VERSION 5.8 ;
BUSBITCHARS "[]" ;
DIVIDERCHAR "/" ;
UNITS
    DATABASE MICRONS 1000 ;
END UNITS

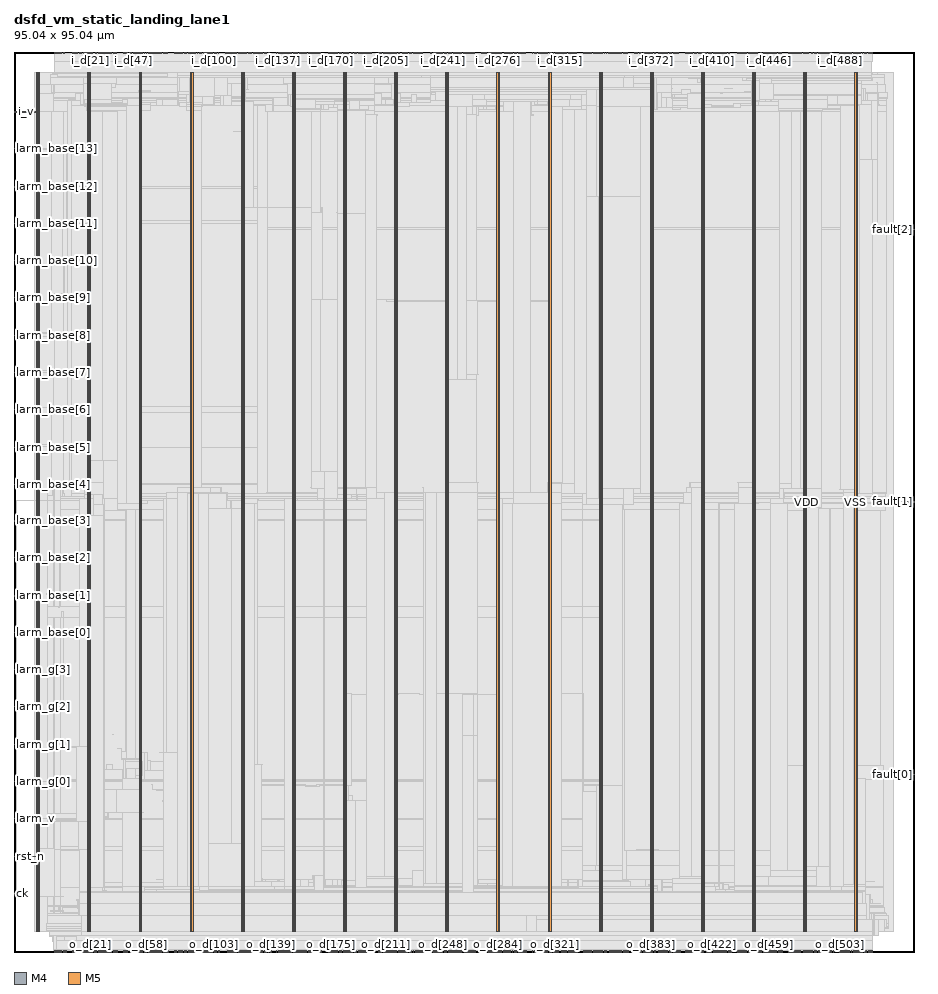
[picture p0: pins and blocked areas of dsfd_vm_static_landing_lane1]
MACRO dsfd_vm_static_landing_lane1
  FOREIGN dsfd_vm_static_landing_lane1 0 0 ;
  CLASS BLOCK ;
  SIZE 95.04 BY 95.04 ;
  PIN ck
    DIRECTION INPUT ;
    USE SIGNAL ;
    PORT
      LAYER M4 ;
        RECT  0 6.192 0.192 6.216 ;
    END
    PORT
      LAYER M4 ;
        RECT  0.156 6.192 0.275 6.216 ;
    END
  END ck
  PIN fault[0]
    DIRECTION OUTPUT ;
    USE SIGNAL ;
    PORT
      LAYER M4 ;
        RECT  94.848 18.72 95.04 18.744 ;
    END
    PORT
      LAYER M4 ;
        RECT  93.481 18.72 94.86 18.744 ;
    END
  END fault[0]
  PIN fault[1]
    DIRECTION OUTPUT ;
    USE SIGNAL ;
    PORT
      LAYER M4 ;
        RECT  94.848 47.52 95.04 47.544 ;
    END
    PORT
      LAYER M4 ;
        RECT  94.021 47.52 94.86 47.544 ;
    END
  END fault[1]
  PIN fault[2]
    DIRECTION OUTPUT ;
    USE SIGNAL ;
    PORT
      LAYER M4 ;
        RECT  94.848 76.32 95.04 76.344 ;
    END
    PORT
      LAYER M4 ;
        RECT  93.481 76.32 94.86 76.344 ;
    END
  END fault[2]
  PIN i_d[0]
    DIRECTION INPUT ;
    USE SIGNAL ;
    PORT
      LAYER M5 ;
        RECT  4.32 94.848 4.344 95.04 ;
    END
  END i_d[0]
  PIN i_d[100]
    DIRECTION INPUT ;
    USE SIGNAL ;
    PORT
      LAYER M5 ;
        RECT  21.12 94.848 21.144 95.04 ;
    END
  END i_d[100]
  PIN i_d[101]
    DIRECTION INPUT ;
    USE SIGNAL ;
    PORT
      LAYER M5 ;
        RECT  21.264 94.848 21.288 95.04 ;
    END
  END i_d[101]
  PIN i_d[102]
    DIRECTION INPUT ;
    USE SIGNAL ;
    PORT
      LAYER M5 ;
        RECT  21.408 94.848 21.432 95.04 ;
    END
  END i_d[102]
  PIN i_d[103]
    DIRECTION INPUT ;
    USE SIGNAL ;
    PORT
      LAYER M5 ;
        RECT  21.552 94.848 21.576 95.04 ;
    END
  END i_d[103]
  PIN i_d[104]
    DIRECTION INPUT ;
    USE SIGNAL ;
    PORT
      LAYER M5 ;
        RECT  22.368 94.848 22.392 95.04 ;
    END
  END i_d[104]
  PIN i_d[105]
    DIRECTION INPUT ;
    USE SIGNAL ;
    PORT
      LAYER M5 ;
        RECT  22.512 94.848 22.536 95.04 ;
    END
  END i_d[105]
  PIN i_d[106]
    DIRECTION INPUT ;
    USE SIGNAL ;
    PORT
      LAYER M5 ;
        RECT  22.656 94.848 22.68 95.04 ;
    END
  END i_d[106]
  PIN i_d[107]
    DIRECTION INPUT ;
    USE SIGNAL ;
    PORT
      LAYER M5 ;
        RECT  22.8 94.848 22.824 95.04 ;
    END
  END i_d[107]
  PIN i_d[108]
    DIRECTION INPUT ;
    USE SIGNAL ;
    PORT
      LAYER M5 ;
        RECT  22.944 94.848 22.968 95.04 ;
    END
  END i_d[108]
  PIN i_d[109]
    DIRECTION INPUT ;
    USE SIGNAL ;
    PORT
      LAYER M5 ;
        RECT  23.088 94.848 23.112 95.04 ;
    END
  END i_d[109]
  PIN i_d[10]
    DIRECTION INPUT ;
    USE SIGNAL ;
    PORT
      LAYER M5 ;
        RECT  6.432 94.848 6.456 95.04 ;
    END
  END i_d[10]
  PIN i_d[110]
    DIRECTION INPUT ;
    USE SIGNAL ;
    PORT
      LAYER M5 ;
        RECT  23.232 94.848 23.256 95.04 ;
    END
  END i_d[110]
  PIN i_d[111]
    DIRECTION INPUT ;
    USE SIGNAL ;
    PORT
      LAYER M5 ;
        RECT  23.376 94.848 23.4 95.04 ;
    END
  END i_d[111]
  PIN i_d[112]
    DIRECTION INPUT ;
    USE SIGNAL ;
    PORT
      LAYER M5 ;
        RECT  23.52 94.848 23.544 95.04 ;
    END
  END i_d[112]
  PIN i_d[113]
    DIRECTION INPUT ;
    USE SIGNAL ;
    PORT
      LAYER M5 ;
        RECT  23.664 94.848 23.688 95.04 ;
    END
  END i_d[113]
  PIN i_d[114]
    DIRECTION INPUT ;
    USE SIGNAL ;
    PORT
      LAYER M5 ;
        RECT  23.808 94.848 23.832 95.04 ;
    END
  END i_d[114]
  PIN i_d[115]
    DIRECTION INPUT ;
    USE SIGNAL ;
    PORT
      LAYER M5 ;
        RECT  23.952 94.848 23.976 95.04 ;
    END
  END i_d[115]
  PIN i_d[116]
    DIRECTION INPUT ;
    USE SIGNAL ;
    PORT
      LAYER M5 ;
        RECT  24.096 94.848 24.12 95.04 ;
    END
  END i_d[116]
  PIN i_d[117]
    DIRECTION INPUT ;
    USE SIGNAL ;
    PORT
      LAYER M5 ;
        RECT  24.24 94.848 24.264 95.04 ;
    END
  END i_d[117]
  PIN i_d[118]
    DIRECTION INPUT ;
    USE SIGNAL ;
    PORT
      LAYER M5 ;
        RECT  24.384 94.848 24.408 95.04 ;
    END
  END i_d[118]
  PIN i_d[119]
    DIRECTION INPUT ;
    USE SIGNAL ;
    PORT
      LAYER M5 ;
        RECT  24.528 94.848 24.552 95.04 ;
    END
  END i_d[119]
  PIN i_d[11]
    DIRECTION INPUT ;
    USE SIGNAL ;
    PORT
      LAYER M5 ;
        RECT  6.576 94.848 6.6 95.04 ;
    END
  END i_d[11]
  PIN i_d[120]
    DIRECTION INPUT ;
    USE SIGNAL ;
    PORT
      LAYER M5 ;
        RECT  24.816 94.848 24.84 95.04 ;
    END
  END i_d[120]
  PIN i_d[121]
    DIRECTION INPUT ;
    USE SIGNAL ;
    PORT
      LAYER M5 ;
        RECT  24.96 94.848 24.984 95.04 ;
    END
  END i_d[121]
  PIN i_d[122]
    DIRECTION INPUT ;
    USE SIGNAL ;
    PORT
      LAYER M5 ;
        RECT  25.104 94.848 25.128 95.04 ;
    END
  END i_d[122]
  PIN i_d[123]
    DIRECTION INPUT ;
    USE SIGNAL ;
    PORT
      LAYER M5 ;
        RECT  25.248 94.848 25.272 95.04 ;
    END
  END i_d[123]
  PIN i_d[124]
    DIRECTION INPUT ;
    USE SIGNAL ;
    PORT
      LAYER M5 ;
        RECT  25.392 94.848 25.416 95.04 ;
    END
  END i_d[124]
  PIN i_d[125]
    DIRECTION INPUT ;
    USE SIGNAL ;
    PORT
      LAYER M5 ;
        RECT  25.536 94.848 25.56 95.04 ;
    END
  END i_d[125]
  PIN i_d[126]
    DIRECTION INPUT ;
    USE SIGNAL ;
    PORT
      LAYER M5 ;
        RECT  25.68 94.848 25.704 95.04 ;
    END
  END i_d[126]
  PIN i_d[127]
    DIRECTION INPUT ;
    USE SIGNAL ;
    PORT
      LAYER M5 ;
        RECT  25.824 94.848 25.848 95.04 ;
    END
  END i_d[127]
  PIN i_d[128]
    DIRECTION INPUT ;
    USE SIGNAL ;
    PORT
      LAYER M5 ;
        RECT  25.968 94.848 25.992 95.04 ;
    END
  END i_d[128]
  PIN i_d[129]
    DIRECTION INPUT ;
    USE SIGNAL ;
    PORT
      LAYER M5 ;
        RECT  26.112 94.848 26.136 95.04 ;
    END
  END i_d[129]
  PIN i_d[12]
    DIRECTION INPUT ;
    USE SIGNAL ;
    PORT
      LAYER M5 ;
        RECT  6.72 94.848 6.744 95.04 ;
    END
  END i_d[12]
  PIN i_d[130]
    DIRECTION INPUT ;
    USE SIGNAL ;
    PORT
      LAYER M5 ;
        RECT  26.256 94.848 26.28 95.04 ;
    END
  END i_d[130]
  PIN i_d[131]
    DIRECTION INPUT ;
    USE SIGNAL ;
    PORT
      LAYER M5 ;
        RECT  26.4 94.848 26.424 95.04 ;
    END
  END i_d[131]
  PIN i_d[132]
    DIRECTION INPUT ;
    USE SIGNAL ;
    PORT
      LAYER M5 ;
        RECT  26.544 94.848 26.568 95.04 ;
    END
  END i_d[132]
  PIN i_d[133]
    DIRECTION INPUT ;
    USE SIGNAL ;
    PORT
      LAYER M5 ;
        RECT  26.688 94.848 26.712 95.04 ;
    END
  END i_d[133]
  PIN i_d[134]
    DIRECTION INPUT ;
    USE SIGNAL ;
    PORT
      LAYER M5 ;
        RECT  26.832 94.848 26.856 95.04 ;
    END
  END i_d[134]
  PIN i_d[135]
    DIRECTION INPUT ;
    USE SIGNAL ;
    PORT
      LAYER M5 ;
        RECT  26.976 94.848 27 95.04 ;
    END
  END i_d[135]
  PIN i_d[136]
    DIRECTION INPUT ;
    USE SIGNAL ;
    PORT
      LAYER M5 ;
        RECT  27.744 94.848 27.768 95.04 ;
    END
  END i_d[136]
  PIN i_d[137]
    DIRECTION INPUT ;
    USE SIGNAL ;
    PORT
      LAYER M5 ;
        RECT  27.888 94.848 27.912 95.04 ;
    END
  END i_d[137]
  PIN i_d[138]
    DIRECTION INPUT ;
    USE SIGNAL ;
    PORT
      LAYER M5 ;
        RECT  28.032 94.848 28.056 95.04 ;
    END
  END i_d[138]
  PIN i_d[139]
    DIRECTION INPUT ;
    USE SIGNAL ;
    PORT
      LAYER M5 ;
        RECT  28.176 94.848 28.2 95.04 ;
    END
  END i_d[139]
  PIN i_d[13]
    DIRECTION INPUT ;
    USE SIGNAL ;
    PORT
      LAYER M5 ;
        RECT  6.864 94.848 6.888 95.04 ;
    END
  END i_d[13]
  PIN i_d[140]
    DIRECTION INPUT ;
    USE SIGNAL ;
    PORT
      LAYER M5 ;
        RECT  28.32 94.848 28.344 95.04 ;
    END
  END i_d[140]
  PIN i_d[141]
    DIRECTION INPUT ;
    USE SIGNAL ;
    PORT
      LAYER M5 ;
        RECT  28.464 94.848 28.488 95.04 ;
    END
  END i_d[141]
  PIN i_d[142]
    DIRECTION INPUT ;
    USE SIGNAL ;
    PORT
      LAYER M5 ;
        RECT  28.608 94.848 28.632 95.04 ;
    END
  END i_d[142]
  PIN i_d[143]
    DIRECTION INPUT ;
    USE SIGNAL ;
    PORT
      LAYER M5 ;
        RECT  28.752 94.848 28.776 95.04 ;
    END
  END i_d[143]
  PIN i_d[144]
    DIRECTION INPUT ;
    USE SIGNAL ;
    PORT
      LAYER M5 ;
        RECT  28.896 94.848 28.92 95.04 ;
    END
  END i_d[144]
  PIN i_d[145]
    DIRECTION INPUT ;
    USE SIGNAL ;
    PORT
      LAYER M5 ;
        RECT  29.04 94.848 29.064 95.04 ;
    END
  END i_d[145]
  PIN i_d[146]
    DIRECTION INPUT ;
    USE SIGNAL ;
    PORT
      LAYER M5 ;
        RECT  29.184 94.848 29.208 95.04 ;
    END
  END i_d[146]
  PIN i_d[147]
    DIRECTION INPUT ;
    USE SIGNAL ;
    PORT
      LAYER M5 ;
        RECT  29.328 94.848 29.352 95.04 ;
    END
  END i_d[147]
  PIN i_d[148]
    DIRECTION INPUT ;
    USE SIGNAL ;
    PORT
      LAYER M5 ;
        RECT  29.472 94.848 29.496 95.04 ;
    END
  END i_d[148]
  PIN i_d[149]
    DIRECTION INPUT ;
    USE SIGNAL ;
    PORT
      LAYER M5 ;
        RECT  29.616 94.848 29.64 95.04 ;
    END
  END i_d[149]
  PIN i_d[14]
    DIRECTION INPUT ;
    USE SIGNAL ;
    PORT
      LAYER M5 ;
        RECT  7.008 94.848 7.032 95.04 ;
    END
  END i_d[14]
  PIN i_d[150]
    DIRECTION INPUT ;
    USE SIGNAL ;
    PORT
      LAYER M5 ;
        RECT  29.76 94.848 29.784 95.04 ;
    END
  END i_d[150]
  PIN i_d[151]
    DIRECTION INPUT ;
    USE SIGNAL ;
    PORT
      LAYER M5 ;
        RECT  29.904 94.848 29.928 95.04 ;
    END
  END i_d[151]
  PIN i_d[152]
    DIRECTION INPUT ;
    USE SIGNAL ;
    PORT
      LAYER M5 ;
        RECT  30.192 94.848 30.216 95.04 ;
    END
  END i_d[152]
  PIN i_d[153]
    DIRECTION INPUT ;
    USE SIGNAL ;
    PORT
      LAYER M5 ;
        RECT  30.336 94.848 30.36 95.04 ;
    END
  END i_d[153]
  PIN i_d[154]
    DIRECTION INPUT ;
    USE SIGNAL ;
    PORT
      LAYER M5 ;
        RECT  30.48 94.848 30.504 95.04 ;
    END
  END i_d[154]
  PIN i_d[155]
    DIRECTION INPUT ;
    USE SIGNAL ;
    PORT
      LAYER M5 ;
        RECT  30.624 94.848 30.648 95.04 ;
    END
  END i_d[155]
  PIN i_d[156]
    DIRECTION INPUT ;
    USE SIGNAL ;
    PORT
      LAYER M5 ;
        RECT  30.768 94.848 30.792 95.04 ;
    END
  END i_d[156]
  PIN i_d[157]
    DIRECTION INPUT ;
    USE SIGNAL ;
    PORT
      LAYER M5 ;
        RECT  30.912 94.848 30.936 95.04 ;
    END
  END i_d[157]
  PIN i_d[158]
    DIRECTION INPUT ;
    USE SIGNAL ;
    PORT
      LAYER M5 ;
        RECT  31.056 94.848 31.08 95.04 ;
    END
  END i_d[158]
  PIN i_d[159]
    DIRECTION INPUT ;
    USE SIGNAL ;
    PORT
      LAYER M5 ;
        RECT  31.2 94.848 31.224 95.04 ;
    END
  END i_d[159]
  PIN i_d[15]
    DIRECTION INPUT ;
    USE SIGNAL ;
    PORT
      LAYER M5 ;
        RECT  7.152 94.848 7.176 95.04 ;
    END
  END i_d[15]
  PIN i_d[160]
    DIRECTION INPUT ;
    USE SIGNAL ;
    PORT
      LAYER M5 ;
        RECT  31.344 94.848 31.368 95.04 ;
    END
  END i_d[160]
  PIN i_d[161]
    DIRECTION INPUT ;
    USE SIGNAL ;
    PORT
      LAYER M5 ;
        RECT  31.488 94.848 31.512 95.04 ;
    END
  END i_d[161]
  PIN i_d[162]
    DIRECTION INPUT ;
    USE SIGNAL ;
    PORT
      LAYER M5 ;
        RECT  31.632 94.848 31.656 95.04 ;
    END
  END i_d[162]
  PIN i_d[163]
    DIRECTION INPUT ;
    USE SIGNAL ;
    PORT
      LAYER M5 ;
        RECT  31.776 94.848 31.8 95.04 ;
    END
  END i_d[163]
  PIN i_d[164]
    DIRECTION INPUT ;
    USE SIGNAL ;
    PORT
      LAYER M5 ;
        RECT  31.92 94.848 31.944 95.04 ;
    END
  END i_d[164]
  PIN i_d[165]
    DIRECTION INPUT ;
    USE SIGNAL ;
    PORT
      LAYER M5 ;
        RECT  32.064 94.848 32.088 95.04 ;
    END
  END i_d[165]
  PIN i_d[166]
    DIRECTION INPUT ;
    USE SIGNAL ;
    PORT
      LAYER M5 ;
        RECT  32.208 94.848 32.232 95.04 ;
    END
  END i_d[166]
  PIN i_d[167]
    DIRECTION INPUT ;
    USE SIGNAL ;
    PORT
      LAYER M5 ;
        RECT  32.352 94.848 32.376 95.04 ;
    END
  END i_d[167]
  PIN i_d[168]
    DIRECTION INPUT ;
    USE SIGNAL ;
    PORT
      LAYER M5 ;
        RECT  33.168 94.848 33.192 95.04 ;
    END
  END i_d[168]
  PIN i_d[169]
    DIRECTION INPUT ;
    USE SIGNAL ;
    PORT
      LAYER M5 ;
        RECT  33.312 94.848 33.336 95.04 ;
    END
  END i_d[169]
  PIN i_d[16]
    DIRECTION INPUT ;
    USE SIGNAL ;
    PORT
      LAYER M5 ;
        RECT  7.296 94.848 7.32 95.04 ;
    END
  END i_d[16]
  PIN i_d[170]
    DIRECTION INPUT ;
    USE SIGNAL ;
    PORT
      LAYER M5 ;
        RECT  33.456 94.848 33.48 95.04 ;
    END
  END i_d[170]
  PIN i_d[171]
    DIRECTION INPUT ;
    USE SIGNAL ;
    PORT
      LAYER M5 ;
        RECT  33.6 94.848 33.624 95.04 ;
    END
  END i_d[171]
  PIN i_d[172]
    DIRECTION INPUT ;
    USE SIGNAL ;
    PORT
      LAYER M5 ;
        RECT  33.744 94.848 33.768 95.04 ;
    END
  END i_d[172]
  PIN i_d[173]
    DIRECTION INPUT ;
    USE SIGNAL ;
    PORT
      LAYER M5 ;
        RECT  33.888 94.848 33.912 95.04 ;
    END
  END i_d[173]
  PIN i_d[174]
    DIRECTION INPUT ;
    USE SIGNAL ;
    PORT
      LAYER M5 ;
        RECT  34.032 94.848 34.056 95.04 ;
    END
  END i_d[174]
  PIN i_d[175]
    DIRECTION INPUT ;
    USE SIGNAL ;
    PORT
      LAYER M5 ;
        RECT  34.176 94.848 34.2 95.04 ;
    END
  END i_d[175]
  PIN i_d[176]
    DIRECTION INPUT ;
    USE SIGNAL ;
    PORT
      LAYER M5 ;
        RECT  34.32 94.848 34.344 95.04 ;
    END
  END i_d[176]
  PIN i_d[177]
    DIRECTION INPUT ;
    USE SIGNAL ;
    PORT
      LAYER M5 ;
        RECT  34.464 94.848 34.488 95.04 ;
    END
  END i_d[177]
  PIN i_d[178]
    DIRECTION INPUT ;
    USE SIGNAL ;
    PORT
      LAYER M5 ;
        RECT  34.608 94.848 34.632 95.04 ;
    END
  END i_d[178]
  PIN i_d[179]
    DIRECTION INPUT ;
    USE SIGNAL ;
    PORT
      LAYER M5 ;
        RECT  34.752 94.848 34.776 95.04 ;
    END
  END i_d[179]
  PIN i_d[17]
    DIRECTION INPUT ;
    USE SIGNAL ;
    PORT
      LAYER M5 ;
        RECT  7.44 94.848 7.464 95.04 ;
    END
  END i_d[17]
  PIN i_d[180]
    DIRECTION INPUT ;
    USE SIGNAL ;
    PORT
      LAYER M5 ;
        RECT  34.896 94.848 34.92 95.04 ;
    END
  END i_d[180]
  PIN i_d[181]
    DIRECTION INPUT ;
    USE SIGNAL ;
    PORT
      LAYER M5 ;
        RECT  35.04 94.848 35.064 95.04 ;
    END
  END i_d[181]
  PIN i_d[182]
    DIRECTION INPUT ;
    USE SIGNAL ;
    PORT
      LAYER M5 ;
        RECT  35.184 94.848 35.208 95.04 ;
    END
  END i_d[182]
  PIN i_d[183]
    DIRECTION INPUT ;
    USE SIGNAL ;
    PORT
      LAYER M5 ;
        RECT  35.328 94.848 35.352 95.04 ;
    END
  END i_d[183]
  PIN i_d[184]
    DIRECTION INPUT ;
    USE SIGNAL ;
    PORT
      LAYER M5 ;
        RECT  35.616 94.848 35.64 95.04 ;
    END
  END i_d[184]
  PIN i_d[185]
    DIRECTION INPUT ;
    USE SIGNAL ;
    PORT
      LAYER M5 ;
        RECT  35.76 94.848 35.784 95.04 ;
    END
  END i_d[185]
  PIN i_d[186]
    DIRECTION INPUT ;
    USE SIGNAL ;
    PORT
      LAYER M5 ;
        RECT  35.904 94.848 35.928 95.04 ;
    END
  END i_d[186]
  PIN i_d[187]
    DIRECTION INPUT ;
    USE SIGNAL ;
    PORT
      LAYER M5 ;
        RECT  36.048 94.848 36.072 95.04 ;
    END
  END i_d[187]
  PIN i_d[188]
    DIRECTION INPUT ;
    USE SIGNAL ;
    PORT
      LAYER M5 ;
        RECT  36.192 94.848 36.216 95.04 ;
    END
  END i_d[188]
  PIN i_d[189]
    DIRECTION INPUT ;
    USE SIGNAL ;
    PORT
      LAYER M5 ;
        RECT  36.336 94.848 36.36 95.04 ;
    END
  END i_d[189]
  PIN i_d[18]
    DIRECTION INPUT ;
    USE SIGNAL ;
    PORT
      LAYER M5 ;
        RECT  7.584 94.848 7.608 95.04 ;
    END
  END i_d[18]
  PIN i_d[190]
    DIRECTION INPUT ;
    USE SIGNAL ;
    PORT
      LAYER M5 ;
        RECT  36.48 94.848 36.504 95.04 ;
    END
  END i_d[190]
  PIN i_d[191]
    DIRECTION INPUT ;
    USE SIGNAL ;
    PORT
      LAYER M5 ;
        RECT  36.624 94.848 36.648 95.04 ;
    END
  END i_d[191]
  PIN i_d[192]
    DIRECTION INPUT ;
    USE SIGNAL ;
    PORT
      LAYER M5 ;
        RECT  36.768 94.848 36.792 95.04 ;
    END
  END i_d[192]
  PIN i_d[193]
    DIRECTION INPUT ;
    USE SIGNAL ;
    PORT
      LAYER M5 ;
        RECT  36.912 94.848 36.936 95.04 ;
    END
  END i_d[193]
  PIN i_d[194]
    DIRECTION INPUT ;
    USE SIGNAL ;
    PORT
      LAYER M5 ;
        RECT  37.056 94.848 37.08 95.04 ;
    END
  END i_d[194]
  PIN i_d[195]
    DIRECTION INPUT ;
    USE SIGNAL ;
    PORT
      LAYER M5 ;
        RECT  37.2 94.848 37.224 95.04 ;
    END
  END i_d[195]
  PIN i_d[196]
    DIRECTION INPUT ;
    USE SIGNAL ;
    PORT
      LAYER M5 ;
        RECT  37.344 94.848 37.368 95.04 ;
    END
  END i_d[196]
  PIN i_d[197]
    DIRECTION INPUT ;
    USE SIGNAL ;
    PORT
      LAYER M5 ;
        RECT  37.488 94.848 37.512 95.04 ;
    END
  END i_d[197]
  PIN i_d[198]
    DIRECTION INPUT ;
    USE SIGNAL ;
    PORT
      LAYER M5 ;
        RECT  37.632 94.848 37.656 95.04 ;
    END
  END i_d[198]
  PIN i_d[199]
    DIRECTION INPUT ;
    USE SIGNAL ;
    PORT
      LAYER M5 ;
        RECT  37.776 94.848 37.8 95.04 ;
    END
  END i_d[199]
  PIN i_d[19]
    DIRECTION INPUT ;
    USE SIGNAL ;
    PORT
      LAYER M5 ;
        RECT  7.728 94.848 7.752 95.04 ;
    END
  END i_d[19]
  PIN i_d[1]
    DIRECTION INPUT ;
    USE SIGNAL ;
    PORT
      LAYER M5 ;
        RECT  4.464 94.848 4.488 95.04 ;
    END
  END i_d[1]
  PIN i_d[200]
    DIRECTION INPUT ;
    USE SIGNAL ;
    PORT
      LAYER M5 ;
        RECT  38.544 94.848 38.568 95.04 ;
    END
  END i_d[200]
  PIN i_d[201]
    DIRECTION INPUT ;
    USE SIGNAL ;
    PORT
      LAYER M5 ;
        RECT  38.688 94.848 38.712 95.04 ;
    END
  END i_d[201]
  PIN i_d[202]
    DIRECTION INPUT ;
    USE SIGNAL ;
    PORT
      LAYER M5 ;
        RECT  38.832 94.848 38.856 95.04 ;
    END
  END i_d[202]
  PIN i_d[203]
    DIRECTION INPUT ;
    USE SIGNAL ;
    PORT
      LAYER M5 ;
        RECT  38.976 94.848 39 95.04 ;
    END
  END i_d[203]
  PIN i_d[204]
    DIRECTION INPUT ;
    USE SIGNAL ;
    PORT
      LAYER M5 ;
        RECT  39.12 94.848 39.144 95.04 ;
    END
  END i_d[204]
  PIN i_d[205]
    DIRECTION INPUT ;
    USE SIGNAL ;
    PORT
      LAYER M5 ;
        RECT  39.264 94.848 39.288 95.04 ;
    END
  END i_d[205]
  PIN i_d[206]
    DIRECTION INPUT ;
    USE SIGNAL ;
    PORT
      LAYER M5 ;
        RECT  39.408 94.848 39.432 95.04 ;
    END
  END i_d[206]
  PIN i_d[207]
    DIRECTION INPUT ;
    USE SIGNAL ;
    PORT
      LAYER M5 ;
        RECT  39.552 94.848 39.576 95.04 ;
    END
  END i_d[207]
  PIN i_d[208]
    DIRECTION INPUT ;
    USE SIGNAL ;
    PORT
      LAYER M5 ;
        RECT  39.696 94.848 39.72 95.04 ;
    END
  END i_d[208]
  PIN i_d[209]
    DIRECTION INPUT ;
    USE SIGNAL ;
    PORT
      LAYER M5 ;
        RECT  39.84 94.848 39.864 95.04 ;
    END
  END i_d[209]
  PIN i_d[20]
    DIRECTION INPUT ;
    USE SIGNAL ;
    PORT
      LAYER M5 ;
        RECT  7.872 94.848 7.896 95.04 ;
    END
  END i_d[20]
  PIN i_d[210]
    DIRECTION INPUT ;
    USE SIGNAL ;
    PORT
      LAYER M5 ;
        RECT  39.984 94.848 40.008 95.04 ;
    END
  END i_d[210]
  PIN i_d[211]
    DIRECTION INPUT ;
    USE SIGNAL ;
    PORT
      LAYER M5 ;
        RECT  40.128 94.848 40.152 95.04 ;
    END
  END i_d[211]
  PIN i_d[212]
    DIRECTION INPUT ;
    USE SIGNAL ;
    PORT
      LAYER M5 ;
        RECT  40.272 94.848 40.296 95.04 ;
    END
  END i_d[212]
  PIN i_d[213]
    DIRECTION INPUT ;
    USE SIGNAL ;
    PORT
      LAYER M5 ;
        RECT  40.416 94.848 40.44 95.04 ;
    END
  END i_d[213]
  PIN i_d[214]
    DIRECTION INPUT ;
    USE SIGNAL ;
    PORT
      LAYER M5 ;
        RECT  40.56 94.848 40.584 95.04 ;
    END
  END i_d[214]
  PIN i_d[215]
    DIRECTION INPUT ;
    USE SIGNAL ;
    PORT
      LAYER M5 ;
        RECT  40.704 94.848 40.728 95.04 ;
    END
  END i_d[215]
  PIN i_d[216]
    DIRECTION INPUT ;
    USE SIGNAL ;
    PORT
      LAYER M5 ;
        RECT  40.992 94.848 41.016 95.04 ;
    END
  END i_d[216]
  PIN i_d[217]
    DIRECTION INPUT ;
    USE SIGNAL ;
    PORT
      LAYER M5 ;
        RECT  41.136 94.848 41.16 95.04 ;
    END
  END i_d[217]
  PIN i_d[218]
    DIRECTION INPUT ;
    USE SIGNAL ;
    PORT
      LAYER M5 ;
        RECT  41.28 94.848 41.304 95.04 ;
    END
  END i_d[218]
  PIN i_d[219]
    DIRECTION INPUT ;
    USE SIGNAL ;
    PORT
      LAYER M5 ;
        RECT  41.424 94.848 41.448 95.04 ;
    END
  END i_d[219]
  PIN i_d[21]
    DIRECTION INPUT ;
    USE SIGNAL ;
    PORT
      LAYER M5 ;
        RECT  8.016 94.848 8.04 95.04 ;
    END
  END i_d[21]
  PIN i_d[220]
    DIRECTION INPUT ;
    USE SIGNAL ;
    PORT
      LAYER M5 ;
        RECT  41.568 94.848 41.592 95.04 ;
    END
  END i_d[220]
  PIN i_d[221]
    DIRECTION INPUT ;
    USE SIGNAL ;
    PORT
      LAYER M5 ;
        RECT  41.712 94.848 41.736 95.04 ;
    END
  END i_d[221]
  PIN i_d[222]
    DIRECTION INPUT ;
    USE SIGNAL ;
    PORT
      LAYER M5 ;
        RECT  41.856 94.848 41.88 95.04 ;
    END
  END i_d[222]
  PIN i_d[223]
    DIRECTION INPUT ;
    USE SIGNAL ;
    PORT
      LAYER M5 ;
        RECT  42 94.848 42.024 95.04 ;
    END
  END i_d[223]
  PIN i_d[224]
    DIRECTION INPUT ;
    USE SIGNAL ;
    PORT
      LAYER M5 ;
        RECT  42.144 94.848 42.168 95.04 ;
    END
  END i_d[224]
  PIN i_d[225]
    DIRECTION INPUT ;
    USE SIGNAL ;
    PORT
      LAYER M5 ;
        RECT  42.288 94.848 42.312 95.04 ;
    END
  END i_d[225]
  PIN i_d[226]
    DIRECTION INPUT ;
    USE SIGNAL ;
    PORT
      LAYER M5 ;
        RECT  42.432 94.848 42.456 95.04 ;
    END
  END i_d[226]
  PIN i_d[227]
    DIRECTION INPUT ;
    USE SIGNAL ;
    PORT
      LAYER M5 ;
        RECT  42.576 94.848 42.6 95.04 ;
    END
  END i_d[227]
  PIN i_d[228]
    DIRECTION INPUT ;
    USE SIGNAL ;
    PORT
      LAYER M5 ;
        RECT  42.72 94.848 42.744 95.04 ;
    END
  END i_d[228]
  PIN i_d[229]
    DIRECTION INPUT ;
    USE SIGNAL ;
    PORT
      LAYER M5 ;
        RECT  42.864 94.848 42.888 95.04 ;
    END
  END i_d[229]
  PIN i_d[22]
    DIRECTION INPUT ;
    USE SIGNAL ;
    PORT
      LAYER M5 ;
        RECT  8.16 94.848 8.184 95.04 ;
    END
  END i_d[22]
  PIN i_d[230]
    DIRECTION INPUT ;
    USE SIGNAL ;
    PORT
      LAYER M5 ;
        RECT  43.008 94.848 43.032 95.04 ;
    END
  END i_d[230]
  PIN i_d[231]
    DIRECTION INPUT ;
    USE SIGNAL ;
    PORT
      LAYER M5 ;
        RECT  43.152 94.848 43.176 95.04 ;
    END
  END i_d[231]
  PIN i_d[232]
    DIRECTION INPUT ;
    USE SIGNAL ;
    PORT
      LAYER M5 ;
        RECT  43.968 94.848 43.992 95.04 ;
    END
  END i_d[232]
  PIN i_d[233]
    DIRECTION INPUT ;
    USE SIGNAL ;
    PORT
      LAYER M5 ;
        RECT  44.112 94.848 44.136 95.04 ;
    END
  END i_d[233]
  PIN i_d[234]
    DIRECTION INPUT ;
    USE SIGNAL ;
    PORT
      LAYER M5 ;
        RECT  44.256 94.848 44.28 95.04 ;
    END
  END i_d[234]
  PIN i_d[235]
    DIRECTION INPUT ;
    USE SIGNAL ;
    PORT
      LAYER M5 ;
        RECT  44.4 94.848 44.424 95.04 ;
    END
  END i_d[235]
  PIN i_d[236]
    DIRECTION INPUT ;
    USE SIGNAL ;
    PORT
      LAYER M5 ;
        RECT  44.544 94.848 44.568 95.04 ;
    END
  END i_d[236]
  PIN i_d[237]
    DIRECTION INPUT ;
    USE SIGNAL ;
    PORT
      LAYER M5 ;
        RECT  44.688 94.848 44.712 95.04 ;
    END
  END i_d[237]
  PIN i_d[238]
    DIRECTION INPUT ;
    USE SIGNAL ;
    PORT
      LAYER M5 ;
        RECT  44.832 94.848 44.856 95.04 ;
    END
  END i_d[238]
  PIN i_d[239]
    DIRECTION INPUT ;
    USE SIGNAL ;
    PORT
      LAYER M5 ;
        RECT  44.976 94.848 45 95.04 ;
    END
  END i_d[239]
  PIN i_d[23]
    DIRECTION INPUT ;
    USE SIGNAL ;
    PORT
      LAYER M5 ;
        RECT  8.304 94.848 8.328 95.04 ;
    END
  END i_d[23]
  PIN i_d[240]
    DIRECTION INPUT ;
    USE SIGNAL ;
    PORT
      LAYER M5 ;
        RECT  45.12 94.848 45.144 95.04 ;
    END
  END i_d[240]
  PIN i_d[241]
    DIRECTION INPUT ;
    USE SIGNAL ;
    PORT
      LAYER M5 ;
        RECT  45.264 94.848 45.288 95.04 ;
    END
  END i_d[241]
  PIN i_d[242]
    DIRECTION INPUT ;
    USE SIGNAL ;
    PORT
      LAYER M5 ;
        RECT  45.408 94.848 45.432 95.04 ;
    END
  END i_d[242]
  PIN i_d[243]
    DIRECTION INPUT ;
    USE SIGNAL ;
    PORT
      LAYER M5 ;
        RECT  45.552 94.848 45.576 95.04 ;
    END
  END i_d[243]
  PIN i_d[244]
    DIRECTION INPUT ;
    USE SIGNAL ;
    PORT
      LAYER M5 ;
        RECT  45.696 94.848 45.72 95.04 ;
    END
  END i_d[244]
  PIN i_d[245]
    DIRECTION INPUT ;
    USE SIGNAL ;
    PORT
      LAYER M5 ;
        RECT  45.84 94.848 45.864 95.04 ;
    END
  END i_d[245]
  PIN i_d[246]
    DIRECTION INPUT ;
    USE SIGNAL ;
    PORT
      LAYER M5 ;
        RECT  45.984 94.848 46.008 95.04 ;
    END
  END i_d[246]
  PIN i_d[247]
    DIRECTION INPUT ;
    USE SIGNAL ;
    PORT
      LAYER M5 ;
        RECT  46.128 94.848 46.152 95.04 ;
    END
  END i_d[247]
  PIN i_d[248]
    DIRECTION INPUT ;
    USE SIGNAL ;
    PORT
      LAYER M5 ;
        RECT  46.416 94.848 46.44 95.04 ;
    END
  END i_d[248]
  PIN i_d[249]
    DIRECTION INPUT ;
    USE SIGNAL ;
    PORT
      LAYER M5 ;
        RECT  46.56 94.848 46.584 95.04 ;
    END
  END i_d[249]
  PIN i_d[24]
    DIRECTION INPUT ;
    USE SIGNAL ;
    PORT
      LAYER M5 ;
        RECT  8.592 94.848 8.616 95.04 ;
    END
  END i_d[24]
  PIN i_d[250]
    DIRECTION INPUT ;
    USE SIGNAL ;
    PORT
      LAYER M5 ;
        RECT  46.704 94.848 46.728 95.04 ;
    END
  END i_d[250]
  PIN i_d[251]
    DIRECTION INPUT ;
    USE SIGNAL ;
    PORT
      LAYER M5 ;
        RECT  46.848 94.848 46.872 95.04 ;
    END
  END i_d[251]
  PIN i_d[252]
    DIRECTION INPUT ;
    USE SIGNAL ;
    PORT
      LAYER M5 ;
        RECT  46.992 94.848 47.016 95.04 ;
    END
  END i_d[252]
  PIN i_d[253]
    DIRECTION INPUT ;
    USE SIGNAL ;
    PORT
      LAYER M5 ;
        RECT  47.136 94.848 47.16 95.04 ;
    END
  END i_d[253]
  PIN i_d[254]
    DIRECTION INPUT ;
    USE SIGNAL ;
    PORT
      LAYER M5 ;
        RECT  47.28 94.848 47.304 95.04 ;
    END
  END i_d[254]
  PIN i_d[255]
    DIRECTION INPUT ;
    USE SIGNAL ;
    PORT
      LAYER M5 ;
        RECT  47.424 94.848 47.448 95.04 ;
    END
  END i_d[255]
  PIN i_d[256]
    DIRECTION INPUT ;
    USE SIGNAL ;
    PORT
      LAYER M5 ;
        RECT  47.568 94.848 47.592 95.04 ;
    END
  END i_d[256]
  PIN i_d[257]
    DIRECTION INPUT ;
    USE SIGNAL ;
    PORT
      LAYER M5 ;
        RECT  47.712 94.848 47.736 95.04 ;
    END
  END i_d[257]
  PIN i_d[258]
    DIRECTION INPUT ;
    USE SIGNAL ;
    PORT
      LAYER M5 ;
        RECT  47.856 94.848 47.88 95.04 ;
    END
  END i_d[258]
  PIN i_d[259]
    DIRECTION INPUT ;
    USE SIGNAL ;
    PORT
      LAYER M5 ;
        RECT  48 94.848 48.024 95.04 ;
    END
  END i_d[259]
  PIN i_d[25]
    DIRECTION INPUT ;
    USE SIGNAL ;
    PORT
      LAYER M5 ;
        RECT  8.736 94.848 8.76 95.04 ;
    END
  END i_d[25]
  PIN i_d[260]
    DIRECTION INPUT ;
    USE SIGNAL ;
    PORT
      LAYER M5 ;
        RECT  48.144 94.848 48.168 95.04 ;
    END
  END i_d[260]
  PIN i_d[261]
    DIRECTION INPUT ;
    USE SIGNAL ;
    PORT
      LAYER M5 ;
        RECT  48.288 94.848 48.312 95.04 ;
    END
  END i_d[261]
  PIN i_d[262]
    DIRECTION INPUT ;
    USE SIGNAL ;
    PORT
      LAYER M5 ;
        RECT  48.432 94.848 48.456 95.04 ;
    END
  END i_d[262]
  PIN i_d[263]
    DIRECTION INPUT ;
    USE SIGNAL ;
    PORT
      LAYER M5 ;
        RECT  48.576 94.848 48.6 95.04 ;
    END
  END i_d[263]
  PIN i_d[264]
    DIRECTION INPUT ;
    USE SIGNAL ;
    PORT
      LAYER M5 ;
        RECT  49.344 94.848 49.368 95.04 ;
    END
  END i_d[264]
  PIN i_d[265]
    DIRECTION INPUT ;
    USE SIGNAL ;
    PORT
      LAYER M5 ;
        RECT  49.488 94.848 49.512 95.04 ;
    END
  END i_d[265]
  PIN i_d[266]
    DIRECTION INPUT ;
    USE SIGNAL ;
    PORT
      LAYER M5 ;
        RECT  49.632 94.848 49.656 95.04 ;
    END
  END i_d[266]
  PIN i_d[267]
    DIRECTION INPUT ;
    USE SIGNAL ;
    PORT
      LAYER M5 ;
        RECT  49.776 94.848 49.8 95.04 ;
    END
  END i_d[267]
  PIN i_d[268]
    DIRECTION INPUT ;
    USE SIGNAL ;
    PORT
      LAYER M5 ;
        RECT  49.92 94.848 49.944 95.04 ;
    END
  END i_d[268]
  PIN i_d[269]
    DIRECTION INPUT ;
    USE SIGNAL ;
    PORT
      LAYER M5 ;
        RECT  50.064 94.848 50.088 95.04 ;
    END
  END i_d[269]
  PIN i_d[26]
    DIRECTION INPUT ;
    USE SIGNAL ;
    PORT
      LAYER M5 ;
        RECT  8.88 94.848 8.904 95.04 ;
    END
  END i_d[26]
  PIN i_d[270]
    DIRECTION INPUT ;
    USE SIGNAL ;
    PORT
      LAYER M5 ;
        RECT  50.208 94.848 50.232 95.04 ;
    END
  END i_d[270]
  PIN i_d[271]
    DIRECTION INPUT ;
    USE SIGNAL ;
    PORT
      LAYER M5 ;
        RECT  50.352 94.848 50.376 95.04 ;
    END
  END i_d[271]
  PIN i_d[272]
    DIRECTION INPUT ;
    USE SIGNAL ;
    PORT
      LAYER M5 ;
        RECT  50.496 94.848 50.52 95.04 ;
    END
  END i_d[272]
  PIN i_d[273]
    DIRECTION INPUT ;
    USE SIGNAL ;
    PORT
      LAYER M5 ;
        RECT  50.64 94.848 50.664 95.04 ;
    END
  END i_d[273]
  PIN i_d[274]
    DIRECTION INPUT ;
    USE SIGNAL ;
    PORT
      LAYER M5 ;
        RECT  50.784 94.848 50.808 95.04 ;
    END
  END i_d[274]
  PIN i_d[275]
    DIRECTION INPUT ;
    USE SIGNAL ;
    PORT
      LAYER M5 ;
        RECT  50.928 94.848 50.952 95.04 ;
    END
  END i_d[275]
  PIN i_d[276]
    DIRECTION INPUT ;
    USE SIGNAL ;
    PORT
      LAYER M5 ;
        RECT  51.072 94.848 51.096 95.04 ;
    END
  END i_d[276]
  PIN i_d[277]
    DIRECTION INPUT ;
    USE SIGNAL ;
    PORT
      LAYER M5 ;
        RECT  51.216 94.848 51.24 95.04 ;
    END
  END i_d[277]
  PIN i_d[278]
    DIRECTION INPUT ;
    USE SIGNAL ;
    PORT
      LAYER M5 ;
        RECT  51.36 94.848 51.384 95.04 ;
    END
  END i_d[278]
  PIN i_d[279]
    DIRECTION INPUT ;
    USE SIGNAL ;
    PORT
      LAYER M5 ;
        RECT  51.504 94.848 51.528 95.04 ;
    END
  END i_d[279]
  PIN i_d[27]
    DIRECTION INPUT ;
    USE SIGNAL ;
    PORT
      LAYER M5 ;
        RECT  9.024 94.848 9.048 95.04 ;
    END
  END i_d[27]
  PIN i_d[280]
    DIRECTION INPUT ;
    USE SIGNAL ;
    PORT
      LAYER M5 ;
        RECT  51.792 94.848 51.816 95.04 ;
    END
  END i_d[280]
  PIN i_d[281]
    DIRECTION INPUT ;
    USE SIGNAL ;
    PORT
      LAYER M5 ;
        RECT  51.936 94.848 51.96 95.04 ;
    END
  END i_d[281]
  PIN i_d[282]
    DIRECTION INPUT ;
    USE SIGNAL ;
    PORT
      LAYER M5 ;
        RECT  52.08 94.848 52.104 95.04 ;
    END
  END i_d[282]
  PIN i_d[283]
    DIRECTION INPUT ;
    USE SIGNAL ;
    PORT
      LAYER M5 ;
        RECT  52.224 94.848 52.248 95.04 ;
    END
  END i_d[283]
  PIN i_d[284]
    DIRECTION INPUT ;
    USE SIGNAL ;
    PORT
      LAYER M5 ;
        RECT  52.368 94.848 52.392 95.04 ;
    END
  END i_d[284]
  PIN i_d[285]
    DIRECTION INPUT ;
    USE SIGNAL ;
    PORT
      LAYER M5 ;
        RECT  52.512 94.848 52.536 95.04 ;
    END
  END i_d[285]
  PIN i_d[286]
    DIRECTION INPUT ;
    USE SIGNAL ;
    PORT
      LAYER M5 ;
        RECT  52.656 94.848 52.68 95.04 ;
    END
  END i_d[286]
  PIN i_d[287]
    DIRECTION INPUT ;
    USE SIGNAL ;
    PORT
      LAYER M5 ;
        RECT  52.8 94.848 52.824 95.04 ;
    END
  END i_d[287]
  PIN i_d[288]
    DIRECTION INPUT ;
    USE SIGNAL ;
    PORT
      LAYER M5 ;
        RECT  52.944 94.848 52.968 95.04 ;
    END
  END i_d[288]
  PIN i_d[289]
    DIRECTION INPUT ;
    USE SIGNAL ;
    PORT
      LAYER M5 ;
        RECT  53.088 94.848 53.112 95.04 ;
    END
  END i_d[289]
  PIN i_d[28]
    DIRECTION INPUT ;
    USE SIGNAL ;
    PORT
      LAYER M5 ;
        RECT  9.168 94.848 9.192 95.04 ;
    END
  END i_d[28]
  PIN i_d[290]
    DIRECTION INPUT ;
    USE SIGNAL ;
    PORT
      LAYER M5 ;
        RECT  53.232 94.848 53.256 95.04 ;
    END
  END i_d[290]
  PIN i_d[291]
    DIRECTION INPUT ;
    USE SIGNAL ;
    PORT
      LAYER M5 ;
        RECT  53.376 94.848 53.4 95.04 ;
    END
  END i_d[291]
  PIN i_d[292]
    DIRECTION INPUT ;
    USE SIGNAL ;
    PORT
      LAYER M5 ;
        RECT  53.52 94.848 53.544 95.04 ;
    END
  END i_d[292]
  PIN i_d[293]
    DIRECTION INPUT ;
    USE SIGNAL ;
    PORT
      LAYER M5 ;
        RECT  53.664 94.848 53.688 95.04 ;
    END
  END i_d[293]
  PIN i_d[294]
    DIRECTION INPUT ;
    USE SIGNAL ;
    PORT
      LAYER M5 ;
        RECT  53.808 94.848 53.832 95.04 ;
    END
  END i_d[294]
  PIN i_d[295]
    DIRECTION INPUT ;
    USE SIGNAL ;
    PORT
      LAYER M5 ;
        RECT  53.952 94.848 53.976 95.04 ;
    END
  END i_d[295]
  PIN i_d[296]
    DIRECTION INPUT ;
    USE SIGNAL ;
    PORT
      LAYER M5 ;
        RECT  54.768 94.848 54.792 95.04 ;
    END
  END i_d[296]
  PIN i_d[297]
    DIRECTION INPUT ;
    USE SIGNAL ;
    PORT
      LAYER M5 ;
        RECT  54.912 94.848 54.936 95.04 ;
    END
  END i_d[297]
  PIN i_d[298]
    DIRECTION INPUT ;
    USE SIGNAL ;
    PORT
      LAYER M5 ;
        RECT  55.056 94.848 55.08 95.04 ;
    END
  END i_d[298]
  PIN i_d[299]
    DIRECTION INPUT ;
    USE SIGNAL ;
    PORT
      LAYER M5 ;
        RECT  55.2 94.848 55.224 95.04 ;
    END
  END i_d[299]
  PIN i_d[29]
    DIRECTION INPUT ;
    USE SIGNAL ;
    PORT
      LAYER M5 ;
        RECT  9.312 94.848 9.336 95.04 ;
    END
  END i_d[29]
  PIN i_d[2]
    DIRECTION INPUT ;
    USE SIGNAL ;
    PORT
      LAYER M5 ;
        RECT  4.608 94.848 4.632 95.04 ;
    END
  END i_d[2]
  PIN i_d[300]
    DIRECTION INPUT ;
    USE SIGNAL ;
    PORT
      LAYER M5 ;
        RECT  55.344 94.848 55.368 95.04 ;
    END
  END i_d[300]
  PIN i_d[301]
    DIRECTION INPUT ;
    USE SIGNAL ;
    PORT
      LAYER M5 ;
        RECT  55.488 94.848 55.512 95.04 ;
    END
  END i_d[301]
  PIN i_d[302]
    DIRECTION INPUT ;
    USE SIGNAL ;
    PORT
      LAYER M5 ;
        RECT  55.632 94.848 55.656 95.04 ;
    END
  END i_d[302]
  PIN i_d[303]
    DIRECTION INPUT ;
    USE SIGNAL ;
    PORT
      LAYER M5 ;
        RECT  55.776 94.848 55.8 95.04 ;
    END
  END i_d[303]
  PIN i_d[304]
    DIRECTION INPUT ;
    USE SIGNAL ;
    PORT
      LAYER M5 ;
        RECT  55.92 94.848 55.944 95.04 ;
    END
  END i_d[304]
  PIN i_d[305]
    DIRECTION INPUT ;
    USE SIGNAL ;
    PORT
      LAYER M5 ;
        RECT  56.064 94.848 56.088 95.04 ;
    END
  END i_d[305]
  PIN i_d[306]
    DIRECTION INPUT ;
    USE SIGNAL ;
    PORT
      LAYER M5 ;
        RECT  56.208 94.848 56.232 95.04 ;
    END
  END i_d[306]
  PIN i_d[307]
    DIRECTION INPUT ;
    USE SIGNAL ;
    PORT
      LAYER M5 ;
        RECT  56.352 94.848 56.376 95.04 ;
    END
  END i_d[307]
  PIN i_d[308]
    DIRECTION INPUT ;
    USE SIGNAL ;
    PORT
      LAYER M5 ;
        RECT  56.496 94.848 56.52 95.04 ;
    END
  END i_d[308]
  PIN i_d[309]
    DIRECTION INPUT ;
    USE SIGNAL ;
    PORT
      LAYER M5 ;
        RECT  56.64 94.848 56.664 95.04 ;
    END
  END i_d[309]
  PIN i_d[30]
    DIRECTION INPUT ;
    USE SIGNAL ;
    PORT
      LAYER M5 ;
        RECT  9.456 94.848 9.48 95.04 ;
    END
  END i_d[30]
  PIN i_d[310]
    DIRECTION INPUT ;
    USE SIGNAL ;
    PORT
      LAYER M5 ;
        RECT  56.784 94.848 56.808 95.04 ;
    END
  END i_d[310]
  PIN i_d[311]
    DIRECTION INPUT ;
    USE SIGNAL ;
    PORT
      LAYER M5 ;
        RECT  56.928 94.848 56.952 95.04 ;
    END
  END i_d[311]
  PIN i_d[312]
    DIRECTION INPUT ;
    USE SIGNAL ;
    PORT
      LAYER M5 ;
        RECT  57.216 94.848 57.24 95.04 ;
    END
  END i_d[312]
  PIN i_d[313]
    DIRECTION INPUT ;
    USE SIGNAL ;
    PORT
      LAYER M5 ;
        RECT  57.36 94.848 57.384 95.04 ;
    END
  END i_d[313]
  PIN i_d[314]
    DIRECTION INPUT ;
    USE SIGNAL ;
    PORT
      LAYER M5 ;
        RECT  57.504 94.848 57.528 95.04 ;
    END
  END i_d[314]
  PIN i_d[315]
    DIRECTION INPUT ;
    USE SIGNAL ;
    PORT
      LAYER M5 ;
        RECT  57.648 94.848 57.672 95.04 ;
    END
  END i_d[315]
  PIN i_d[316]
    DIRECTION INPUT ;
    USE SIGNAL ;
    PORT
      LAYER M5 ;
        RECT  57.792 94.848 57.816 95.04 ;
    END
  END i_d[316]
  PIN i_d[317]
    DIRECTION INPUT ;
    USE SIGNAL ;
    PORT
      LAYER M5 ;
        RECT  57.936 94.848 57.96 95.04 ;
    END
  END i_d[317]
  PIN i_d[318]
    DIRECTION INPUT ;
    USE SIGNAL ;
    PORT
      LAYER M5 ;
        RECT  58.08 94.848 58.104 95.04 ;
    END
  END i_d[318]
  PIN i_d[319]
    DIRECTION INPUT ;
    USE SIGNAL ;
    PORT
      LAYER M5 ;
        RECT  58.224 94.848 58.248 95.04 ;
    END
  END i_d[319]
  PIN i_d[31]
    DIRECTION INPUT ;
    USE SIGNAL ;
    PORT
      LAYER M5 ;
        RECT  9.6 94.848 9.624 95.04 ;
    END
  END i_d[31]
  PIN i_d[320]
    DIRECTION INPUT ;
    USE SIGNAL ;
    PORT
      LAYER M5 ;
        RECT  58.368 94.848 58.392 95.04 ;
    END
  END i_d[320]
  PIN i_d[321]
    DIRECTION INPUT ;
    USE SIGNAL ;
    PORT
      LAYER M5 ;
        RECT  58.512 94.848 58.536 95.04 ;
    END
  END i_d[321]
  PIN i_d[322]
    DIRECTION INPUT ;
    USE SIGNAL ;
    PORT
      LAYER M5 ;
        RECT  58.656 94.848 58.68 95.04 ;
    END
  END i_d[322]
  PIN i_d[323]
    DIRECTION INPUT ;
    USE SIGNAL ;
    PORT
      LAYER M5 ;
        RECT  58.8 94.848 58.824 95.04 ;
    END
  END i_d[323]
  PIN i_d[324]
    DIRECTION INPUT ;
    USE SIGNAL ;
    PORT
      LAYER M5 ;
        RECT  58.944 94.848 58.968 95.04 ;
    END
  END i_d[324]
  PIN i_d[325]
    DIRECTION INPUT ;
    USE SIGNAL ;
    PORT
      LAYER M5 ;
        RECT  59.088 94.848 59.112 95.04 ;
    END
  END i_d[325]
  PIN i_d[326]
    DIRECTION INPUT ;
    USE SIGNAL ;
    PORT
      LAYER M5 ;
        RECT  59.232 94.848 59.256 95.04 ;
    END
  END i_d[326]
  PIN i_d[327]
    DIRECTION INPUT ;
    USE SIGNAL ;
    PORT
      LAYER M5 ;
        RECT  59.376 94.848 59.4 95.04 ;
    END
  END i_d[327]
  PIN i_d[328]
    DIRECTION INPUT ;
    USE SIGNAL ;
    PORT
      LAYER M5 ;
        RECT  60.144 94.848 60.168 95.04 ;
    END
  END i_d[328]
  PIN i_d[329]
    DIRECTION INPUT ;
    USE SIGNAL ;
    PORT
      LAYER M5 ;
        RECT  60.288 94.848 60.312 95.04 ;
    END
  END i_d[329]
  PIN i_d[32]
    DIRECTION INPUT ;
    USE SIGNAL ;
    PORT
      LAYER M5 ;
        RECT  9.744 94.848 9.768 95.04 ;
    END
  END i_d[32]
  PIN i_d[330]
    DIRECTION INPUT ;
    USE SIGNAL ;
    PORT
      LAYER M5 ;
        RECT  60.432 94.848 60.456 95.04 ;
    END
  END i_d[330]
  PIN i_d[331]
    DIRECTION INPUT ;
    USE SIGNAL ;
    PORT
      LAYER M5 ;
        RECT  60.576 94.848 60.6 95.04 ;
    END
  END i_d[331]
  PIN i_d[332]
    DIRECTION INPUT ;
    USE SIGNAL ;
    PORT
      LAYER M5 ;
        RECT  60.72 94.848 60.744 95.04 ;
    END
  END i_d[332]
  PIN i_d[333]
    DIRECTION INPUT ;
    USE SIGNAL ;
    PORT
      LAYER M5 ;
        RECT  60.864 94.848 60.888 95.04 ;
    END
  END i_d[333]
  PIN i_d[334]
    DIRECTION INPUT ;
    USE SIGNAL ;
    PORT
      LAYER M5 ;
        RECT  61.008 94.848 61.032 95.04 ;
    END
  END i_d[334]
  PIN i_d[335]
    DIRECTION INPUT ;
    USE SIGNAL ;
    PORT
      LAYER M5 ;
        RECT  61.152 94.848 61.176 95.04 ;
    END
  END i_d[335]
  PIN i_d[336]
    DIRECTION INPUT ;
    USE SIGNAL ;
    PORT
      LAYER M5 ;
        RECT  61.296 94.848 61.32 95.04 ;
    END
  END i_d[336]
  PIN i_d[337]
    DIRECTION INPUT ;
    USE SIGNAL ;
    PORT
      LAYER M5 ;
        RECT  61.44 94.848 61.464 95.04 ;
    END
  END i_d[337]
  PIN i_d[338]
    DIRECTION INPUT ;
    USE SIGNAL ;
    PORT
      LAYER M5 ;
        RECT  61.584 94.848 61.608 95.04 ;
    END
  END i_d[338]
  PIN i_d[339]
    DIRECTION INPUT ;
    USE SIGNAL ;
    PORT
      LAYER M5 ;
        RECT  61.728 94.848 61.752 95.04 ;
    END
  END i_d[339]
  PIN i_d[33]
    DIRECTION INPUT ;
    USE SIGNAL ;
    PORT
      LAYER M5 ;
        RECT  9.888 94.848 9.912 95.04 ;
    END
  END i_d[33]
  PIN i_d[340]
    DIRECTION INPUT ;
    USE SIGNAL ;
    PORT
      LAYER M5 ;
        RECT  61.872 94.848 61.896 95.04 ;
    END
  END i_d[340]
  PIN i_d[341]
    DIRECTION INPUT ;
    USE SIGNAL ;
    PORT
      LAYER M5 ;
        RECT  62.016 94.848 62.04 95.04 ;
    END
  END i_d[341]
  PIN i_d[342]
    DIRECTION INPUT ;
    USE SIGNAL ;
    PORT
      LAYER M5 ;
        RECT  62.16 94.848 62.184 95.04 ;
    END
  END i_d[342]
  PIN i_d[343]
    DIRECTION INPUT ;
    USE SIGNAL ;
    PORT
      LAYER M5 ;
        RECT  62.304 94.848 62.328 95.04 ;
    END
  END i_d[343]
  PIN i_d[344]
    DIRECTION INPUT ;
    USE SIGNAL ;
    PORT
      LAYER M5 ;
        RECT  62.592 94.848 62.616 95.04 ;
    END
  END i_d[344]
  PIN i_d[345]
    DIRECTION INPUT ;
    USE SIGNAL ;
    PORT
      LAYER M5 ;
        RECT  62.736 94.848 62.76 95.04 ;
    END
  END i_d[345]
  PIN i_d[346]
    DIRECTION INPUT ;
    USE SIGNAL ;
    PORT
      LAYER M5 ;
        RECT  62.88 94.848 62.904 95.04 ;
    END
  END i_d[346]
  PIN i_d[347]
    DIRECTION INPUT ;
    USE SIGNAL ;
    PORT
      LAYER M5 ;
        RECT  63.024 94.848 63.048 95.04 ;
    END
  END i_d[347]
  PIN i_d[348]
    DIRECTION INPUT ;
    USE SIGNAL ;
    PORT
      LAYER M5 ;
        RECT  63.168 94.848 63.192 95.04 ;
    END
  END i_d[348]
  PIN i_d[349]
    DIRECTION INPUT ;
    USE SIGNAL ;
    PORT
      LAYER M5 ;
        RECT  63.312 94.848 63.336 95.04 ;
    END
  END i_d[349]
  PIN i_d[34]
    DIRECTION INPUT ;
    USE SIGNAL ;
    PORT
      LAYER M5 ;
        RECT  10.032 94.848 10.056 95.04 ;
    END
  END i_d[34]
  PIN i_d[350]
    DIRECTION INPUT ;
    USE SIGNAL ;
    PORT
      LAYER M5 ;
        RECT  63.456 94.848 63.48 95.04 ;
    END
  END i_d[350]
  PIN i_d[351]
    DIRECTION INPUT ;
    USE SIGNAL ;
    PORT
      LAYER M5 ;
        RECT  63.6 94.848 63.624 95.04 ;
    END
  END i_d[351]
  PIN i_d[352]
    DIRECTION INPUT ;
    USE SIGNAL ;
    PORT
      LAYER M5 ;
        RECT  63.744 94.848 63.768 95.04 ;
    END
  END i_d[352]
  PIN i_d[353]
    DIRECTION INPUT ;
    USE SIGNAL ;
    PORT
      LAYER M5 ;
        RECT  63.888 94.848 63.912 95.04 ;
    END
  END i_d[353]
  PIN i_d[354]
    DIRECTION INPUT ;
    USE SIGNAL ;
    PORT
      LAYER M5 ;
        RECT  64.032 94.848 64.056 95.04 ;
    END
  END i_d[354]
  PIN i_d[355]
    DIRECTION INPUT ;
    USE SIGNAL ;
    PORT
      LAYER M5 ;
        RECT  64.176 94.848 64.2 95.04 ;
    END
  END i_d[355]
  PIN i_d[356]
    DIRECTION INPUT ;
    USE SIGNAL ;
    PORT
      LAYER M5 ;
        RECT  64.32 94.848 64.344 95.04 ;
    END
  END i_d[356]
  PIN i_d[357]
    DIRECTION INPUT ;
    USE SIGNAL ;
    PORT
      LAYER M5 ;
        RECT  64.464 94.848 64.488 95.04 ;
    END
  END i_d[357]
  PIN i_d[358]
    DIRECTION INPUT ;
    USE SIGNAL ;
    PORT
      LAYER M5 ;
        RECT  64.608 94.848 64.632 95.04 ;
    END
  END i_d[358]
  PIN i_d[359]
    DIRECTION INPUT ;
    USE SIGNAL ;
    PORT
      LAYER M5 ;
        RECT  64.752 94.848 64.776 95.04 ;
    END
  END i_d[359]
  PIN i_d[35]
    DIRECTION INPUT ;
    USE SIGNAL ;
    PORT
      LAYER M5 ;
        RECT  10.176 94.848 10.2 95.04 ;
    END
  END i_d[35]
  PIN i_d[360]
    DIRECTION INPUT ;
    USE SIGNAL ;
    PORT
      LAYER M5 ;
        RECT  65.568 94.848 65.592 95.04 ;
    END
  END i_d[360]
  PIN i_d[361]
    DIRECTION INPUT ;
    USE SIGNAL ;
    PORT
      LAYER M5 ;
        RECT  65.712 94.848 65.736 95.04 ;
    END
  END i_d[361]
  PIN i_d[362]
    DIRECTION INPUT ;
    USE SIGNAL ;
    PORT
      LAYER M5 ;
        RECT  65.856 94.848 65.88 95.04 ;
    END
  END i_d[362]
  PIN i_d[363]
    DIRECTION INPUT ;
    USE SIGNAL ;
    PORT
      LAYER M5 ;
        RECT  66 94.848 66.024 95.04 ;
    END
  END i_d[363]
  PIN i_d[364]
    DIRECTION INPUT ;
    USE SIGNAL ;
    PORT
      LAYER M5 ;
        RECT  66.144 94.848 66.168 95.04 ;
    END
  END i_d[364]
  PIN i_d[365]
    DIRECTION INPUT ;
    USE SIGNAL ;
    PORT
      LAYER M5 ;
        RECT  66.288 94.848 66.312 95.04 ;
    END
  END i_d[365]
  PIN i_d[366]
    DIRECTION INPUT ;
    USE SIGNAL ;
    PORT
      LAYER M5 ;
        RECT  66.432 94.848 66.456 95.04 ;
    END
  END i_d[366]
  PIN i_d[367]
    DIRECTION INPUT ;
    USE SIGNAL ;
    PORT
      LAYER M5 ;
        RECT  66.576 94.848 66.6 95.04 ;
    END
  END i_d[367]
  PIN i_d[368]
    DIRECTION INPUT ;
    USE SIGNAL ;
    PORT
      LAYER M5 ;
        RECT  66.72 94.848 66.744 95.04 ;
    END
  END i_d[368]
  PIN i_d[369]
    DIRECTION INPUT ;
    USE SIGNAL ;
    PORT
      LAYER M5 ;
        RECT  66.864 94.848 66.888 95.04 ;
    END
  END i_d[369]
  PIN i_d[36]
    DIRECTION INPUT ;
    USE SIGNAL ;
    PORT
      LAYER M5 ;
        RECT  10.32 94.848 10.344 95.04 ;
    END
  END i_d[36]
  PIN i_d[370]
    DIRECTION INPUT ;
    USE SIGNAL ;
    PORT
      LAYER M5 ;
        RECT  67.008 94.848 67.032 95.04 ;
    END
  END i_d[370]
  PIN i_d[371]
    DIRECTION INPUT ;
    USE SIGNAL ;
    PORT
      LAYER M5 ;
        RECT  67.152 94.848 67.176 95.04 ;
    END
  END i_d[371]
  PIN i_d[372]
    DIRECTION INPUT ;
    USE SIGNAL ;
    PORT
      LAYER M5 ;
        RECT  67.296 94.848 67.32 95.04 ;
    END
  END i_d[372]
  PIN i_d[373]
    DIRECTION INPUT ;
    USE SIGNAL ;
    PORT
      LAYER M5 ;
        RECT  67.44 94.848 67.464 95.04 ;
    END
  END i_d[373]
  PIN i_d[374]
    DIRECTION INPUT ;
    USE SIGNAL ;
    PORT
      LAYER M5 ;
        RECT  67.584 94.848 67.608 95.04 ;
    END
  END i_d[374]
  PIN i_d[375]
    DIRECTION INPUT ;
    USE SIGNAL ;
    PORT
      LAYER M5 ;
        RECT  67.728 94.848 67.752 95.04 ;
    END
  END i_d[375]
  PIN i_d[376]
    DIRECTION INPUT ;
    USE SIGNAL ;
    PORT
      LAYER M5 ;
        RECT  68.016 94.848 68.04 95.04 ;
    END
  END i_d[376]
  PIN i_d[377]
    DIRECTION INPUT ;
    USE SIGNAL ;
    PORT
      LAYER M5 ;
        RECT  68.16 94.848 68.184 95.04 ;
    END
  END i_d[377]
  PIN i_d[378]
    DIRECTION INPUT ;
    USE SIGNAL ;
    PORT
      LAYER M5 ;
        RECT  68.304 94.848 68.328 95.04 ;
    END
  END i_d[378]
  PIN i_d[379]
    DIRECTION INPUT ;
    USE SIGNAL ;
    PORT
      LAYER M5 ;
        RECT  68.448 94.848 68.472 95.04 ;
    END
  END i_d[379]
  PIN i_d[37]
    DIRECTION INPUT ;
    USE SIGNAL ;
    PORT
      LAYER M5 ;
        RECT  10.464 94.848 10.488 95.04 ;
    END
  END i_d[37]
  PIN i_d[380]
    DIRECTION INPUT ;
    USE SIGNAL ;
    PORT
      LAYER M5 ;
        RECT  68.592 94.848 68.616 95.04 ;
    END
  END i_d[380]
  PIN i_d[381]
    DIRECTION INPUT ;
    USE SIGNAL ;
    PORT
      LAYER M5 ;
        RECT  68.736 94.848 68.76 95.04 ;
    END
  END i_d[381]
  PIN i_d[382]
    DIRECTION INPUT ;
    USE SIGNAL ;
    PORT
      LAYER M5 ;
        RECT  68.88 94.848 68.904 95.04 ;
    END
  END i_d[382]
  PIN i_d[383]
    DIRECTION INPUT ;
    USE SIGNAL ;
    PORT
      LAYER M5 ;
        RECT  69.024 94.848 69.048 95.04 ;
    END
  END i_d[383]
  PIN i_d[384]
    DIRECTION INPUT ;
    USE SIGNAL ;
    PORT
      LAYER M5 ;
        RECT  69.168 94.848 69.192 95.04 ;
    END
  END i_d[384]
  PIN i_d[385]
    DIRECTION INPUT ;
    USE SIGNAL ;
    PORT
      LAYER M5 ;
        RECT  69.312 94.848 69.336 95.04 ;
    END
  END i_d[385]
  PIN i_d[386]
    DIRECTION INPUT ;
    USE SIGNAL ;
    PORT
      LAYER M5 ;
        RECT  69.456 94.848 69.48 95.04 ;
    END
  END i_d[386]
  PIN i_d[387]
    DIRECTION INPUT ;
    USE SIGNAL ;
    PORT
      LAYER M5 ;
        RECT  69.6 94.848 69.624 95.04 ;
    END
  END i_d[387]
  PIN i_d[388]
    DIRECTION INPUT ;
    USE SIGNAL ;
    PORT
      LAYER M5 ;
        RECT  69.744 94.848 69.768 95.04 ;
    END
  END i_d[388]
  PIN i_d[389]
    DIRECTION INPUT ;
    USE SIGNAL ;
    PORT
      LAYER M5 ;
        RECT  69.888 94.848 69.912 95.04 ;
    END
  END i_d[389]
  PIN i_d[38]
    DIRECTION INPUT ;
    USE SIGNAL ;
    PORT
      LAYER M5 ;
        RECT  10.608 94.848 10.632 95.04 ;
    END
  END i_d[38]
  PIN i_d[390]
    DIRECTION INPUT ;
    USE SIGNAL ;
    PORT
      LAYER M5 ;
        RECT  70.032 94.848 70.056 95.04 ;
    END
  END i_d[390]
  PIN i_d[391]
    DIRECTION INPUT ;
    USE SIGNAL ;
    PORT
      LAYER M5 ;
        RECT  70.176 94.848 70.2 95.04 ;
    END
  END i_d[391]
  PIN i_d[392]
    DIRECTION INPUT ;
    USE SIGNAL ;
    PORT
      LAYER M5 ;
        RECT  70.944 94.848 70.968 95.04 ;
    END
  END i_d[392]
  PIN i_d[393]
    DIRECTION INPUT ;
    USE SIGNAL ;
    PORT
      LAYER M5 ;
        RECT  71.088 94.848 71.112 95.04 ;
    END
  END i_d[393]
  PIN i_d[394]
    DIRECTION INPUT ;
    USE SIGNAL ;
    PORT
      LAYER M5 ;
        RECT  71.232 94.848 71.256 95.04 ;
    END
  END i_d[394]
  PIN i_d[395]
    DIRECTION INPUT ;
    USE SIGNAL ;
    PORT
      LAYER M5 ;
        RECT  71.376 94.848 71.4 95.04 ;
    END
  END i_d[395]
  PIN i_d[396]
    DIRECTION INPUT ;
    USE SIGNAL ;
    PORT
      LAYER M5 ;
        RECT  71.52 94.848 71.544 95.04 ;
    END
  END i_d[396]
  PIN i_d[397]
    DIRECTION INPUT ;
    USE SIGNAL ;
    PORT
      LAYER M5 ;
        RECT  71.664 94.848 71.688 95.04 ;
    END
  END i_d[397]
  PIN i_d[398]
    DIRECTION INPUT ;
    USE SIGNAL ;
    PORT
      LAYER M5 ;
        RECT  71.808 94.848 71.832 95.04 ;
    END
  END i_d[398]
  PIN i_d[399]
    DIRECTION INPUT ;
    USE SIGNAL ;
    PORT
      LAYER M5 ;
        RECT  71.952 94.848 71.976 95.04 ;
    END
  END i_d[399]
  PIN i_d[39]
    DIRECTION INPUT ;
    USE SIGNAL ;
    PORT
      LAYER M5 ;
        RECT  10.752 94.848 10.776 95.04 ;
    END
  END i_d[39]
  PIN i_d[3]
    DIRECTION INPUT ;
    USE SIGNAL ;
    PORT
      LAYER M5 ;
        RECT  4.752 94.848 4.776 95.04 ;
    END
  END i_d[3]
  PIN i_d[400]
    DIRECTION INPUT ;
    USE SIGNAL ;
    PORT
      LAYER M5 ;
        RECT  72.096 94.848 72.12 95.04 ;
    END
  END i_d[400]
  PIN i_d[401]
    DIRECTION INPUT ;
    USE SIGNAL ;
    PORT
      LAYER M5 ;
        RECT  72.24 94.848 72.264 95.04 ;
    END
  END i_d[401]
  PIN i_d[402]
    DIRECTION INPUT ;
    USE SIGNAL ;
    PORT
      LAYER M5 ;
        RECT  72.384 94.848 72.408 95.04 ;
    END
  END i_d[402]
  PIN i_d[403]
    DIRECTION INPUT ;
    USE SIGNAL ;
    PORT
      LAYER M5 ;
        RECT  72.528 94.848 72.552 95.04 ;
    END
  END i_d[403]
  PIN i_d[404]
    DIRECTION INPUT ;
    USE SIGNAL ;
    PORT
      LAYER M5 ;
        RECT  72.672 94.848 72.696 95.04 ;
    END
  END i_d[404]
  PIN i_d[405]
    DIRECTION INPUT ;
    USE SIGNAL ;
    PORT
      LAYER M5 ;
        RECT  72.816 94.848 72.84 95.04 ;
    END
  END i_d[405]
  PIN i_d[406]
    DIRECTION INPUT ;
    USE SIGNAL ;
    PORT
      LAYER M5 ;
        RECT  72.96 94.848 72.984 95.04 ;
    END
  END i_d[406]
  PIN i_d[407]
    DIRECTION INPUT ;
    USE SIGNAL ;
    PORT
      LAYER M5 ;
        RECT  73.104 94.848 73.128 95.04 ;
    END
  END i_d[407]
  PIN i_d[408]
    DIRECTION INPUT ;
    USE SIGNAL ;
    PORT
      LAYER M5 ;
        RECT  73.392 94.848 73.416 95.04 ;
    END
  END i_d[408]
  PIN i_d[409]
    DIRECTION INPUT ;
    USE SIGNAL ;
    PORT
      LAYER M5 ;
        RECT  73.536 94.848 73.56 95.04 ;
    END
  END i_d[409]
  PIN i_d[40]
    DIRECTION INPUT ;
    USE SIGNAL ;
    PORT
      LAYER M5 ;
        RECT  11.568 94.848 11.592 95.04 ;
    END
  END i_d[40]
  PIN i_d[410]
    DIRECTION INPUT ;
    USE SIGNAL ;
    PORT
      LAYER M5 ;
        RECT  73.68 94.848 73.704 95.04 ;
    END
  END i_d[410]
  PIN i_d[411]
    DIRECTION INPUT ;
    USE SIGNAL ;
    PORT
      LAYER M5 ;
        RECT  73.824 94.848 73.848 95.04 ;
    END
  END i_d[411]
  PIN i_d[412]
    DIRECTION INPUT ;
    USE SIGNAL ;
    PORT
      LAYER M5 ;
        RECT  73.968 94.848 73.992 95.04 ;
    END
  END i_d[412]
  PIN i_d[413]
    DIRECTION INPUT ;
    USE SIGNAL ;
    PORT
      LAYER M5 ;
        RECT  74.112 94.848 74.136 95.04 ;
    END
  END i_d[413]
  PIN i_d[414]
    DIRECTION INPUT ;
    USE SIGNAL ;
    PORT
      LAYER M5 ;
        RECT  74.256 94.848 74.28 95.04 ;
    END
  END i_d[414]
  PIN i_d[415]
    DIRECTION INPUT ;
    USE SIGNAL ;
    PORT
      LAYER M5 ;
        RECT  74.4 94.848 74.424 95.04 ;
    END
  END i_d[415]
  PIN i_d[416]
    DIRECTION INPUT ;
    USE SIGNAL ;
    PORT
      LAYER M5 ;
        RECT  74.544 94.848 74.568 95.04 ;
    END
  END i_d[416]
  PIN i_d[417]
    DIRECTION INPUT ;
    USE SIGNAL ;
    PORT
      LAYER M5 ;
        RECT  74.688 94.848 74.712 95.04 ;
    END
  END i_d[417]
  PIN i_d[418]
    DIRECTION INPUT ;
    USE SIGNAL ;
    PORT
      LAYER M5 ;
        RECT  74.832 94.848 74.856 95.04 ;
    END
  END i_d[418]
  PIN i_d[419]
    DIRECTION INPUT ;
    USE SIGNAL ;
    PORT
      LAYER M5 ;
        RECT  74.976 94.848 75 95.04 ;
    END
  END i_d[419]
  PIN i_d[41]
    DIRECTION INPUT ;
    USE SIGNAL ;
    PORT
      LAYER M5 ;
        RECT  11.712 94.848 11.736 95.04 ;
    END
  END i_d[41]
  PIN i_d[420]
    DIRECTION INPUT ;
    USE SIGNAL ;
    PORT
      LAYER M5 ;
        RECT  75.12 94.848 75.144 95.04 ;
    END
  END i_d[420]
  PIN i_d[421]
    DIRECTION INPUT ;
    USE SIGNAL ;
    PORT
      LAYER M5 ;
        RECT  75.264 94.848 75.288 95.04 ;
    END
  END i_d[421]
  PIN i_d[422]
    DIRECTION INPUT ;
    USE SIGNAL ;
    PORT
      LAYER M5 ;
        RECT  75.408 94.848 75.432 95.04 ;
    END
  END i_d[422]
  PIN i_d[423]
    DIRECTION INPUT ;
    USE SIGNAL ;
    PORT
      LAYER M5 ;
        RECT  75.552 94.848 75.576 95.04 ;
    END
  END i_d[423]
  PIN i_d[424]
    DIRECTION INPUT ;
    USE SIGNAL ;
    PORT
      LAYER M5 ;
        RECT  76.368 94.848 76.392 95.04 ;
    END
  END i_d[424]
  PIN i_d[425]
    DIRECTION INPUT ;
    USE SIGNAL ;
    PORT
      LAYER M5 ;
        RECT  76.512 94.848 76.536 95.04 ;
    END
  END i_d[425]
  PIN i_d[426]
    DIRECTION INPUT ;
    USE SIGNAL ;
    PORT
      LAYER M5 ;
        RECT  76.656 94.848 76.68 95.04 ;
    END
  END i_d[426]
  PIN i_d[427]
    DIRECTION INPUT ;
    USE SIGNAL ;
    PORT
      LAYER M5 ;
        RECT  76.8 94.848 76.824 95.04 ;
    END
  END i_d[427]
  PIN i_d[428]
    DIRECTION INPUT ;
    USE SIGNAL ;
    PORT
      LAYER M5 ;
        RECT  76.944 94.848 76.968 95.04 ;
    END
  END i_d[428]
  PIN i_d[429]
    DIRECTION INPUT ;
    USE SIGNAL ;
    PORT
      LAYER M5 ;
        RECT  77.088 94.848 77.112 95.04 ;
    END
  END i_d[429]
  PIN i_d[42]
    DIRECTION INPUT ;
    USE SIGNAL ;
    PORT
      LAYER M5 ;
        RECT  11.856 94.848 11.88 95.04 ;
    END
  END i_d[42]
  PIN i_d[430]
    DIRECTION INPUT ;
    USE SIGNAL ;
    PORT
      LAYER M5 ;
        RECT  77.232 94.848 77.256 95.04 ;
    END
  END i_d[430]
  PIN i_d[431]
    DIRECTION INPUT ;
    USE SIGNAL ;
    PORT
      LAYER M5 ;
        RECT  77.376 94.848 77.4 95.04 ;
    END
  END i_d[431]
  PIN i_d[432]
    DIRECTION INPUT ;
    USE SIGNAL ;
    PORT
      LAYER M5 ;
        RECT  77.52 94.848 77.544 95.04 ;
    END
  END i_d[432]
  PIN i_d[433]
    DIRECTION INPUT ;
    USE SIGNAL ;
    PORT
      LAYER M5 ;
        RECT  77.664 94.848 77.688 95.04 ;
    END
  END i_d[433]
  PIN i_d[434]
    DIRECTION INPUT ;
    USE SIGNAL ;
    PORT
      LAYER M5 ;
        RECT  77.808 94.848 77.832 95.04 ;
    END
  END i_d[434]
  PIN i_d[435]
    DIRECTION INPUT ;
    USE SIGNAL ;
    PORT
      LAYER M5 ;
        RECT  77.952 94.848 77.976 95.04 ;
    END
  END i_d[435]
  PIN i_d[436]
    DIRECTION INPUT ;
    USE SIGNAL ;
    PORT
      LAYER M5 ;
        RECT  78.096 94.848 78.12 95.04 ;
    END
  END i_d[436]
  PIN i_d[437]
    DIRECTION INPUT ;
    USE SIGNAL ;
    PORT
      LAYER M5 ;
        RECT  78.24 94.848 78.264 95.04 ;
    END
  END i_d[437]
  PIN i_d[438]
    DIRECTION INPUT ;
    USE SIGNAL ;
    PORT
      LAYER M5 ;
        RECT  78.384 94.848 78.408 95.04 ;
    END
  END i_d[438]
  PIN i_d[439]
    DIRECTION INPUT ;
    USE SIGNAL ;
    PORT
      LAYER M5 ;
        RECT  78.528 94.848 78.552 95.04 ;
    END
  END i_d[439]
  PIN i_d[43]
    DIRECTION INPUT ;
    USE SIGNAL ;
    PORT
      LAYER M5 ;
        RECT  12 94.848 12.024 95.04 ;
    END
  END i_d[43]
  PIN i_d[440]
    DIRECTION INPUT ;
    USE SIGNAL ;
    PORT
      LAYER M5 ;
        RECT  78.816 94.848 78.84 95.04 ;
    END
  END i_d[440]
  PIN i_d[441]
    DIRECTION INPUT ;
    USE SIGNAL ;
    PORT
      LAYER M5 ;
        RECT  78.96 94.848 78.984 95.04 ;
    END
  END i_d[441]
  PIN i_d[442]
    DIRECTION INPUT ;
    USE SIGNAL ;
    PORT
      LAYER M5 ;
        RECT  79.104 94.848 79.128 95.04 ;
    END
  END i_d[442]
  PIN i_d[443]
    DIRECTION INPUT ;
    USE SIGNAL ;
    PORT
      LAYER M5 ;
        RECT  79.248 94.848 79.272 95.04 ;
    END
  END i_d[443]
  PIN i_d[444]
    DIRECTION INPUT ;
    USE SIGNAL ;
    PORT
      LAYER M5 ;
        RECT  79.392 94.848 79.416 95.04 ;
    END
  END i_d[444]
  PIN i_d[445]
    DIRECTION INPUT ;
    USE SIGNAL ;
    PORT
      LAYER M5 ;
        RECT  79.536 94.848 79.56 95.04 ;
    END
  END i_d[445]
  PIN i_d[446]
    DIRECTION INPUT ;
    USE SIGNAL ;
    PORT
      LAYER M5 ;
        RECT  79.68 94.848 79.704 95.04 ;
    END
  END i_d[446]
  PIN i_d[447]
    DIRECTION INPUT ;
    USE SIGNAL ;
    PORT
      LAYER M5 ;
        RECT  79.824 94.848 79.848 95.04 ;
    END
  END i_d[447]
  PIN i_d[448]
    DIRECTION INPUT ;
    USE SIGNAL ;
    PORT
      LAYER M5 ;
        RECT  79.968 94.848 79.992 95.04 ;
    END
  END i_d[448]
  PIN i_d[449]
    DIRECTION INPUT ;
    USE SIGNAL ;
    PORT
      LAYER M5 ;
        RECT  80.112 94.848 80.136 95.04 ;
    END
  END i_d[449]
  PIN i_d[44]
    DIRECTION INPUT ;
    USE SIGNAL ;
    PORT
      LAYER M5 ;
        RECT  12.144 94.848 12.168 95.04 ;
    END
  END i_d[44]
  PIN i_d[450]
    DIRECTION INPUT ;
    USE SIGNAL ;
    PORT
      LAYER M5 ;
        RECT  80.256 94.848 80.28 95.04 ;
    END
  END i_d[450]
  PIN i_d[451]
    DIRECTION INPUT ;
    USE SIGNAL ;
    PORT
      LAYER M5 ;
        RECT  80.4 94.848 80.424 95.04 ;
    END
  END i_d[451]
  PIN i_d[452]
    DIRECTION INPUT ;
    USE SIGNAL ;
    PORT
      LAYER M5 ;
        RECT  80.544 94.848 80.568 95.04 ;
    END
  END i_d[452]
  PIN i_d[453]
    DIRECTION INPUT ;
    USE SIGNAL ;
    PORT
      LAYER M5 ;
        RECT  80.688 94.848 80.712 95.04 ;
    END
  END i_d[453]
  PIN i_d[454]
    DIRECTION INPUT ;
    USE SIGNAL ;
    PORT
      LAYER M5 ;
        RECT  80.832 94.848 80.856 95.04 ;
    END
  END i_d[454]
  PIN i_d[455]
    DIRECTION INPUT ;
    USE SIGNAL ;
    PORT
      LAYER M5 ;
        RECT  80.976 94.848 81 95.04 ;
    END
  END i_d[455]
  PIN i_d[456]
    DIRECTION INPUT ;
    USE SIGNAL ;
    PORT
      LAYER M5 ;
        RECT  81.744 94.848 81.768 95.04 ;
    END
  END i_d[456]
  PIN i_d[457]
    DIRECTION INPUT ;
    USE SIGNAL ;
    PORT
      LAYER M5 ;
        RECT  81.888 94.848 81.912 95.04 ;
    END
  END i_d[457]
  PIN i_d[458]
    DIRECTION INPUT ;
    USE SIGNAL ;
    PORT
      LAYER M5 ;
        RECT  82.032 94.848 82.056 95.04 ;
    END
  END i_d[458]
  PIN i_d[459]
    DIRECTION INPUT ;
    USE SIGNAL ;
    PORT
      LAYER M5 ;
        RECT  82.176 94.848 82.2 95.04 ;
    END
  END i_d[459]
  PIN i_d[45]
    DIRECTION INPUT ;
    USE SIGNAL ;
    PORT
      LAYER M5 ;
        RECT  12.288 94.848 12.312 95.04 ;
    END
  END i_d[45]
  PIN i_d[460]
    DIRECTION INPUT ;
    USE SIGNAL ;
    PORT
      LAYER M5 ;
        RECT  82.32 94.848 82.344 95.04 ;
    END
  END i_d[460]
  PIN i_d[461]
    DIRECTION INPUT ;
    USE SIGNAL ;
    PORT
      LAYER M5 ;
        RECT  82.464 94.848 82.488 95.04 ;
    END
  END i_d[461]
  PIN i_d[462]
    DIRECTION INPUT ;
    USE SIGNAL ;
    PORT
      LAYER M5 ;
        RECT  82.608 94.848 82.632 95.04 ;
    END
  END i_d[462]
  PIN i_d[463]
    DIRECTION INPUT ;
    USE SIGNAL ;
    PORT
      LAYER M5 ;
        RECT  82.752 94.848 82.776 95.04 ;
    END
  END i_d[463]
  PIN i_d[464]
    DIRECTION INPUT ;
    USE SIGNAL ;
    PORT
      LAYER M5 ;
        RECT  82.896 94.848 82.92 95.04 ;
    END
  END i_d[464]
  PIN i_d[465]
    DIRECTION INPUT ;
    USE SIGNAL ;
    PORT
      LAYER M5 ;
        RECT  83.04 94.848 83.064 95.04 ;
    END
  END i_d[465]
  PIN i_d[466]
    DIRECTION INPUT ;
    USE SIGNAL ;
    PORT
      LAYER M5 ;
        RECT  83.184 94.848 83.208 95.04 ;
    END
  END i_d[466]
  PIN i_d[467]
    DIRECTION INPUT ;
    USE SIGNAL ;
    PORT
      LAYER M5 ;
        RECT  83.328 94.848 83.352 95.04 ;
    END
  END i_d[467]
  PIN i_d[468]
    DIRECTION INPUT ;
    USE SIGNAL ;
    PORT
      LAYER M5 ;
        RECT  83.472 94.848 83.496 95.04 ;
    END
  END i_d[468]
  PIN i_d[469]
    DIRECTION INPUT ;
    USE SIGNAL ;
    PORT
      LAYER M5 ;
        RECT  83.616 94.848 83.64 95.04 ;
    END
  END i_d[469]
  PIN i_d[46]
    DIRECTION INPUT ;
    USE SIGNAL ;
    PORT
      LAYER M5 ;
        RECT  12.432 94.848 12.456 95.04 ;
    END
  END i_d[46]
  PIN i_d[470]
    DIRECTION INPUT ;
    USE SIGNAL ;
    PORT
      LAYER M5 ;
        RECT  83.76 94.848 83.784 95.04 ;
    END
  END i_d[470]
  PIN i_d[471]
    DIRECTION INPUT ;
    USE SIGNAL ;
    PORT
      LAYER M5 ;
        RECT  83.904 94.848 83.928 95.04 ;
    END
  END i_d[471]
  PIN i_d[472]
    DIRECTION INPUT ;
    USE SIGNAL ;
    PORT
      LAYER M5 ;
        RECT  84.192 94.848 84.216 95.04 ;
    END
  END i_d[472]
  PIN i_d[473]
    DIRECTION INPUT ;
    USE SIGNAL ;
    PORT
      LAYER M5 ;
        RECT  84.336 94.848 84.36 95.04 ;
    END
  END i_d[473]
  PIN i_d[474]
    DIRECTION INPUT ;
    USE SIGNAL ;
    PORT
      LAYER M5 ;
        RECT  84.48 94.848 84.504 95.04 ;
    END
  END i_d[474]
  PIN i_d[475]
    DIRECTION INPUT ;
    USE SIGNAL ;
    PORT
      LAYER M5 ;
        RECT  84.624 94.848 84.648 95.04 ;
    END
  END i_d[475]
  PIN i_d[476]
    DIRECTION INPUT ;
    USE SIGNAL ;
    PORT
      LAYER M5 ;
        RECT  84.768 94.848 84.792 95.04 ;
    END
  END i_d[476]
  PIN i_d[477]
    DIRECTION INPUT ;
    USE SIGNAL ;
    PORT
      LAYER M5 ;
        RECT  84.912 94.848 84.936 95.04 ;
    END
  END i_d[477]
  PIN i_d[478]
    DIRECTION INPUT ;
    USE SIGNAL ;
    PORT
      LAYER M5 ;
        RECT  85.056 94.848 85.08 95.04 ;
    END
  END i_d[478]
  PIN i_d[479]
    DIRECTION INPUT ;
    USE SIGNAL ;
    PORT
      LAYER M5 ;
        RECT  85.2 94.848 85.224 95.04 ;
    END
  END i_d[479]
  PIN i_d[47]
    DIRECTION INPUT ;
    USE SIGNAL ;
    PORT
      LAYER M5 ;
        RECT  12.576 94.848 12.6 95.04 ;
    END
  END i_d[47]
  PIN i_d[480]
    DIRECTION INPUT ;
    USE SIGNAL ;
    PORT
      LAYER M5 ;
        RECT  85.344 94.848 85.368 95.04 ;
    END
  END i_d[480]
  PIN i_d[481]
    DIRECTION INPUT ;
    USE SIGNAL ;
    PORT
      LAYER M5 ;
        RECT  85.488 94.848 85.512 95.04 ;
    END
  END i_d[481]
  PIN i_d[482]
    DIRECTION INPUT ;
    USE SIGNAL ;
    PORT
      LAYER M5 ;
        RECT  85.632 94.848 85.656 95.04 ;
    END
  END i_d[482]
  PIN i_d[483]
    DIRECTION INPUT ;
    USE SIGNAL ;
    PORT
      LAYER M5 ;
        RECT  85.776 94.848 85.8 95.04 ;
    END
  END i_d[483]
  PIN i_d[484]
    DIRECTION INPUT ;
    USE SIGNAL ;
    PORT
      LAYER M5 ;
        RECT  85.92 94.848 85.944 95.04 ;
    END
  END i_d[484]
  PIN i_d[485]
    DIRECTION INPUT ;
    USE SIGNAL ;
    PORT
      LAYER M5 ;
        RECT  86.064 94.848 86.088 95.04 ;
    END
  END i_d[485]
  PIN i_d[486]
    DIRECTION INPUT ;
    USE SIGNAL ;
    PORT
      LAYER M5 ;
        RECT  86.208 94.848 86.232 95.04 ;
    END
  END i_d[486]
  PIN i_d[487]
    DIRECTION INPUT ;
    USE SIGNAL ;
    PORT
      LAYER M5 ;
        RECT  86.352 94.848 86.376 95.04 ;
    END
  END i_d[487]
  PIN i_d[488]
    DIRECTION INPUT ;
    USE SIGNAL ;
    PORT
      LAYER M5 ;
        RECT  87.168 94.848 87.192 95.04 ;
    END
  END i_d[488]
  PIN i_d[489]
    DIRECTION INPUT ;
    USE SIGNAL ;
    PORT
      LAYER M5 ;
        RECT  87.312 94.848 87.336 95.04 ;
    END
  END i_d[489]
  PIN i_d[48]
    DIRECTION INPUT ;
    USE SIGNAL ;
    PORT
      LAYER M5 ;
        RECT  12.72 94.848 12.744 95.04 ;
    END
  END i_d[48]
  PIN i_d[490]
    DIRECTION INPUT ;
    USE SIGNAL ;
    PORT
      LAYER M5 ;
        RECT  87.456 94.848 87.48 95.04 ;
    END
  END i_d[490]
  PIN i_d[491]
    DIRECTION INPUT ;
    USE SIGNAL ;
    PORT
      LAYER M5 ;
        RECT  87.6 94.848 87.624 95.04 ;
    END
  END i_d[491]
  PIN i_d[492]
    DIRECTION INPUT ;
    USE SIGNAL ;
    PORT
      LAYER M5 ;
        RECT  87.744 94.848 87.768 95.04 ;
    END
  END i_d[492]
  PIN i_d[493]
    DIRECTION INPUT ;
    USE SIGNAL ;
    PORT
      LAYER M5 ;
        RECT  87.888 94.848 87.912 95.04 ;
    END
  END i_d[493]
  PIN i_d[494]
    DIRECTION INPUT ;
    USE SIGNAL ;
    PORT
      LAYER M5 ;
        RECT  88.032 94.848 88.056 95.04 ;
    END
  END i_d[494]
  PIN i_d[495]
    DIRECTION INPUT ;
    USE SIGNAL ;
    PORT
      LAYER M5 ;
        RECT  88.176 94.848 88.2 95.04 ;
    END
  END i_d[495]
  PIN i_d[496]
    DIRECTION INPUT ;
    USE SIGNAL ;
    PORT
      LAYER M5 ;
        RECT  88.32 94.848 88.344 95.04 ;
    END
  END i_d[496]
  PIN i_d[497]
    DIRECTION INPUT ;
    USE SIGNAL ;
    PORT
      LAYER M5 ;
        RECT  88.464 94.848 88.488 95.04 ;
    END
  END i_d[497]
  PIN i_d[498]
    DIRECTION INPUT ;
    USE SIGNAL ;
    PORT
      LAYER M5 ;
        RECT  88.608 94.848 88.632 95.04 ;
    END
  END i_d[498]
  PIN i_d[499]
    DIRECTION INPUT ;
    USE SIGNAL ;
    PORT
      LAYER M5 ;
        RECT  88.752 94.848 88.776 95.04 ;
    END
  END i_d[499]
  PIN i_d[49]
    DIRECTION INPUT ;
    USE SIGNAL ;
    PORT
      LAYER M5 ;
        RECT  12.864 94.848 12.888 95.04 ;
    END
  END i_d[49]
  PIN i_d[4]
    DIRECTION INPUT ;
    USE SIGNAL ;
    PORT
      LAYER M5 ;
        RECT  4.896 94.848 4.92 95.04 ;
    END
  END i_d[4]
  PIN i_d[500]
    DIRECTION INPUT ;
    USE SIGNAL ;
    PORT
      LAYER M5 ;
        RECT  88.896 94.848 88.92 95.04 ;
    END
  END i_d[500]
  PIN i_d[501]
    DIRECTION INPUT ;
    USE SIGNAL ;
    PORT
      LAYER M5 ;
        RECT  89.04 94.848 89.064 95.04 ;
    END
  END i_d[501]
  PIN i_d[502]
    DIRECTION INPUT ;
    USE SIGNAL ;
    PORT
      LAYER M5 ;
        RECT  89.184 94.848 89.208 95.04 ;
    END
  END i_d[502]
  PIN i_d[503]
    DIRECTION INPUT ;
    USE SIGNAL ;
    PORT
      LAYER M5 ;
        RECT  89.328 94.848 89.352 95.04 ;
    END
  END i_d[503]
  PIN i_d[504]
    DIRECTION INPUT ;
    USE SIGNAL ;
    PORT
      LAYER M5 ;
        RECT  89.616 94.848 89.64 95.04 ;
    END
  END i_d[504]
  PIN i_d[505]
    DIRECTION INPUT ;
    USE SIGNAL ;
    PORT
      LAYER M5 ;
        RECT  89.76 94.848 89.784 95.04 ;
    END
  END i_d[505]
  PIN i_d[506]
    DIRECTION INPUT ;
    USE SIGNAL ;
    PORT
      LAYER M5 ;
        RECT  89.904 94.848 89.928 95.04 ;
    END
  END i_d[506]
  PIN i_d[507]
    DIRECTION INPUT ;
    USE SIGNAL ;
    PORT
      LAYER M5 ;
        RECT  90.048 94.848 90.072 95.04 ;
    END
  END i_d[507]
  PIN i_d[508]
    DIRECTION INPUT ;
    USE SIGNAL ;
    PORT
      LAYER M5 ;
        RECT  90.192 94.848 90.216 95.04 ;
    END
  END i_d[508]
  PIN i_d[509]
    DIRECTION INPUT ;
    USE SIGNAL ;
    PORT
      LAYER M5 ;
        RECT  90.336 94.848 90.36 95.04 ;
    END
  END i_d[509]
  PIN i_d[50]
    DIRECTION INPUT ;
    USE SIGNAL ;
    PORT
      LAYER M5 ;
        RECT  13.008 94.848 13.032 95.04 ;
    END
  END i_d[50]
  PIN i_d[510]
    DIRECTION INPUT ;
    USE SIGNAL ;
    PORT
      LAYER M5 ;
        RECT  90.48 94.848 90.504 95.04 ;
    END
  END i_d[510]
  PIN i_d[511]
    DIRECTION INPUT ;
    USE SIGNAL ;
    PORT
      LAYER M5 ;
        RECT  90.624 94.848 90.648 95.04 ;
    END
  END i_d[511]
  PIN i_d[51]
    DIRECTION INPUT ;
    USE SIGNAL ;
    PORT
      LAYER M5 ;
        RECT  13.152 94.848 13.176 95.04 ;
    END
  END i_d[51]
  PIN i_d[52]
    DIRECTION INPUT ;
    USE SIGNAL ;
    PORT
      LAYER M5 ;
        RECT  13.296 94.848 13.32 95.04 ;
    END
  END i_d[52]
  PIN i_d[53]
    DIRECTION INPUT ;
    USE SIGNAL ;
    PORT
      LAYER M5 ;
        RECT  13.44 94.848 13.464 95.04 ;
    END
  END i_d[53]
  PIN i_d[54]
    DIRECTION INPUT ;
    USE SIGNAL ;
    PORT
      LAYER M5 ;
        RECT  13.584 94.848 13.608 95.04 ;
    END
  END i_d[54]
  PIN i_d[55]
    DIRECTION INPUT ;
    USE SIGNAL ;
    PORT
      LAYER M5 ;
        RECT  13.728 94.848 13.752 95.04 ;
    END
  END i_d[55]
  PIN i_d[56]
    DIRECTION INPUT ;
    USE SIGNAL ;
    PORT
      LAYER M5 ;
        RECT  14.016 94.848 14.04 95.04 ;
    END
  END i_d[56]
  PIN i_d[57]
    DIRECTION INPUT ;
    USE SIGNAL ;
    PORT
      LAYER M5 ;
        RECT  14.16 94.848 14.184 95.04 ;
    END
  END i_d[57]
  PIN i_d[58]
    DIRECTION INPUT ;
    USE SIGNAL ;
    PORT
      LAYER M5 ;
        RECT  14.304 94.848 14.328 95.04 ;
    END
  END i_d[58]
  PIN i_d[59]
    DIRECTION INPUT ;
    USE SIGNAL ;
    PORT
      LAYER M5 ;
        RECT  14.448 94.848 14.472 95.04 ;
    END
  END i_d[59]
  PIN i_d[5]
    DIRECTION INPUT ;
    USE SIGNAL ;
    PORT
      LAYER M5 ;
        RECT  5.04 94.848 5.064 95.04 ;
    END
  END i_d[5]
  PIN i_d[60]
    DIRECTION INPUT ;
    USE SIGNAL ;
    PORT
      LAYER M5 ;
        RECT  14.592 94.848 14.616 95.04 ;
    END
  END i_d[60]
  PIN i_d[61]
    DIRECTION INPUT ;
    USE SIGNAL ;
    PORT
      LAYER M5 ;
        RECT  14.736 94.848 14.76 95.04 ;
    END
  END i_d[61]
  PIN i_d[62]
    DIRECTION INPUT ;
    USE SIGNAL ;
    PORT
      LAYER M5 ;
        RECT  14.88 94.848 14.904 95.04 ;
    END
  END i_d[62]
  PIN i_d[63]
    DIRECTION INPUT ;
    USE SIGNAL ;
    PORT
      LAYER M5 ;
        RECT  15.024 94.848 15.048 95.04 ;
    END
  END i_d[63]
  PIN i_d[64]
    DIRECTION INPUT ;
    USE SIGNAL ;
    PORT
      LAYER M5 ;
        RECT  15.168 94.848 15.192 95.04 ;
    END
  END i_d[64]
  PIN i_d[65]
    DIRECTION INPUT ;
    USE SIGNAL ;
    PORT
      LAYER M5 ;
        RECT  15.312 94.848 15.336 95.04 ;
    END
  END i_d[65]
  PIN i_d[66]
    DIRECTION INPUT ;
    USE SIGNAL ;
    PORT
      LAYER M5 ;
        RECT  15.456 94.848 15.48 95.04 ;
    END
  END i_d[66]
  PIN i_d[67]
    DIRECTION INPUT ;
    USE SIGNAL ;
    PORT
      LAYER M5 ;
        RECT  15.6 94.848 15.624 95.04 ;
    END
  END i_d[67]
  PIN i_d[68]
    DIRECTION INPUT ;
    USE SIGNAL ;
    PORT
      LAYER M5 ;
        RECT  15.744 94.848 15.768 95.04 ;
    END
  END i_d[68]
  PIN i_d[69]
    DIRECTION INPUT ;
    USE SIGNAL ;
    PORT
      LAYER M5 ;
        RECT  15.888 94.848 15.912 95.04 ;
    END
  END i_d[69]
  PIN i_d[6]
    DIRECTION INPUT ;
    USE SIGNAL ;
    PORT
      LAYER M5 ;
        RECT  5.184 94.848 5.208 95.04 ;
    END
  END i_d[6]
  PIN i_d[70]
    DIRECTION INPUT ;
    USE SIGNAL ;
    PORT
      LAYER M5 ;
        RECT  16.032 94.848 16.056 95.04 ;
    END
  END i_d[70]
  PIN i_d[71]
    DIRECTION INPUT ;
    USE SIGNAL ;
    PORT
      LAYER M5 ;
        RECT  16.176 94.848 16.2 95.04 ;
    END
  END i_d[71]
  PIN i_d[72]
    DIRECTION INPUT ;
    USE SIGNAL ;
    PORT
      LAYER M5 ;
        RECT  16.944 94.848 16.968 95.04 ;
    END
  END i_d[72]
  PIN i_d[73]
    DIRECTION INPUT ;
    USE SIGNAL ;
    PORT
      LAYER M5 ;
        RECT  17.088 94.848 17.112 95.04 ;
    END
  END i_d[73]
  PIN i_d[74]
    DIRECTION INPUT ;
    USE SIGNAL ;
    PORT
      LAYER M5 ;
        RECT  17.232 94.848 17.256 95.04 ;
    END
  END i_d[74]
  PIN i_d[75]
    DIRECTION INPUT ;
    USE SIGNAL ;
    PORT
      LAYER M5 ;
        RECT  17.376 94.848 17.4 95.04 ;
    END
  END i_d[75]
  PIN i_d[76]
    DIRECTION INPUT ;
    USE SIGNAL ;
    PORT
      LAYER M5 ;
        RECT  17.52 94.848 17.544 95.04 ;
    END
  END i_d[76]
  PIN i_d[77]
    DIRECTION INPUT ;
    USE SIGNAL ;
    PORT
      LAYER M5 ;
        RECT  17.664 94.848 17.688 95.04 ;
    END
  END i_d[77]
  PIN i_d[78]
    DIRECTION INPUT ;
    USE SIGNAL ;
    PORT
      LAYER M5 ;
        RECT  17.808 94.848 17.832 95.04 ;
    END
  END i_d[78]
  PIN i_d[79]
    DIRECTION INPUT ;
    USE SIGNAL ;
    PORT
      LAYER M5 ;
        RECT  17.952 94.848 17.976 95.04 ;
    END
  END i_d[79]
  PIN i_d[7]
    DIRECTION INPUT ;
    USE SIGNAL ;
    PORT
      LAYER M5 ;
        RECT  5.328 94.848 5.352 95.04 ;
    END
  END i_d[7]
  PIN i_d[80]
    DIRECTION INPUT ;
    USE SIGNAL ;
    PORT
      LAYER M5 ;
        RECT  18.096 94.848 18.12 95.04 ;
    END
  END i_d[80]
  PIN i_d[81]
    DIRECTION INPUT ;
    USE SIGNAL ;
    PORT
      LAYER M5 ;
        RECT  18.24 94.848 18.264 95.04 ;
    END
  END i_d[81]
  PIN i_d[82]
    DIRECTION INPUT ;
    USE SIGNAL ;
    PORT
      LAYER M5 ;
        RECT  18.384 94.848 18.408 95.04 ;
    END
  END i_d[82]
  PIN i_d[83]
    DIRECTION INPUT ;
    USE SIGNAL ;
    PORT
      LAYER M5 ;
        RECT  18.528 94.848 18.552 95.04 ;
    END
  END i_d[83]
  PIN i_d[84]
    DIRECTION INPUT ;
    USE SIGNAL ;
    PORT
      LAYER M5 ;
        RECT  18.672 94.848 18.696 95.04 ;
    END
  END i_d[84]
  PIN i_d[85]
    DIRECTION INPUT ;
    USE SIGNAL ;
    PORT
      LAYER M5 ;
        RECT  18.816 94.848 18.84 95.04 ;
    END
  END i_d[85]
  PIN i_d[86]
    DIRECTION INPUT ;
    USE SIGNAL ;
    PORT
      LAYER M5 ;
        RECT  18.96 94.848 18.984 95.04 ;
    END
  END i_d[86]
  PIN i_d[87]
    DIRECTION INPUT ;
    USE SIGNAL ;
    PORT
      LAYER M5 ;
        RECT  19.104 94.848 19.128 95.04 ;
    END
  END i_d[87]
  PIN i_d[88]
    DIRECTION INPUT ;
    USE SIGNAL ;
    PORT
      LAYER M5 ;
        RECT  19.392 94.848 19.416 95.04 ;
    END
  END i_d[88]
  PIN i_d[89]
    DIRECTION INPUT ;
    USE SIGNAL ;
    PORT
      LAYER M5 ;
        RECT  19.536 94.848 19.56 95.04 ;
    END
  END i_d[89]
  PIN i_d[8]
    DIRECTION INPUT ;
    USE SIGNAL ;
    PORT
      LAYER M5 ;
        RECT  6.144 94.848 6.168 95.04 ;
    END
  END i_d[8]
  PIN i_d[90]
    DIRECTION INPUT ;
    USE SIGNAL ;
    PORT
      LAYER M5 ;
        RECT  19.68 94.848 19.704 95.04 ;
    END
  END i_d[90]
  PIN i_d[91]
    DIRECTION INPUT ;
    USE SIGNAL ;
    PORT
      LAYER M5 ;
        RECT  19.824 94.848 19.848 95.04 ;
    END
  END i_d[91]
  PIN i_d[92]
    DIRECTION INPUT ;
    USE SIGNAL ;
    PORT
      LAYER M5 ;
        RECT  19.968 94.848 19.992 95.04 ;
    END
  END i_d[92]
  PIN i_d[93]
    DIRECTION INPUT ;
    USE SIGNAL ;
    PORT
      LAYER M5 ;
        RECT  20.112 94.848 20.136 95.04 ;
    END
  END i_d[93]
  PIN i_d[94]
    DIRECTION INPUT ;
    USE SIGNAL ;
    PORT
      LAYER M5 ;
        RECT  20.256 94.848 20.28 95.04 ;
    END
  END i_d[94]
  PIN i_d[95]
    DIRECTION INPUT ;
    USE SIGNAL ;
    PORT
      LAYER M5 ;
        RECT  20.4 94.848 20.424 95.04 ;
    END
  END i_d[95]
  PIN i_d[96]
    DIRECTION INPUT ;
    USE SIGNAL ;
    PORT
      LAYER M5 ;
        RECT  20.544 94.848 20.568 95.04 ;
    END
  END i_d[96]
  PIN i_d[97]
    DIRECTION INPUT ;
    USE SIGNAL ;
    PORT
      LAYER M5 ;
        RECT  20.688 94.848 20.712 95.04 ;
    END
  END i_d[97]
  PIN i_d[98]
    DIRECTION INPUT ;
    USE SIGNAL ;
    PORT
      LAYER M5 ;
        RECT  20.832 94.848 20.856 95.04 ;
    END
  END i_d[98]
  PIN i_d[99]
    DIRECTION INPUT ;
    USE SIGNAL ;
    PORT
      LAYER M5 ;
        RECT  20.976 94.848 21 95.04 ;
    END
  END i_d[99]
  PIN i_d[9]
    DIRECTION INPUT ;
    USE SIGNAL ;
    PORT
      LAYER M5 ;
        RECT  6.288 94.848 6.312 95.04 ;
    END
  END i_d[9]
  PIN i_v
    DIRECTION INPUT ;
    USE SIGNAL ;
    PORT
      LAYER M4 ;
        RECT  0 88.704 0.192 88.728 ;
    END
    PORT
      LAYER M4 ;
        RECT  0.156 88.704 2.408 88.728 ;
    END
  END i_v
  PIN larm_base[0]
    DIRECTION INPUT ;
    USE SIGNAL ;
    PORT
      LAYER M4 ;
        RECT  0 33.696 0.192 33.72 ;
    END
    PORT
      LAYER M4 ;
        RECT  0.156 33.696 0.245 33.72 ;
    END
  END larm_base[0]
  PIN larm_base[10]
    DIRECTION INPUT ;
    USE SIGNAL ;
    PORT
      LAYER M4 ;
        RECT  0 73.008 0.192 73.032 ;
    END
    PORT
      LAYER M4 ;
        RECT  0.156 73.008 2.408 73.032 ;
    END
  END larm_base[10]
  PIN larm_base[11]
    DIRECTION INPUT ;
    USE SIGNAL ;
    PORT
      LAYER M4 ;
        RECT  0 76.896 0.192 76.92 ;
    END
    PORT
      LAYER M4 ;
        RECT  0.156 76.896 2.408 76.92 ;
    END
  END larm_base[11]
  PIN larm_base[12]
    DIRECTION INPUT ;
    USE SIGNAL ;
    PORT
      LAYER M4 ;
        RECT  0 80.784 0.192 80.808 ;
    END
    PORT
      LAYER M4 ;
        RECT  0.156 80.784 2.408 80.808 ;
    END
  END larm_base[12]
  PIN larm_base[13]
    DIRECTION INPUT ;
    USE SIGNAL ;
    PORT
      LAYER M4 ;
        RECT  0 84.816 0.192 84.84 ;
    END
    PORT
      LAYER M4 ;
        RECT  0.156 84.816 2.408 84.84 ;
    END
  END larm_base[13]
  PIN larm_base[1]
    DIRECTION INPUT ;
    USE SIGNAL ;
    PORT
      LAYER M4 ;
        RECT  0 37.584 0.192 37.608 ;
    END
    PORT
      LAYER M4 ;
        RECT  0.156 37.584 2.408 37.608 ;
    END
  END larm_base[1]
  PIN larm_base[2]
    DIRECTION INPUT ;
    USE SIGNAL ;
    PORT
      LAYER M4 ;
        RECT  0 41.616 0.192 41.64 ;
    END
    PORT
      LAYER M4 ;
        RECT  0.156 41.616 2.408 41.64 ;
    END
  END larm_base[2]
  PIN larm_base[3]
    DIRECTION INPUT ;
    USE SIGNAL ;
    PORT
      LAYER M4 ;
        RECT  0 45.504 0.192 45.528 ;
    END
    PORT
      LAYER M4 ;
        RECT  0.156 45.504 2.408 45.528 ;
    END
  END larm_base[3]
  PIN larm_base[4]
    DIRECTION INPUT ;
    USE SIGNAL ;
    PORT
      LAYER M4 ;
        RECT  0 49.392 0.192 49.416 ;
    END
    PORT
      LAYER M4 ;
        RECT  0.156 49.392 2.408 49.416 ;
    END
  END larm_base[4]
  PIN larm_base[5]
    DIRECTION INPUT ;
    USE SIGNAL ;
    PORT
      LAYER M4 ;
        RECT  0 53.28 0.192 53.304 ;
    END
    PORT
      LAYER M4 ;
        RECT  0.156 53.28 2.408 53.304 ;
    END
  END larm_base[5]
  PIN larm_base[6]
    DIRECTION INPUT ;
    USE SIGNAL ;
    PORT
      LAYER M4 ;
        RECT  0 57.312 0.192 57.336 ;
    END
    PORT
      LAYER M4 ;
        RECT  0.156 57.312 2.408 57.336 ;
    END
  END larm_base[6]
  PIN larm_base[7]
    DIRECTION INPUT ;
    USE SIGNAL ;
    PORT
      LAYER M4 ;
        RECT  0 61.2 0.192 61.224 ;
    END
    PORT
      LAYER M4 ;
        RECT  0.156 61.2 2.408 61.224 ;
    END
  END larm_base[7]
  PIN larm_base[8]
    DIRECTION INPUT ;
    USE SIGNAL ;
    PORT
      LAYER M4 ;
        RECT  0 65.088 0.192 65.112 ;
    END
    PORT
      LAYER M4 ;
        RECT  0.156 65.088 2.408 65.112 ;
    END
  END larm_base[8]
  PIN larm_base[9]
    DIRECTION INPUT ;
    USE SIGNAL ;
    PORT
      LAYER M4 ;
        RECT  0 69.12 0.192 69.144 ;
    END
    PORT
      LAYER M4 ;
        RECT  0.156 69.12 2.408 69.144 ;
    END
  END larm_base[9]
  PIN larm_g[0]
    DIRECTION INPUT ;
    USE SIGNAL ;
    PORT
      LAYER M4 ;
        RECT  0 18 0.192 18.024 ;
    END
    PORT
      LAYER M4 ;
        RECT  0.156 18 2.408 18.024 ;
    END
  END larm_g[0]
  PIN larm_g[1]
    DIRECTION INPUT ;
    USE SIGNAL ;
    PORT
      LAYER M4 ;
        RECT  0 21.888 0.192 21.912 ;
    END
    PORT
      LAYER M4 ;
        RECT  0.156 21.888 2.408 21.912 ;
    END
  END larm_g[1]
  PIN larm_g[2]
    DIRECTION INPUT ;
    USE SIGNAL ;
    PORT
      LAYER M4 ;
        RECT  0 25.92 0.192 25.944 ;
    END
    PORT
      LAYER M4 ;
        RECT  0.156 25.92 2.408 25.944 ;
    END
  END larm_g[2]
  PIN larm_g[3]
    DIRECTION INPUT ;
    USE SIGNAL ;
    PORT
      LAYER M4 ;
        RECT  0 29.808 0.192 29.832 ;
    END
    PORT
      LAYER M4 ;
        RECT  0.156 29.808 2.408 29.832 ;
    END
  END larm_g[3]
  PIN larm_v
    DIRECTION INPUT ;
    USE SIGNAL ;
    PORT
      LAYER M4 ;
        RECT  0 14.112 0.192 14.136 ;
    END
    PORT
      LAYER M4 ;
        RECT  0.156 14.112 2.408 14.136 ;
    END
  END larm_v
  PIN o_d[0]
    DIRECTION OUTPUT ;
    USE SIGNAL ;
    PORT
      LAYER M5 ;
        RECT  4.32 0 4.344 0.192 ;
    END
  END o_d[0]
  PIN o_d[100]
    DIRECTION OUTPUT ;
    USE SIGNAL ;
    PORT
      LAYER M5 ;
        RECT  20.688 0 20.712 0.192 ;
    END
  END o_d[100]
  PIN o_d[101]
    DIRECTION OUTPUT ;
    USE SIGNAL ;
    PORT
      LAYER M5 ;
        RECT  20.832 0 20.856 0.192 ;
    END
  END o_d[101]
  PIN o_d[102]
    DIRECTION OUTPUT ;
    USE SIGNAL ;
    PORT
      LAYER M5 ;
        RECT  20.976 0 21 0.192 ;
    END
  END o_d[102]
  PIN o_d[103]
    DIRECTION OUTPUT ;
    USE SIGNAL ;
    PORT
      LAYER M5 ;
        RECT  21.12 0 21.144 0.192 ;
    END
  END o_d[103]
  PIN o_d[104]
    DIRECTION OUTPUT ;
    USE SIGNAL ;
    PORT
      LAYER M5 ;
        RECT  21.264 0 21.288 0.192 ;
    END
  END o_d[104]
  PIN o_d[105]
    DIRECTION OUTPUT ;
    USE SIGNAL ;
    PORT
      LAYER M5 ;
        RECT  21.408 0 21.432 0.192 ;
    END
  END o_d[105]
  PIN o_d[106]
    DIRECTION OUTPUT ;
    USE SIGNAL ;
    PORT
      LAYER M5 ;
        RECT  21.552 0 21.576 0.192 ;
    END
  END o_d[106]
  PIN o_d[107]
    DIRECTION OUTPUT ;
    USE SIGNAL ;
    PORT
      LAYER M5 ;
        RECT  21.696 0 21.72 0.192 ;
    END
  END o_d[107]
  PIN o_d[108]
    DIRECTION OUTPUT ;
    USE SIGNAL ;
    PORT
      LAYER M5 ;
        RECT  22.512 0 22.536 0.192 ;
    END
  END o_d[108]
  PIN o_d[109]
    DIRECTION OUTPUT ;
    USE SIGNAL ;
    PORT
      LAYER M5 ;
        RECT  22.656 0 22.68 0.192 ;
    END
  END o_d[109]
  PIN o_d[10]
    DIRECTION OUTPUT ;
    USE SIGNAL ;
    PORT
      LAYER M5 ;
        RECT  6.288 0 6.312 0.192 ;
    END
  END o_d[10]
  PIN o_d[110]
    DIRECTION OUTPUT ;
    USE SIGNAL ;
    PORT
      LAYER M5 ;
        RECT  22.8 0 22.824 0.192 ;
    END
  END o_d[110]
  PIN o_d[111]
    DIRECTION OUTPUT ;
    USE SIGNAL ;
    PORT
      LAYER M5 ;
        RECT  22.944 0 22.968 0.192 ;
    END
  END o_d[111]
  PIN o_d[112]
    DIRECTION OUTPUT ;
    USE SIGNAL ;
    PORT
      LAYER M5 ;
        RECT  23.088 0 23.112 0.192 ;
    END
  END o_d[112]
  PIN o_d[113]
    DIRECTION OUTPUT ;
    USE SIGNAL ;
    PORT
      LAYER M5 ;
        RECT  23.232 0 23.256 0.192 ;
    END
  END o_d[113]
  PIN o_d[114]
    DIRECTION OUTPUT ;
    USE SIGNAL ;
    PORT
      LAYER M5 ;
        RECT  23.376 0 23.4 0.192 ;
    END
  END o_d[114]
  PIN o_d[115]
    DIRECTION OUTPUT ;
    USE SIGNAL ;
    PORT
      LAYER M5 ;
        RECT  23.52 0 23.544 0.192 ;
    END
  END o_d[115]
  PIN o_d[116]
    DIRECTION OUTPUT ;
    USE SIGNAL ;
    PORT
      LAYER M5 ;
        RECT  23.664 0 23.688 0.192 ;
    END
  END o_d[116]
  PIN o_d[117]
    DIRECTION OUTPUT ;
    USE SIGNAL ;
    PORT
      LAYER M5 ;
        RECT  23.808 0 23.832 0.192 ;
    END
  END o_d[117]
  PIN o_d[118]
    DIRECTION OUTPUT ;
    USE SIGNAL ;
    PORT
      LAYER M5 ;
        RECT  23.952 0 23.976 0.192 ;
    END
  END o_d[118]
  PIN o_d[119]
    DIRECTION OUTPUT ;
    USE SIGNAL ;
    PORT
      LAYER M5 ;
        RECT  24.096 0 24.12 0.192 ;
    END
  END o_d[119]
  PIN o_d[11]
    DIRECTION OUTPUT ;
    USE SIGNAL ;
    PORT
      LAYER M5 ;
        RECT  6.432 0 6.456 0.192 ;
    END
  END o_d[11]
  PIN o_d[120]
    DIRECTION OUTPUT ;
    USE SIGNAL ;
    PORT
      LAYER M5 ;
        RECT  24.24 0 24.264 0.192 ;
    END
  END o_d[120]
  PIN o_d[121]
    DIRECTION OUTPUT ;
    USE SIGNAL ;
    PORT
      LAYER M5 ;
        RECT  24.384 0 24.408 0.192 ;
    END
  END o_d[121]
  PIN o_d[122]
    DIRECTION OUTPUT ;
    USE SIGNAL ;
    PORT
      LAYER M5 ;
        RECT  24.528 0 24.552 0.192 ;
    END
  END o_d[122]
  PIN o_d[123]
    DIRECTION OUTPUT ;
    USE SIGNAL ;
    PORT
      LAYER M5 ;
        RECT  24.672 0 24.696 0.192 ;
    END
  END o_d[123]
  PIN o_d[124]
    DIRECTION OUTPUT ;
    USE SIGNAL ;
    PORT
      LAYER M5 ;
        RECT  24.816 0 24.84 0.192 ;
    END
  END o_d[124]
  PIN o_d[125]
    DIRECTION OUTPUT ;
    USE SIGNAL ;
    PORT
      LAYER M5 ;
        RECT  24.96 0 24.984 0.192 ;
    END
  END o_d[125]
  PIN o_d[126]
    DIRECTION OUTPUT ;
    USE SIGNAL ;
    PORT
      LAYER M5 ;
        RECT  25.104 0 25.128 0.192 ;
    END
  END o_d[126]
  PIN o_d[127]
    DIRECTION OUTPUT ;
    USE SIGNAL ;
    PORT
      LAYER M5 ;
        RECT  25.248 0 25.272 0.192 ;
    END
  END o_d[127]
  PIN o_d[128]
    DIRECTION OUTPUT ;
    USE SIGNAL ;
    PORT
      LAYER M5 ;
        RECT  25.392 0 25.416 0.192 ;
    END
  END o_d[128]
  PIN o_d[129]
    DIRECTION OUTPUT ;
    USE SIGNAL ;
    PORT
      LAYER M5 ;
        RECT  25.536 0 25.56 0.192 ;
    END
  END o_d[129]
  PIN o_d[12]
    DIRECTION OUTPUT ;
    USE SIGNAL ;
    PORT
      LAYER M5 ;
        RECT  6.576 0 6.6 0.192 ;
    END
  END o_d[12]
  PIN o_d[130]
    DIRECTION OUTPUT ;
    USE SIGNAL ;
    PORT
      LAYER M5 ;
        RECT  25.68 0 25.704 0.192 ;
    END
  END o_d[130]
  PIN o_d[131]
    DIRECTION OUTPUT ;
    USE SIGNAL ;
    PORT
      LAYER M5 ;
        RECT  25.824 0 25.848 0.192 ;
    END
  END o_d[131]
  PIN o_d[132]
    DIRECTION OUTPUT ;
    USE SIGNAL ;
    PORT
      LAYER M5 ;
        RECT  25.968 0 25.992 0.192 ;
    END
  END o_d[132]
  PIN o_d[133]
    DIRECTION OUTPUT ;
    USE SIGNAL ;
    PORT
      LAYER M5 ;
        RECT  26.112 0 26.136 0.192 ;
    END
  END o_d[133]
  PIN o_d[134]
    DIRECTION OUTPUT ;
    USE SIGNAL ;
    PORT
      LAYER M5 ;
        RECT  26.256 0 26.28 0.192 ;
    END
  END o_d[134]
  PIN o_d[135]
    DIRECTION OUTPUT ;
    USE SIGNAL ;
    PORT
      LAYER M5 ;
        RECT  26.4 0 26.424 0.192 ;
    END
  END o_d[135]
  PIN o_d[136]
    DIRECTION OUTPUT ;
    USE SIGNAL ;
    PORT
      LAYER M5 ;
        RECT  26.544 0 26.568 0.192 ;
    END
  END o_d[136]
  PIN o_d[137]
    DIRECTION OUTPUT ;
    USE SIGNAL ;
    PORT
      LAYER M5 ;
        RECT  26.688 0 26.712 0.192 ;
    END
  END o_d[137]
  PIN o_d[138]
    DIRECTION OUTPUT ;
    USE SIGNAL ;
    PORT
      LAYER M5 ;
        RECT  26.832 0 26.856 0.192 ;
    END
  END o_d[138]
  PIN o_d[139]
    DIRECTION OUTPUT ;
    USE SIGNAL ;
    PORT
      LAYER M5 ;
        RECT  27.12 0 27.144 0.192 ;
    END
  END o_d[139]
  PIN o_d[13]
    DIRECTION OUTPUT ;
    USE SIGNAL ;
    PORT
      LAYER M5 ;
        RECT  6.72 0 6.744 0.192 ;
    END
  END o_d[13]
  PIN o_d[140]
    DIRECTION OUTPUT ;
    USE SIGNAL ;
    PORT
      LAYER M5 ;
        RECT  27.744 0 27.768 0.192 ;
    END
  END o_d[140]
  PIN o_d[141]
    DIRECTION OUTPUT ;
    USE SIGNAL ;
    PORT
      LAYER M5 ;
        RECT  27.888 0 27.912 0.192 ;
    END
  END o_d[141]
  PIN o_d[142]
    DIRECTION OUTPUT ;
    USE SIGNAL ;
    PORT
      LAYER M5 ;
        RECT  28.032 0 28.056 0.192 ;
    END
  END o_d[142]
  PIN o_d[143]
    DIRECTION OUTPUT ;
    USE SIGNAL ;
    PORT
      LAYER M5 ;
        RECT  28.176 0 28.2 0.192 ;
    END
  END o_d[143]
  PIN o_d[144]
    DIRECTION OUTPUT ;
    USE SIGNAL ;
    PORT
      LAYER M5 ;
        RECT  28.32 0 28.344 0.192 ;
    END
  END o_d[144]
  PIN o_d[145]
    DIRECTION OUTPUT ;
    USE SIGNAL ;
    PORT
      LAYER M5 ;
        RECT  28.464 0 28.488 0.192 ;
    END
  END o_d[145]
  PIN o_d[146]
    DIRECTION OUTPUT ;
    USE SIGNAL ;
    PORT
      LAYER M5 ;
        RECT  28.608 0 28.632 0.192 ;
    END
  END o_d[146]
  PIN o_d[147]
    DIRECTION OUTPUT ;
    USE SIGNAL ;
    PORT
      LAYER M5 ;
        RECT  28.752 0 28.776 0.192 ;
    END
  END o_d[147]
  PIN o_d[148]
    DIRECTION OUTPUT ;
    USE SIGNAL ;
    PORT
      LAYER M5 ;
        RECT  28.896 0 28.92 0.192 ;
    END
  END o_d[148]
  PIN o_d[149]
    DIRECTION OUTPUT ;
    USE SIGNAL ;
    PORT
      LAYER M5 ;
        RECT  29.04 0 29.064 0.192 ;
    END
  END o_d[149]
  PIN o_d[14]
    DIRECTION OUTPUT ;
    USE SIGNAL ;
    PORT
      LAYER M5 ;
        RECT  6.864 0 6.888 0.192 ;
    END
  END o_d[14]
  PIN o_d[150]
    DIRECTION OUTPUT ;
    USE SIGNAL ;
    PORT
      LAYER M5 ;
        RECT  29.184 0 29.208 0.192 ;
    END
  END o_d[150]
  PIN o_d[151]
    DIRECTION OUTPUT ;
    USE SIGNAL ;
    PORT
      LAYER M5 ;
        RECT  29.328 0 29.352 0.192 ;
    END
  END o_d[151]
  PIN o_d[152]
    DIRECTION OUTPUT ;
    USE SIGNAL ;
    PORT
      LAYER M5 ;
        RECT  29.472 0 29.496 0.192 ;
    END
  END o_d[152]
  PIN o_d[153]
    DIRECTION OUTPUT ;
    USE SIGNAL ;
    PORT
      LAYER M5 ;
        RECT  29.616 0 29.64 0.192 ;
    END
  END o_d[153]
  PIN o_d[154]
    DIRECTION OUTPUT ;
    USE SIGNAL ;
    PORT
      LAYER M5 ;
        RECT  29.76 0 29.784 0.192 ;
    END
  END o_d[154]
  PIN o_d[155]
    DIRECTION OUTPUT ;
    USE SIGNAL ;
    PORT
      LAYER M5 ;
        RECT  29.904 0 29.928 0.192 ;
    END
  END o_d[155]
  PIN o_d[156]
    DIRECTION OUTPUT ;
    USE SIGNAL ;
    PORT
      LAYER M5 ;
        RECT  30.048 0 30.072 0.192 ;
    END
  END o_d[156]
  PIN o_d[157]
    DIRECTION OUTPUT ;
    USE SIGNAL ;
    PORT
      LAYER M5 ;
        RECT  30.192 0 30.216 0.192 ;
    END
  END o_d[157]
  PIN o_d[158]
    DIRECTION OUTPUT ;
    USE SIGNAL ;
    PORT
      LAYER M5 ;
        RECT  30.336 0 30.36 0.192 ;
    END
  END o_d[158]
  PIN o_d[159]
    DIRECTION OUTPUT ;
    USE SIGNAL ;
    PORT
      LAYER M5 ;
        RECT  30.48 0 30.504 0.192 ;
    END
  END o_d[159]
  PIN o_d[15]
    DIRECTION OUTPUT ;
    USE SIGNAL ;
    PORT
      LAYER M5 ;
        RECT  7.152 0 7.176 0.192 ;
    END
  END o_d[15]
  PIN o_d[160]
    DIRECTION OUTPUT ;
    USE SIGNAL ;
    PORT
      LAYER M5 ;
        RECT  30.624 0 30.648 0.192 ;
    END
  END o_d[160]
  PIN o_d[161]
    DIRECTION OUTPUT ;
    USE SIGNAL ;
    PORT
      LAYER M5 ;
        RECT  30.768 0 30.792 0.192 ;
    END
  END o_d[161]
  PIN o_d[162]
    DIRECTION OUTPUT ;
    USE SIGNAL ;
    PORT
      LAYER M5 ;
        RECT  30.912 0 30.936 0.192 ;
    END
  END o_d[162]
  PIN o_d[163]
    DIRECTION OUTPUT ;
    USE SIGNAL ;
    PORT
      LAYER M5 ;
        RECT  31.056 0 31.08 0.192 ;
    END
  END o_d[163]
  PIN o_d[164]
    DIRECTION OUTPUT ;
    USE SIGNAL ;
    PORT
      LAYER M5 ;
        RECT  31.2 0 31.224 0.192 ;
    END
  END o_d[164]
  PIN o_d[165]
    DIRECTION OUTPUT ;
    USE SIGNAL ;
    PORT
      LAYER M5 ;
        RECT  31.344 0 31.368 0.192 ;
    END
  END o_d[165]
  PIN o_d[166]
    DIRECTION OUTPUT ;
    USE SIGNAL ;
    PORT
      LAYER M5 ;
        RECT  31.488 0 31.512 0.192 ;
    END
  END o_d[166]
  PIN o_d[167]
    DIRECTION OUTPUT ;
    USE SIGNAL ;
    PORT
      LAYER M5 ;
        RECT  31.632 0 31.656 0.192 ;
    END
  END o_d[167]
  PIN o_d[168]
    DIRECTION OUTPUT ;
    USE SIGNAL ;
    PORT
      LAYER M5 ;
        RECT  31.776 0 31.8 0.192 ;
    END
  END o_d[168]
  PIN o_d[169]
    DIRECTION OUTPUT ;
    USE SIGNAL ;
    PORT
      LAYER M5 ;
        RECT  31.92 0 31.944 0.192 ;
    END
  END o_d[169]
  PIN o_d[16]
    DIRECTION OUTPUT ;
    USE SIGNAL ;
    PORT
      LAYER M5 ;
        RECT  7.296 0 7.32 0.192 ;
    END
  END o_d[16]
  PIN o_d[170]
    DIRECTION OUTPUT ;
    USE SIGNAL ;
    PORT
      LAYER M5 ;
        RECT  32.208 0 32.232 0.192 ;
    END
  END o_d[170]
  PIN o_d[171]
    DIRECTION OUTPUT ;
    USE SIGNAL ;
    PORT
      LAYER M5 ;
        RECT  32.352 0 32.376 0.192 ;
    END
  END o_d[171]
  PIN o_d[172]
    DIRECTION OUTPUT ;
    USE SIGNAL ;
    PORT
      LAYER M5 ;
        RECT  32.496 0 32.52 0.192 ;
    END
  END o_d[172]
  PIN o_d[173]
    DIRECTION OUTPUT ;
    USE SIGNAL ;
    PORT
      LAYER M5 ;
        RECT  33.168 0 33.192 0.192 ;
    END
  END o_d[173]
  PIN o_d[174]
    DIRECTION OUTPUT ;
    USE SIGNAL ;
    PORT
      LAYER M5 ;
        RECT  33.312 0 33.336 0.192 ;
    END
  END o_d[174]
  PIN o_d[175]
    DIRECTION OUTPUT ;
    USE SIGNAL ;
    PORT
      LAYER M5 ;
        RECT  33.456 0 33.48 0.192 ;
    END
  END o_d[175]
  PIN o_d[176]
    DIRECTION OUTPUT ;
    USE SIGNAL ;
    PORT
      LAYER M5 ;
        RECT  33.6 0 33.624 0.192 ;
    END
  END o_d[176]
  PIN o_d[177]
    DIRECTION OUTPUT ;
    USE SIGNAL ;
    PORT
      LAYER M5 ;
        RECT  33.744 0 33.768 0.192 ;
    END
  END o_d[177]
  PIN o_d[178]
    DIRECTION OUTPUT ;
    USE SIGNAL ;
    PORT
      LAYER M5 ;
        RECT  33.888 0 33.912 0.192 ;
    END
  END o_d[178]
  PIN o_d[179]
    DIRECTION OUTPUT ;
    USE SIGNAL ;
    PORT
      LAYER M5 ;
        RECT  34.032 0 34.056 0.192 ;
    END
  END o_d[179]
  PIN o_d[17]
    DIRECTION OUTPUT ;
    USE SIGNAL ;
    PORT
      LAYER M5 ;
        RECT  7.44 0 7.464 0.192 ;
    END
  END o_d[17]
  PIN o_d[180]
    DIRECTION OUTPUT ;
    USE SIGNAL ;
    PORT
      LAYER M5 ;
        RECT  34.176 0 34.2 0.192 ;
    END
  END o_d[180]
  PIN o_d[181]
    DIRECTION OUTPUT ;
    USE SIGNAL ;
    PORT
      LAYER M5 ;
        RECT  34.32 0 34.344 0.192 ;
    END
  END o_d[181]
  PIN o_d[182]
    DIRECTION OUTPUT ;
    USE SIGNAL ;
    PORT
      LAYER M5 ;
        RECT  34.464 0 34.488 0.192 ;
    END
  END o_d[182]
  PIN o_d[183]
    DIRECTION OUTPUT ;
    USE SIGNAL ;
    PORT
      LAYER M5 ;
        RECT  34.608 0 34.632 0.192 ;
    END
  END o_d[183]
  PIN o_d[184]
    DIRECTION OUTPUT ;
    USE SIGNAL ;
    PORT
      LAYER M5 ;
        RECT  34.752 0 34.776 0.192 ;
    END
  END o_d[184]
  PIN o_d[185]
    DIRECTION OUTPUT ;
    USE SIGNAL ;
    PORT
      LAYER M5 ;
        RECT  34.896 0 34.92 0.192 ;
    END
  END o_d[185]
  PIN o_d[186]
    DIRECTION OUTPUT ;
    USE SIGNAL ;
    PORT
      LAYER M5 ;
        RECT  35.04 0 35.064 0.192 ;
    END
  END o_d[186]
  PIN o_d[187]
    DIRECTION OUTPUT ;
    USE SIGNAL ;
    PORT
      LAYER M5 ;
        RECT  35.184 0 35.208 0.192 ;
    END
  END o_d[187]
  PIN o_d[188]
    DIRECTION OUTPUT ;
    USE SIGNAL ;
    PORT
      LAYER M5 ;
        RECT  35.328 0 35.352 0.192 ;
    END
  END o_d[188]
  PIN o_d[189]
    DIRECTION OUTPUT ;
    USE SIGNAL ;
    PORT
      LAYER M5 ;
        RECT  35.472 0 35.496 0.192 ;
    END
  END o_d[189]
  PIN o_d[18]
    DIRECTION OUTPUT ;
    USE SIGNAL ;
    PORT
      LAYER M5 ;
        RECT  7.584 0 7.608 0.192 ;
    END
  END o_d[18]
  PIN o_d[190]
    DIRECTION OUTPUT ;
    USE SIGNAL ;
    PORT
      LAYER M5 ;
        RECT  35.616 0 35.64 0.192 ;
    END
  END o_d[190]
  PIN o_d[191]
    DIRECTION OUTPUT ;
    USE SIGNAL ;
    PORT
      LAYER M5 ;
        RECT  35.76 0 35.784 0.192 ;
    END
  END o_d[191]
  PIN o_d[192]
    DIRECTION OUTPUT ;
    USE SIGNAL ;
    PORT
      LAYER M5 ;
        RECT  35.904 0 35.928 0.192 ;
    END
  END o_d[192]
  PIN o_d[193]
    DIRECTION OUTPUT ;
    USE SIGNAL ;
    PORT
      LAYER M5 ;
        RECT  36.048 0 36.072 0.192 ;
    END
  END o_d[193]
  PIN o_d[194]
    DIRECTION OUTPUT ;
    USE SIGNAL ;
    PORT
      LAYER M5 ;
        RECT  36.192 0 36.216 0.192 ;
    END
  END o_d[194]
  PIN o_d[195]
    DIRECTION OUTPUT ;
    USE SIGNAL ;
    PORT
      LAYER M5 ;
        RECT  36.336 0 36.36 0.192 ;
    END
  END o_d[195]
  PIN o_d[196]
    DIRECTION OUTPUT ;
    USE SIGNAL ;
    PORT
      LAYER M5 ;
        RECT  36.48 0 36.504 0.192 ;
    END
  END o_d[196]
  PIN o_d[197]
    DIRECTION OUTPUT ;
    USE SIGNAL ;
    PORT
      LAYER M5 ;
        RECT  36.624 0 36.648 0.192 ;
    END
  END o_d[197]
  PIN o_d[198]
    DIRECTION OUTPUT ;
    USE SIGNAL ;
    PORT
      LAYER M5 ;
        RECT  36.768 0 36.792 0.192 ;
    END
  END o_d[198]
  PIN o_d[199]
    DIRECTION OUTPUT ;
    USE SIGNAL ;
    PORT
      LAYER M5 ;
        RECT  36.912 0 36.936 0.192 ;
    END
  END o_d[199]
  PIN o_d[19]
    DIRECTION OUTPUT ;
    USE SIGNAL ;
    PORT
      LAYER M5 ;
        RECT  7.728 0 7.752 0.192 ;
    END
  END o_d[19]
  PIN o_d[1]
    DIRECTION OUTPUT ;
    USE SIGNAL ;
    PORT
      LAYER M5 ;
        RECT  4.464 0 4.488 0.192 ;
    END
  END o_d[1]
  PIN o_d[200]
    DIRECTION OUTPUT ;
    USE SIGNAL ;
    PORT
      LAYER M5 ;
        RECT  37.056 0 37.08 0.192 ;
    END
  END o_d[200]
  PIN o_d[201]
    DIRECTION OUTPUT ;
    USE SIGNAL ;
    PORT
      LAYER M5 ;
        RECT  37.344 0 37.368 0.192 ;
    END
  END o_d[201]
  PIN o_d[202]
    DIRECTION OUTPUT ;
    USE SIGNAL ;
    PORT
      LAYER M5 ;
        RECT  37.488 0 37.512 0.192 ;
    END
  END o_d[202]
  PIN o_d[203]
    DIRECTION OUTPUT ;
    USE SIGNAL ;
    PORT
      LAYER M5 ;
        RECT  37.632 0 37.656 0.192 ;
    END
  END o_d[203]
  PIN o_d[204]
    DIRECTION OUTPUT ;
    USE SIGNAL ;
    PORT
      LAYER M5 ;
        RECT  37.776 0 37.8 0.192 ;
    END
  END o_d[204]
  PIN o_d[205]
    DIRECTION OUTPUT ;
    USE SIGNAL ;
    PORT
      LAYER M5 ;
        RECT  37.92 0 37.944 0.192 ;
    END
  END o_d[205]
  PIN o_d[206]
    DIRECTION OUTPUT ;
    USE SIGNAL ;
    PORT
      LAYER M5 ;
        RECT  38.544 0 38.568 0.192 ;
    END
  END o_d[206]
  PIN o_d[207]
    DIRECTION OUTPUT ;
    USE SIGNAL ;
    PORT
      LAYER M5 ;
        RECT  38.688 0 38.712 0.192 ;
    END
  END o_d[207]
  PIN o_d[208]
    DIRECTION OUTPUT ;
    USE SIGNAL ;
    PORT
      LAYER M5 ;
        RECT  38.832 0 38.856 0.192 ;
    END
  END o_d[208]
  PIN o_d[209]
    DIRECTION OUTPUT ;
    USE SIGNAL ;
    PORT
      LAYER M5 ;
        RECT  38.976 0 39 0.192 ;
    END
  END o_d[209]
  PIN o_d[20]
    DIRECTION OUTPUT ;
    USE SIGNAL ;
    PORT
      LAYER M5 ;
        RECT  7.872 0 7.896 0.192 ;
    END
  END o_d[20]
  PIN o_d[210]
    DIRECTION OUTPUT ;
    USE SIGNAL ;
    PORT
      LAYER M5 ;
        RECT  39.12 0 39.144 0.192 ;
    END
  END o_d[210]
  PIN o_d[211]
    DIRECTION OUTPUT ;
    USE SIGNAL ;
    PORT
      LAYER M5 ;
        RECT  39.264 0 39.288 0.192 ;
    END
  END o_d[211]
  PIN o_d[212]
    DIRECTION OUTPUT ;
    USE SIGNAL ;
    PORT
      LAYER M5 ;
        RECT  39.408 0 39.432 0.192 ;
    END
  END o_d[212]
  PIN o_d[213]
    DIRECTION OUTPUT ;
    USE SIGNAL ;
    PORT
      LAYER M5 ;
        RECT  39.552 0 39.576 0.192 ;
    END
  END o_d[213]
  PIN o_d[214]
    DIRECTION OUTPUT ;
    USE SIGNAL ;
    PORT
      LAYER M5 ;
        RECT  39.696 0 39.72 0.192 ;
    END
  END o_d[214]
  PIN o_d[215]
    DIRECTION OUTPUT ;
    USE SIGNAL ;
    PORT
      LAYER M5 ;
        RECT  39.84 0 39.864 0.192 ;
    END
  END o_d[215]
  PIN o_d[216]
    DIRECTION OUTPUT ;
    USE SIGNAL ;
    PORT
      LAYER M5 ;
        RECT  39.984 0 40.008 0.192 ;
    END
  END o_d[216]
  PIN o_d[217]
    DIRECTION OUTPUT ;
    USE SIGNAL ;
    PORT
      LAYER M5 ;
        RECT  40.128 0 40.152 0.192 ;
    END
  END o_d[217]
  PIN o_d[218]
    DIRECTION OUTPUT ;
    USE SIGNAL ;
    PORT
      LAYER M5 ;
        RECT  40.272 0 40.296 0.192 ;
    END
  END o_d[218]
  PIN o_d[219]
    DIRECTION OUTPUT ;
    USE SIGNAL ;
    PORT
      LAYER M5 ;
        RECT  40.416 0 40.44 0.192 ;
    END
  END o_d[219]
  PIN o_d[21]
    DIRECTION OUTPUT ;
    USE SIGNAL ;
    PORT
      LAYER M5 ;
        RECT  8.016 0 8.04 0.192 ;
    END
  END o_d[21]
  PIN o_d[220]
    DIRECTION OUTPUT ;
    USE SIGNAL ;
    PORT
      LAYER M5 ;
        RECT  40.56 0 40.584 0.192 ;
    END
  END o_d[220]
  PIN o_d[221]
    DIRECTION OUTPUT ;
    USE SIGNAL ;
    PORT
      LAYER M5 ;
        RECT  40.704 0 40.728 0.192 ;
    END
  END o_d[221]
  PIN o_d[222]
    DIRECTION OUTPUT ;
    USE SIGNAL ;
    PORT
      LAYER M5 ;
        RECT  40.848 0 40.872 0.192 ;
    END
  END o_d[222]
  PIN o_d[223]
    DIRECTION OUTPUT ;
    USE SIGNAL ;
    PORT
      LAYER M5 ;
        RECT  40.992 0 41.016 0.192 ;
    END
  END o_d[223]
  PIN o_d[224]
    DIRECTION OUTPUT ;
    USE SIGNAL ;
    PORT
      LAYER M5 ;
        RECT  41.136 0 41.16 0.192 ;
    END
  END o_d[224]
  PIN o_d[225]
    DIRECTION OUTPUT ;
    USE SIGNAL ;
    PORT
      LAYER M5 ;
        RECT  41.28 0 41.304 0.192 ;
    END
  END o_d[225]
  PIN o_d[226]
    DIRECTION OUTPUT ;
    USE SIGNAL ;
    PORT
      LAYER M5 ;
        RECT  41.424 0 41.448 0.192 ;
    END
  END o_d[226]
  PIN o_d[227]
    DIRECTION OUTPUT ;
    USE SIGNAL ;
    PORT
      LAYER M5 ;
        RECT  41.568 0 41.592 0.192 ;
    END
  END o_d[227]
  PIN o_d[228]
    DIRECTION OUTPUT ;
    USE SIGNAL ;
    PORT
      LAYER M5 ;
        RECT  41.712 0 41.736 0.192 ;
    END
  END o_d[228]
  PIN o_d[229]
    DIRECTION OUTPUT ;
    USE SIGNAL ;
    PORT
      LAYER M5 ;
        RECT  41.856 0 41.88 0.192 ;
    END
  END o_d[229]
  PIN o_d[22]
    DIRECTION OUTPUT ;
    USE SIGNAL ;
    PORT
      LAYER M5 ;
        RECT  8.16 0 8.184 0.192 ;
    END
  END o_d[22]
  PIN o_d[230]
    DIRECTION OUTPUT ;
    USE SIGNAL ;
    PORT
      LAYER M5 ;
        RECT  42 0 42.024 0.192 ;
    END
  END o_d[230]
  PIN o_d[231]
    DIRECTION OUTPUT ;
    USE SIGNAL ;
    PORT
      LAYER M5 ;
        RECT  42.144 0 42.168 0.192 ;
    END
  END o_d[231]
  PIN o_d[232]
    DIRECTION OUTPUT ;
    USE SIGNAL ;
    PORT
      LAYER M5 ;
        RECT  42.432 0 42.456 0.192 ;
    END
  END o_d[232]
  PIN o_d[233]
    DIRECTION OUTPUT ;
    USE SIGNAL ;
    PORT
      LAYER M5 ;
        RECT  42.576 0 42.6 0.192 ;
    END
  END o_d[233]
  PIN o_d[234]
    DIRECTION OUTPUT ;
    USE SIGNAL ;
    PORT
      LAYER M5 ;
        RECT  42.72 0 42.744 0.192 ;
    END
  END o_d[234]
  PIN o_d[235]
    DIRECTION OUTPUT ;
    USE SIGNAL ;
    PORT
      LAYER M5 ;
        RECT  42.864 0 42.888 0.192 ;
    END
  END o_d[235]
  PIN o_d[236]
    DIRECTION OUTPUT ;
    USE SIGNAL ;
    PORT
      LAYER M5 ;
        RECT  43.008 0 43.032 0.192 ;
    END
  END o_d[236]
  PIN o_d[237]
    DIRECTION OUTPUT ;
    USE SIGNAL ;
    PORT
      LAYER M5 ;
        RECT  43.152 0 43.176 0.192 ;
    END
  END o_d[237]
  PIN o_d[238]
    DIRECTION OUTPUT ;
    USE SIGNAL ;
    PORT
      LAYER M5 ;
        RECT  43.296 0 43.32 0.192 ;
    END
  END o_d[238]
  PIN o_d[239]
    DIRECTION OUTPUT ;
    USE SIGNAL ;
    PORT
      LAYER M5 ;
        RECT  43.968 0 43.992 0.192 ;
    END
  END o_d[239]
  PIN o_d[23]
    DIRECTION OUTPUT ;
    USE SIGNAL ;
    PORT
      LAYER M5 ;
        RECT  8.304 0 8.328 0.192 ;
    END
  END o_d[23]
  PIN o_d[240]
    DIRECTION OUTPUT ;
    USE SIGNAL ;
    PORT
      LAYER M5 ;
        RECT  44.112 0 44.136 0.192 ;
    END
  END o_d[240]
  PIN o_d[241]
    DIRECTION OUTPUT ;
    USE SIGNAL ;
    PORT
      LAYER M5 ;
        RECT  44.256 0 44.28 0.192 ;
    END
  END o_d[241]
  PIN o_d[242]
    DIRECTION OUTPUT ;
    USE SIGNAL ;
    PORT
      LAYER M5 ;
        RECT  44.4 0 44.424 0.192 ;
    END
  END o_d[242]
  PIN o_d[243]
    DIRECTION OUTPUT ;
    USE SIGNAL ;
    PORT
      LAYER M5 ;
        RECT  44.544 0 44.568 0.192 ;
    END
  END o_d[243]
  PIN o_d[244]
    DIRECTION OUTPUT ;
    USE SIGNAL ;
    PORT
      LAYER M5 ;
        RECT  44.688 0 44.712 0.192 ;
    END
  END o_d[244]
  PIN o_d[245]
    DIRECTION OUTPUT ;
    USE SIGNAL ;
    PORT
      LAYER M5 ;
        RECT  44.832 0 44.856 0.192 ;
    END
  END o_d[245]
  PIN o_d[246]
    DIRECTION OUTPUT ;
    USE SIGNAL ;
    PORT
      LAYER M5 ;
        RECT  44.976 0 45 0.192 ;
    END
  END o_d[246]
  PIN o_d[247]
    DIRECTION OUTPUT ;
    USE SIGNAL ;
    PORT
      LAYER M5 ;
        RECT  45.12 0 45.144 0.192 ;
    END
  END o_d[247]
  PIN o_d[248]
    DIRECTION OUTPUT ;
    USE SIGNAL ;
    PORT
      LAYER M5 ;
        RECT  45.264 0 45.288 0.192 ;
    END
  END o_d[248]
  PIN o_d[249]
    DIRECTION OUTPUT ;
    USE SIGNAL ;
    PORT
      LAYER M5 ;
        RECT  45.408 0 45.432 0.192 ;
    END
  END o_d[249]
  PIN o_d[24]
    DIRECTION OUTPUT ;
    USE SIGNAL ;
    PORT
      LAYER M5 ;
        RECT  8.448 0 8.472 0.192 ;
    END
  END o_d[24]
  PIN o_d[250]
    DIRECTION OUTPUT ;
    USE SIGNAL ;
    PORT
      LAYER M5 ;
        RECT  45.552 0 45.576 0.192 ;
    END
  END o_d[250]
  PIN o_d[251]
    DIRECTION OUTPUT ;
    USE SIGNAL ;
    PORT
      LAYER M5 ;
        RECT  45.696 0 45.72 0.192 ;
    END
  END o_d[251]
  PIN o_d[252]
    DIRECTION OUTPUT ;
    USE SIGNAL ;
    PORT
      LAYER M5 ;
        RECT  45.84 0 45.864 0.192 ;
    END
  END o_d[252]
  PIN o_d[253]
    DIRECTION OUTPUT ;
    USE SIGNAL ;
    PORT
      LAYER M5 ;
        RECT  45.984 0 46.008 0.192 ;
    END
  END o_d[253]
  PIN o_d[254]
    DIRECTION OUTPUT ;
    USE SIGNAL ;
    PORT
      LAYER M5 ;
        RECT  46.128 0 46.152 0.192 ;
    END
  END o_d[254]
  PIN o_d[255]
    DIRECTION OUTPUT ;
    USE SIGNAL ;
    PORT
      LAYER M5 ;
        RECT  46.272 0 46.296 0.192 ;
    END
  END o_d[255]
  PIN o_d[256]
    DIRECTION OUTPUT ;
    USE SIGNAL ;
    PORT
      LAYER M5 ;
        RECT  46.416 0 46.44 0.192 ;
    END
  END o_d[256]
  PIN o_d[257]
    DIRECTION OUTPUT ;
    USE SIGNAL ;
    PORT
      LAYER M5 ;
        RECT  46.56 0 46.584 0.192 ;
    END
  END o_d[257]
  PIN o_d[258]
    DIRECTION OUTPUT ;
    USE SIGNAL ;
    PORT
      LAYER M5 ;
        RECT  46.704 0 46.728 0.192 ;
    END
  END o_d[258]
  PIN o_d[259]
    DIRECTION OUTPUT ;
    USE SIGNAL ;
    PORT
      LAYER M5 ;
        RECT  46.848 0 46.872 0.192 ;
    END
  END o_d[259]
  PIN o_d[25]
    DIRECTION OUTPUT ;
    USE SIGNAL ;
    PORT
      LAYER M5 ;
        RECT  8.592 0 8.616 0.192 ;
    END
  END o_d[25]
  PIN o_d[260]
    DIRECTION OUTPUT ;
    USE SIGNAL ;
    PORT
      LAYER M5 ;
        RECT  46.992 0 47.016 0.192 ;
    END
  END o_d[260]
  PIN o_d[261]
    DIRECTION OUTPUT ;
    USE SIGNAL ;
    PORT
      LAYER M5 ;
        RECT  47.136 0 47.16 0.192 ;
    END
  END o_d[261]
  PIN o_d[262]
    DIRECTION OUTPUT ;
    USE SIGNAL ;
    PORT
      LAYER M5 ;
        RECT  47.28 0 47.304 0.192 ;
    END
  END o_d[262]
  PIN o_d[263]
    DIRECTION OUTPUT ;
    USE SIGNAL ;
    PORT
      LAYER M5 ;
        RECT  47.568 0 47.592 0.192 ;
    END
  END o_d[263]
  PIN o_d[264]
    DIRECTION OUTPUT ;
    USE SIGNAL ;
    PORT
      LAYER M5 ;
        RECT  47.712 0 47.736 0.192 ;
    END
  END o_d[264]
  PIN o_d[265]
    DIRECTION OUTPUT ;
    USE SIGNAL ;
    PORT
      LAYER M5 ;
        RECT  47.856 0 47.88 0.192 ;
    END
  END o_d[265]
  PIN o_d[266]
    DIRECTION OUTPUT ;
    USE SIGNAL ;
    PORT
      LAYER M5 ;
        RECT  48 0 48.024 0.192 ;
    END
  END o_d[266]
  PIN o_d[267]
    DIRECTION OUTPUT ;
    USE SIGNAL ;
    PORT
      LAYER M5 ;
        RECT  48.144 0 48.168 0.192 ;
    END
  END o_d[267]
  PIN o_d[268]
    DIRECTION OUTPUT ;
    USE SIGNAL ;
    PORT
      LAYER M5 ;
        RECT  48.288 0 48.312 0.192 ;
    END
  END o_d[268]
  PIN o_d[269]
    DIRECTION OUTPUT ;
    USE SIGNAL ;
    PORT
      LAYER M5 ;
        RECT  48.432 0 48.456 0.192 ;
    END
  END o_d[269]
  PIN o_d[26]
    DIRECTION OUTPUT ;
    USE SIGNAL ;
    PORT
      LAYER M5 ;
        RECT  8.736 0 8.76 0.192 ;
    END
  END o_d[26]
  PIN o_d[270]
    DIRECTION OUTPUT ;
    USE SIGNAL ;
    PORT
      LAYER M5 ;
        RECT  48.576 0 48.6 0.192 ;
    END
  END o_d[270]
  PIN o_d[271]
    DIRECTION OUTPUT ;
    USE SIGNAL ;
    PORT
      LAYER M5 ;
        RECT  48.72 0 48.744 0.192 ;
    END
  END o_d[271]
  PIN o_d[272]
    DIRECTION OUTPUT ;
    USE SIGNAL ;
    PORT
      LAYER M5 ;
        RECT  49.344 0 49.368 0.192 ;
    END
  END o_d[272]
  PIN o_d[273]
    DIRECTION OUTPUT ;
    USE SIGNAL ;
    PORT
      LAYER M5 ;
        RECT  49.488 0 49.512 0.192 ;
    END
  END o_d[273]
  PIN o_d[274]
    DIRECTION OUTPUT ;
    USE SIGNAL ;
    PORT
      LAYER M5 ;
        RECT  49.632 0 49.656 0.192 ;
    END
  END o_d[274]
  PIN o_d[275]
    DIRECTION OUTPUT ;
    USE SIGNAL ;
    PORT
      LAYER M5 ;
        RECT  49.776 0 49.8 0.192 ;
    END
  END o_d[275]
  PIN o_d[276]
    DIRECTION OUTPUT ;
    USE SIGNAL ;
    PORT
      LAYER M5 ;
        RECT  49.92 0 49.944 0.192 ;
    END
  END o_d[276]
  PIN o_d[277]
    DIRECTION OUTPUT ;
    USE SIGNAL ;
    PORT
      LAYER M5 ;
        RECT  50.064 0 50.088 0.192 ;
    END
  END o_d[277]
  PIN o_d[278]
    DIRECTION OUTPUT ;
    USE SIGNAL ;
    PORT
      LAYER M5 ;
        RECT  50.208 0 50.232 0.192 ;
    END
  END o_d[278]
  PIN o_d[279]
    DIRECTION OUTPUT ;
    USE SIGNAL ;
    PORT
      LAYER M5 ;
        RECT  50.352 0 50.376 0.192 ;
    END
  END o_d[279]
  PIN o_d[27]
    DIRECTION OUTPUT ;
    USE SIGNAL ;
    PORT
      LAYER M5 ;
        RECT  8.88 0 8.904 0.192 ;
    END
  END o_d[27]
  PIN o_d[280]
    DIRECTION OUTPUT ;
    USE SIGNAL ;
    PORT
      LAYER M5 ;
        RECT  50.496 0 50.52 0.192 ;
    END
  END o_d[280]
  PIN o_d[281]
    DIRECTION OUTPUT ;
    USE SIGNAL ;
    PORT
      LAYER M5 ;
        RECT  50.64 0 50.664 0.192 ;
    END
  END o_d[281]
  PIN o_d[282]
    DIRECTION OUTPUT ;
    USE SIGNAL ;
    PORT
      LAYER M5 ;
        RECT  50.784 0 50.808 0.192 ;
    END
  END o_d[282]
  PIN o_d[283]
    DIRECTION OUTPUT ;
    USE SIGNAL ;
    PORT
      LAYER M5 ;
        RECT  50.928 0 50.952 0.192 ;
    END
  END o_d[283]
  PIN o_d[284]
    DIRECTION OUTPUT ;
    USE SIGNAL ;
    PORT
      LAYER M5 ;
        RECT  51.072 0 51.096 0.192 ;
    END
  END o_d[284]
  PIN o_d[285]
    DIRECTION OUTPUT ;
    USE SIGNAL ;
    PORT
      LAYER M5 ;
        RECT  51.216 0 51.24 0.192 ;
    END
  END o_d[285]
  PIN o_d[286]
    DIRECTION OUTPUT ;
    USE SIGNAL ;
    PORT
      LAYER M5 ;
        RECT  51.36 0 51.384 0.192 ;
    END
  END o_d[286]
  PIN o_d[287]
    DIRECTION OUTPUT ;
    USE SIGNAL ;
    PORT
      LAYER M5 ;
        RECT  51.504 0 51.528 0.192 ;
    END
  END o_d[287]
  PIN o_d[288]
    DIRECTION OUTPUT ;
    USE SIGNAL ;
    PORT
      LAYER M5 ;
        RECT  51.648 0 51.672 0.192 ;
    END
  END o_d[288]
  PIN o_d[289]
    DIRECTION OUTPUT ;
    USE SIGNAL ;
    PORT
      LAYER M5 ;
        RECT  51.792 0 51.816 0.192 ;
    END
  END o_d[289]
  PIN o_d[28]
    DIRECTION OUTPUT ;
    USE SIGNAL ;
    PORT
      LAYER M5 ;
        RECT  9.024 0 9.048 0.192 ;
    END
  END o_d[28]
  PIN o_d[290]
    DIRECTION OUTPUT ;
    USE SIGNAL ;
    PORT
      LAYER M5 ;
        RECT  51.936 0 51.96 0.192 ;
    END
  END o_d[290]
  PIN o_d[291]
    DIRECTION OUTPUT ;
    USE SIGNAL ;
    PORT
      LAYER M5 ;
        RECT  52.08 0 52.104 0.192 ;
    END
  END o_d[291]
  PIN o_d[292]
    DIRECTION OUTPUT ;
    USE SIGNAL ;
    PORT
      LAYER M5 ;
        RECT  52.224 0 52.248 0.192 ;
    END
  END o_d[292]
  PIN o_d[293]
    DIRECTION OUTPUT ;
    USE SIGNAL ;
    PORT
      LAYER M5 ;
        RECT  52.368 0 52.392 0.192 ;
    END
  END o_d[293]
  PIN o_d[294]
    DIRECTION OUTPUT ;
    USE SIGNAL ;
    PORT
      LAYER M5 ;
        RECT  52.656 0 52.68 0.192 ;
    END
  END o_d[294]
  PIN o_d[295]
    DIRECTION OUTPUT ;
    USE SIGNAL ;
    PORT
      LAYER M5 ;
        RECT  52.8 0 52.824 0.192 ;
    END
  END o_d[295]
  PIN o_d[296]
    DIRECTION OUTPUT ;
    USE SIGNAL ;
    PORT
      LAYER M5 ;
        RECT  52.944 0 52.968 0.192 ;
    END
  END o_d[296]
  PIN o_d[297]
    DIRECTION OUTPUT ;
    USE SIGNAL ;
    PORT
      LAYER M5 ;
        RECT  53.088 0 53.112 0.192 ;
    END
  END o_d[297]
  PIN o_d[298]
    DIRECTION OUTPUT ;
    USE SIGNAL ;
    PORT
      LAYER M5 ;
        RECT  53.232 0 53.256 0.192 ;
    END
  END o_d[298]
  PIN o_d[299]
    DIRECTION OUTPUT ;
    USE SIGNAL ;
    PORT
      LAYER M5 ;
        RECT  53.376 0 53.4 0.192 ;
    END
  END o_d[299]
  PIN o_d[29]
    DIRECTION OUTPUT ;
    USE SIGNAL ;
    PORT
      LAYER M5 ;
        RECT  9.168 0 9.192 0.192 ;
    END
  END o_d[29]
  PIN o_d[2]
    DIRECTION OUTPUT ;
    USE SIGNAL ;
    PORT
      LAYER M5 ;
        RECT  4.608 0 4.632 0.192 ;
    END
  END o_d[2]
  PIN o_d[300]
    DIRECTION OUTPUT ;
    USE SIGNAL ;
    PORT
      LAYER M5 ;
        RECT  53.52 0 53.544 0.192 ;
    END
  END o_d[300]
  PIN o_d[301]
    DIRECTION OUTPUT ;
    USE SIGNAL ;
    PORT
      LAYER M5 ;
        RECT  53.664 0 53.688 0.192 ;
    END
  END o_d[301]
  PIN o_d[302]
    DIRECTION OUTPUT ;
    USE SIGNAL ;
    PORT
      LAYER M5 ;
        RECT  53.808 0 53.832 0.192 ;
    END
  END o_d[302]
  PIN o_d[303]
    DIRECTION OUTPUT ;
    USE SIGNAL ;
    PORT
      LAYER M5 ;
        RECT  53.952 0 53.976 0.192 ;
    END
  END o_d[303]
  PIN o_d[304]
    DIRECTION OUTPUT ;
    USE SIGNAL ;
    PORT
      LAYER M5 ;
        RECT  54.096 0 54.12 0.192 ;
    END
  END o_d[304]
  PIN o_d[305]
    DIRECTION OUTPUT ;
    USE SIGNAL ;
    PORT
      LAYER M5 ;
        RECT  54.768 0 54.792 0.192 ;
    END
  END o_d[305]
  PIN o_d[306]
    DIRECTION OUTPUT ;
    USE SIGNAL ;
    PORT
      LAYER M5 ;
        RECT  54.912 0 54.936 0.192 ;
    END
  END o_d[306]
  PIN o_d[307]
    DIRECTION OUTPUT ;
    USE SIGNAL ;
    PORT
      LAYER M5 ;
        RECT  55.056 0 55.08 0.192 ;
    END
  END o_d[307]
  PIN o_d[308]
    DIRECTION OUTPUT ;
    USE SIGNAL ;
    PORT
      LAYER M5 ;
        RECT  55.2 0 55.224 0.192 ;
    END
  END o_d[308]
  PIN o_d[309]
    DIRECTION OUTPUT ;
    USE SIGNAL ;
    PORT
      LAYER M5 ;
        RECT  55.344 0 55.368 0.192 ;
    END
  END o_d[309]
  PIN o_d[30]
    DIRECTION OUTPUT ;
    USE SIGNAL ;
    PORT
      LAYER M5 ;
        RECT  9.312 0 9.336 0.192 ;
    END
  END o_d[30]
  PIN o_d[310]
    DIRECTION OUTPUT ;
    USE SIGNAL ;
    PORT
      LAYER M5 ;
        RECT  55.488 0 55.512 0.192 ;
    END
  END o_d[310]
  PIN o_d[311]
    DIRECTION OUTPUT ;
    USE SIGNAL ;
    PORT
      LAYER M5 ;
        RECT  55.632 0 55.656 0.192 ;
    END
  END o_d[311]
  PIN o_d[312]
    DIRECTION OUTPUT ;
    USE SIGNAL ;
    PORT
      LAYER M5 ;
        RECT  55.776 0 55.8 0.192 ;
    END
  END o_d[312]
  PIN o_d[313]
    DIRECTION OUTPUT ;
    USE SIGNAL ;
    PORT
      LAYER M5 ;
        RECT  55.92 0 55.944 0.192 ;
    END
  END o_d[313]
  PIN o_d[314]
    DIRECTION OUTPUT ;
    USE SIGNAL ;
    PORT
      LAYER M5 ;
        RECT  56.064 0 56.088 0.192 ;
    END
  END o_d[314]
  PIN o_d[315]
    DIRECTION OUTPUT ;
    USE SIGNAL ;
    PORT
      LAYER M5 ;
        RECT  56.208 0 56.232 0.192 ;
    END
  END o_d[315]
  PIN o_d[316]
    DIRECTION OUTPUT ;
    USE SIGNAL ;
    PORT
      LAYER M5 ;
        RECT  56.352 0 56.376 0.192 ;
    END
  END o_d[316]
  PIN o_d[317]
    DIRECTION OUTPUT ;
    USE SIGNAL ;
    PORT
      LAYER M5 ;
        RECT  56.496 0 56.52 0.192 ;
    END
  END o_d[317]
  PIN o_d[318]
    DIRECTION OUTPUT ;
    USE SIGNAL ;
    PORT
      LAYER M5 ;
        RECT  56.64 0 56.664 0.192 ;
    END
  END o_d[318]
  PIN o_d[319]
    DIRECTION OUTPUT ;
    USE SIGNAL ;
    PORT
      LAYER M5 ;
        RECT  56.784 0 56.808 0.192 ;
    END
  END o_d[319]
  PIN o_d[31]
    DIRECTION OUTPUT ;
    USE SIGNAL ;
    PORT
      LAYER M5 ;
        RECT  9.456 0 9.48 0.192 ;
    END
  END o_d[31]
  PIN o_d[320]
    DIRECTION OUTPUT ;
    USE SIGNAL ;
    PORT
      LAYER M5 ;
        RECT  56.928 0 56.952 0.192 ;
    END
  END o_d[320]
  PIN o_d[321]
    DIRECTION OUTPUT ;
    USE SIGNAL ;
    PORT
      LAYER M5 ;
        RECT  57.072 0 57.096 0.192 ;
    END
  END o_d[321]
  PIN o_d[322]
    DIRECTION OUTPUT ;
    USE SIGNAL ;
    PORT
      LAYER M5 ;
        RECT  57.216 0 57.24 0.192 ;
    END
  END o_d[322]
  PIN o_d[323]
    DIRECTION OUTPUT ;
    USE SIGNAL ;
    PORT
      LAYER M5 ;
        RECT  57.36 0 57.384 0.192 ;
    END
  END o_d[323]
  PIN o_d[324]
    DIRECTION OUTPUT ;
    USE SIGNAL ;
    PORT
      LAYER M5 ;
        RECT  57.504 0 57.528 0.192 ;
    END
  END o_d[324]
  PIN o_d[325]
    DIRECTION OUTPUT ;
    USE SIGNAL ;
    PORT
      LAYER M5 ;
        RECT  57.792 0 57.816 0.192 ;
    END
  END o_d[325]
  PIN o_d[326]
    DIRECTION OUTPUT ;
    USE SIGNAL ;
    PORT
      LAYER M5 ;
        RECT  57.936 0 57.96 0.192 ;
    END
  END o_d[326]
  PIN o_d[327]
    DIRECTION OUTPUT ;
    USE SIGNAL ;
    PORT
      LAYER M5 ;
        RECT  58.08 0 58.104 0.192 ;
    END
  END o_d[327]
  PIN o_d[328]
    DIRECTION OUTPUT ;
    USE SIGNAL ;
    PORT
      LAYER M5 ;
        RECT  58.224 0 58.248 0.192 ;
    END
  END o_d[328]
  PIN o_d[329]
    DIRECTION OUTPUT ;
    USE SIGNAL ;
    PORT
      LAYER M5 ;
        RECT  58.368 0 58.392 0.192 ;
    END
  END o_d[329]
  PIN o_d[32]
    DIRECTION OUTPUT ;
    USE SIGNAL ;
    PORT
      LAYER M5 ;
        RECT  9.6 0 9.624 0.192 ;
    END
  END o_d[32]
  PIN o_d[330]
    DIRECTION OUTPUT ;
    USE SIGNAL ;
    PORT
      LAYER M5 ;
        RECT  58.512 0 58.536 0.192 ;
    END
  END o_d[330]
  PIN o_d[331]
    DIRECTION OUTPUT ;
    USE SIGNAL ;
    PORT
      LAYER M5 ;
        RECT  58.656 0 58.68 0.192 ;
    END
  END o_d[331]
  PIN o_d[332]
    DIRECTION OUTPUT ;
    USE SIGNAL ;
    PORT
      LAYER M5 ;
        RECT  58.8 0 58.824 0.192 ;
    END
  END o_d[332]
  PIN o_d[333]
    DIRECTION OUTPUT ;
    USE SIGNAL ;
    PORT
      LAYER M5 ;
        RECT  58.944 0 58.968 0.192 ;
    END
  END o_d[333]
  PIN o_d[334]
    DIRECTION OUTPUT ;
    USE SIGNAL ;
    PORT
      LAYER M5 ;
        RECT  59.088 0 59.112 0.192 ;
    END
  END o_d[334]
  PIN o_d[335]
    DIRECTION OUTPUT ;
    USE SIGNAL ;
    PORT
      LAYER M5 ;
        RECT  59.232 0 59.256 0.192 ;
    END
  END o_d[335]
  PIN o_d[336]
    DIRECTION OUTPUT ;
    USE SIGNAL ;
    PORT
      LAYER M5 ;
        RECT  59.376 0 59.4 0.192 ;
    END
  END o_d[336]
  PIN o_d[337]
    DIRECTION OUTPUT ;
    USE SIGNAL ;
    PORT
      LAYER M5 ;
        RECT  59.52 0 59.544 0.192 ;
    END
  END o_d[337]
  PIN o_d[338]
    DIRECTION OUTPUT ;
    USE SIGNAL ;
    PORT
      LAYER M5 ;
        RECT  60.144 0 60.168 0.192 ;
    END
  END o_d[338]
  PIN o_d[339]
    DIRECTION OUTPUT ;
    USE SIGNAL ;
    PORT
      LAYER M5 ;
        RECT  60.288 0 60.312 0.192 ;
    END
  END o_d[339]
  PIN o_d[33]
    DIRECTION OUTPUT ;
    USE SIGNAL ;
    PORT
      LAYER M5 ;
        RECT  9.744 0 9.768 0.192 ;
    END
  END o_d[33]
  PIN o_d[340]
    DIRECTION OUTPUT ;
    USE SIGNAL ;
    PORT
      LAYER M5 ;
        RECT  60.432 0 60.456 0.192 ;
    END
  END o_d[340]
  PIN o_d[341]
    DIRECTION OUTPUT ;
    USE SIGNAL ;
    PORT
      LAYER M5 ;
        RECT  60.576 0 60.6 0.192 ;
    END
  END o_d[341]
  PIN o_d[342]
    DIRECTION OUTPUT ;
    USE SIGNAL ;
    PORT
      LAYER M5 ;
        RECT  60.72 0 60.744 0.192 ;
    END
  END o_d[342]
  PIN o_d[343]
    DIRECTION OUTPUT ;
    USE SIGNAL ;
    PORT
      LAYER M5 ;
        RECT  60.864 0 60.888 0.192 ;
    END
  END o_d[343]
  PIN o_d[344]
    DIRECTION OUTPUT ;
    USE SIGNAL ;
    PORT
      LAYER M5 ;
        RECT  61.008 0 61.032 0.192 ;
    END
  END o_d[344]
  PIN o_d[345]
    DIRECTION OUTPUT ;
    USE SIGNAL ;
    PORT
      LAYER M5 ;
        RECT  61.152 0 61.176 0.192 ;
    END
  END o_d[345]
  PIN o_d[346]
    DIRECTION OUTPUT ;
    USE SIGNAL ;
    PORT
      LAYER M5 ;
        RECT  61.296 0 61.32 0.192 ;
    END
  END o_d[346]
  PIN o_d[347]
    DIRECTION OUTPUT ;
    USE SIGNAL ;
    PORT
      LAYER M5 ;
        RECT  61.44 0 61.464 0.192 ;
    END
  END o_d[347]
  PIN o_d[348]
    DIRECTION OUTPUT ;
    USE SIGNAL ;
    PORT
      LAYER M5 ;
        RECT  61.584 0 61.608 0.192 ;
    END
  END o_d[348]
  PIN o_d[349]
    DIRECTION OUTPUT ;
    USE SIGNAL ;
    PORT
      LAYER M5 ;
        RECT  61.728 0 61.752 0.192 ;
    END
  END o_d[349]
  PIN o_d[34]
    DIRECTION OUTPUT ;
    USE SIGNAL ;
    PORT
      LAYER M5 ;
        RECT  9.888 0 9.912 0.192 ;
    END
  END o_d[34]
  PIN o_d[350]
    DIRECTION OUTPUT ;
    USE SIGNAL ;
    PORT
      LAYER M5 ;
        RECT  61.872 0 61.896 0.192 ;
    END
  END o_d[350]
  PIN o_d[351]
    DIRECTION OUTPUT ;
    USE SIGNAL ;
    PORT
      LAYER M5 ;
        RECT  62.016 0 62.04 0.192 ;
    END
  END o_d[351]
  PIN o_d[352]
    DIRECTION OUTPUT ;
    USE SIGNAL ;
    PORT
      LAYER M5 ;
        RECT  62.16 0 62.184 0.192 ;
    END
  END o_d[352]
  PIN o_d[353]
    DIRECTION OUTPUT ;
    USE SIGNAL ;
    PORT
      LAYER M5 ;
        RECT  62.304 0 62.328 0.192 ;
    END
  END o_d[353]
  PIN o_d[354]
    DIRECTION OUTPUT ;
    USE SIGNAL ;
    PORT
      LAYER M5 ;
        RECT  62.448 0 62.472 0.192 ;
    END
  END o_d[354]
  PIN o_d[355]
    DIRECTION OUTPUT ;
    USE SIGNAL ;
    PORT
      LAYER M5 ;
        RECT  62.592 0 62.616 0.192 ;
    END
  END o_d[355]
  PIN o_d[356]
    DIRECTION OUTPUT ;
    USE SIGNAL ;
    PORT
      LAYER M5 ;
        RECT  62.88 0 62.904 0.192 ;
    END
  END o_d[356]
  PIN o_d[357]
    DIRECTION OUTPUT ;
    USE SIGNAL ;
    PORT
      LAYER M5 ;
        RECT  63.024 0 63.048 0.192 ;
    END
  END o_d[357]
  PIN o_d[358]
    DIRECTION OUTPUT ;
    USE SIGNAL ;
    PORT
      LAYER M5 ;
        RECT  63.168 0 63.192 0.192 ;
    END
  END o_d[358]
  PIN o_d[359]
    DIRECTION OUTPUT ;
    USE SIGNAL ;
    PORT
      LAYER M5 ;
        RECT  63.312 0 63.336 0.192 ;
    END
  END o_d[359]
  PIN o_d[35]
    DIRECTION OUTPUT ;
    USE SIGNAL ;
    PORT
      LAYER M5 ;
        RECT  10.032 0 10.056 0.192 ;
    END
  END o_d[35]
  PIN o_d[360]
    DIRECTION OUTPUT ;
    USE SIGNAL ;
    PORT
      LAYER M5 ;
        RECT  63.456 0 63.48 0.192 ;
    END
  END o_d[360]
  PIN o_d[361]
    DIRECTION OUTPUT ;
    USE SIGNAL ;
    PORT
      LAYER M5 ;
        RECT  63.6 0 63.624 0.192 ;
    END
  END o_d[361]
  PIN o_d[362]
    DIRECTION OUTPUT ;
    USE SIGNAL ;
    PORT
      LAYER M5 ;
        RECT  63.744 0 63.768 0.192 ;
    END
  END o_d[362]
  PIN o_d[363]
    DIRECTION OUTPUT ;
    USE SIGNAL ;
    PORT
      LAYER M5 ;
        RECT  63.888 0 63.912 0.192 ;
    END
  END o_d[363]
  PIN o_d[364]
    DIRECTION OUTPUT ;
    USE SIGNAL ;
    PORT
      LAYER M5 ;
        RECT  64.032 0 64.056 0.192 ;
    END
  END o_d[364]
  PIN o_d[365]
    DIRECTION OUTPUT ;
    USE SIGNAL ;
    PORT
      LAYER M5 ;
        RECT  64.176 0 64.2 0.192 ;
    END
  END o_d[365]
  PIN o_d[366]
    DIRECTION OUTPUT ;
    USE SIGNAL ;
    PORT
      LAYER M5 ;
        RECT  64.32 0 64.344 0.192 ;
    END
  END o_d[366]
  PIN o_d[367]
    DIRECTION OUTPUT ;
    USE SIGNAL ;
    PORT
      LAYER M5 ;
        RECT  64.464 0 64.488 0.192 ;
    END
  END o_d[367]
  PIN o_d[368]
    DIRECTION OUTPUT ;
    USE SIGNAL ;
    PORT
      LAYER M5 ;
        RECT  64.608 0 64.632 0.192 ;
    END
  END o_d[368]
  PIN o_d[369]
    DIRECTION OUTPUT ;
    USE SIGNAL ;
    PORT
      LAYER M5 ;
        RECT  64.752 0 64.776 0.192 ;
    END
  END o_d[369]
  PIN o_d[36]
    DIRECTION OUTPUT ;
    USE SIGNAL ;
    PORT
      LAYER M5 ;
        RECT  10.176 0 10.2 0.192 ;
    END
  END o_d[36]
  PIN o_d[370]
    DIRECTION OUTPUT ;
    USE SIGNAL ;
    PORT
      LAYER M5 ;
        RECT  64.896 0 64.92 0.192 ;
    END
  END o_d[370]
  PIN o_d[371]
    DIRECTION OUTPUT ;
    USE SIGNAL ;
    PORT
      LAYER M5 ;
        RECT  65.568 0 65.592 0.192 ;
    END
  END o_d[371]
  PIN o_d[372]
    DIRECTION OUTPUT ;
    USE SIGNAL ;
    PORT
      LAYER M5 ;
        RECT  65.712 0 65.736 0.192 ;
    END
  END o_d[372]
  PIN o_d[373]
    DIRECTION OUTPUT ;
    USE SIGNAL ;
    PORT
      LAYER M5 ;
        RECT  65.856 0 65.88 0.192 ;
    END
  END o_d[373]
  PIN o_d[374]
    DIRECTION OUTPUT ;
    USE SIGNAL ;
    PORT
      LAYER M5 ;
        RECT  66 0 66.024 0.192 ;
    END
  END o_d[374]
  PIN o_d[375]
    DIRECTION OUTPUT ;
    USE SIGNAL ;
    PORT
      LAYER M5 ;
        RECT  66.144 0 66.168 0.192 ;
    END
  END o_d[375]
  PIN o_d[376]
    DIRECTION OUTPUT ;
    USE SIGNAL ;
    PORT
      LAYER M5 ;
        RECT  66.288 0 66.312 0.192 ;
    END
  END o_d[376]
  PIN o_d[377]
    DIRECTION OUTPUT ;
    USE SIGNAL ;
    PORT
      LAYER M5 ;
        RECT  66.432 0 66.456 0.192 ;
    END
  END o_d[377]
  PIN o_d[378]
    DIRECTION OUTPUT ;
    USE SIGNAL ;
    PORT
      LAYER M5 ;
        RECT  66.576 0 66.6 0.192 ;
    END
  END o_d[378]
  PIN o_d[379]
    DIRECTION OUTPUT ;
    USE SIGNAL ;
    PORT
      LAYER M5 ;
        RECT  66.72 0 66.744 0.192 ;
    END
  END o_d[379]
  PIN o_d[37]
    DIRECTION OUTPUT ;
    USE SIGNAL ;
    PORT
      LAYER M5 ;
        RECT  10.32 0 10.344 0.192 ;
    END
  END o_d[37]
  PIN o_d[380]
    DIRECTION OUTPUT ;
    USE SIGNAL ;
    PORT
      LAYER M5 ;
        RECT  66.864 0 66.888 0.192 ;
    END
  END o_d[380]
  PIN o_d[381]
    DIRECTION OUTPUT ;
    USE SIGNAL ;
    PORT
      LAYER M5 ;
        RECT  67.008 0 67.032 0.192 ;
    END
  END o_d[381]
  PIN o_d[382]
    DIRECTION OUTPUT ;
    USE SIGNAL ;
    PORT
      LAYER M5 ;
        RECT  67.152 0 67.176 0.192 ;
    END
  END o_d[382]
  PIN o_d[383]
    DIRECTION OUTPUT ;
    USE SIGNAL ;
    PORT
      LAYER M5 ;
        RECT  67.296 0 67.32 0.192 ;
    END
  END o_d[383]
  PIN o_d[384]
    DIRECTION OUTPUT ;
    USE SIGNAL ;
    PORT
      LAYER M5 ;
        RECT  67.44 0 67.464 0.192 ;
    END
  END o_d[384]
  PIN o_d[385]
    DIRECTION OUTPUT ;
    USE SIGNAL ;
    PORT
      LAYER M5 ;
        RECT  67.584 0 67.608 0.192 ;
    END
  END o_d[385]
  PIN o_d[386]
    DIRECTION OUTPUT ;
    USE SIGNAL ;
    PORT
      LAYER M5 ;
        RECT  67.728 0 67.752 0.192 ;
    END
  END o_d[386]
  PIN o_d[387]
    DIRECTION OUTPUT ;
    USE SIGNAL ;
    PORT
      LAYER M5 ;
        RECT  68.016 0 68.04 0.192 ;
    END
  END o_d[387]
  PIN o_d[388]
    DIRECTION OUTPUT ;
    USE SIGNAL ;
    PORT
      LAYER M5 ;
        RECT  68.16 0 68.184 0.192 ;
    END
  END o_d[388]
  PIN o_d[389]
    DIRECTION OUTPUT ;
    USE SIGNAL ;
    PORT
      LAYER M5 ;
        RECT  68.304 0 68.328 0.192 ;
    END
  END o_d[389]
  PIN o_d[38]
    DIRECTION OUTPUT ;
    USE SIGNAL ;
    PORT
      LAYER M5 ;
        RECT  10.464 0 10.488 0.192 ;
    END
  END o_d[38]
  PIN o_d[390]
    DIRECTION OUTPUT ;
    USE SIGNAL ;
    PORT
      LAYER M5 ;
        RECT  68.448 0 68.472 0.192 ;
    END
  END o_d[390]
  PIN o_d[391]
    DIRECTION OUTPUT ;
    USE SIGNAL ;
    PORT
      LAYER M5 ;
        RECT  68.592 0 68.616 0.192 ;
    END
  END o_d[391]
  PIN o_d[392]
    DIRECTION OUTPUT ;
    USE SIGNAL ;
    PORT
      LAYER M5 ;
        RECT  68.736 0 68.76 0.192 ;
    END
  END o_d[392]
  PIN o_d[393]
    DIRECTION OUTPUT ;
    USE SIGNAL ;
    PORT
      LAYER M5 ;
        RECT  68.88 0 68.904 0.192 ;
    END
  END o_d[393]
  PIN o_d[394]
    DIRECTION OUTPUT ;
    USE SIGNAL ;
    PORT
      LAYER M5 ;
        RECT  69.024 0 69.048 0.192 ;
    END
  END o_d[394]
  PIN o_d[395]
    DIRECTION OUTPUT ;
    USE SIGNAL ;
    PORT
      LAYER M5 ;
        RECT  69.168 0 69.192 0.192 ;
    END
  END o_d[395]
  PIN o_d[396]
    DIRECTION OUTPUT ;
    USE SIGNAL ;
    PORT
      LAYER M5 ;
        RECT  69.312 0 69.336 0.192 ;
    END
  END o_d[396]
  PIN o_d[397]
    DIRECTION OUTPUT ;
    USE SIGNAL ;
    PORT
      LAYER M5 ;
        RECT  69.456 0 69.48 0.192 ;
    END
  END o_d[397]
  PIN o_d[398]
    DIRECTION OUTPUT ;
    USE SIGNAL ;
    PORT
      LAYER M5 ;
        RECT  69.6 0 69.624 0.192 ;
    END
  END o_d[398]
  PIN o_d[399]
    DIRECTION OUTPUT ;
    USE SIGNAL ;
    PORT
      LAYER M5 ;
        RECT  69.744 0 69.768 0.192 ;
    END
  END o_d[399]
  PIN o_d[39]
    DIRECTION OUTPUT ;
    USE SIGNAL ;
    PORT
      LAYER M5 ;
        RECT  10.608 0 10.632 0.192 ;
    END
  END o_d[39]
  PIN o_d[3]
    DIRECTION OUTPUT ;
    USE SIGNAL ;
    PORT
      LAYER M5 ;
        RECT  4.752 0 4.776 0.192 ;
    END
  END o_d[3]
  PIN o_d[400]
    DIRECTION OUTPUT ;
    USE SIGNAL ;
    PORT
      LAYER M5 ;
        RECT  69.888 0 69.912 0.192 ;
    END
  END o_d[400]
  PIN o_d[401]
    DIRECTION OUTPUT ;
    USE SIGNAL ;
    PORT
      LAYER M5 ;
        RECT  70.032 0 70.056 0.192 ;
    END
  END o_d[401]
  PIN o_d[402]
    DIRECTION OUTPUT ;
    USE SIGNAL ;
    PORT
      LAYER M5 ;
        RECT  70.176 0 70.2 0.192 ;
    END
  END o_d[402]
  PIN o_d[403]
    DIRECTION OUTPUT ;
    USE SIGNAL ;
    PORT
      LAYER M5 ;
        RECT  70.32 0 70.344 0.192 ;
    END
  END o_d[403]
  PIN o_d[404]
    DIRECTION OUTPUT ;
    USE SIGNAL ;
    PORT
      LAYER M5 ;
        RECT  70.944 0 70.968 0.192 ;
    END
  END o_d[404]
  PIN o_d[405]
    DIRECTION OUTPUT ;
    USE SIGNAL ;
    PORT
      LAYER M5 ;
        RECT  71.088 0 71.112 0.192 ;
    END
  END o_d[405]
  PIN o_d[406]
    DIRECTION OUTPUT ;
    USE SIGNAL ;
    PORT
      LAYER M5 ;
        RECT  71.232 0 71.256 0.192 ;
    END
  END o_d[406]
  PIN o_d[407]
    DIRECTION OUTPUT ;
    USE SIGNAL ;
    PORT
      LAYER M5 ;
        RECT  71.376 0 71.4 0.192 ;
    END
  END o_d[407]
  PIN o_d[408]
    DIRECTION OUTPUT ;
    USE SIGNAL ;
    PORT
      LAYER M5 ;
        RECT  71.52 0 71.544 0.192 ;
    END
  END o_d[408]
  PIN o_d[409]
    DIRECTION OUTPUT ;
    USE SIGNAL ;
    PORT
      LAYER M5 ;
        RECT  71.664 0 71.688 0.192 ;
    END
  END o_d[409]
  PIN o_d[40]
    DIRECTION OUTPUT ;
    USE SIGNAL ;
    PORT
      LAYER M5 ;
        RECT  10.752 0 10.776 0.192 ;
    END
  END o_d[40]
  PIN o_d[410]
    DIRECTION OUTPUT ;
    USE SIGNAL ;
    PORT
      LAYER M5 ;
        RECT  71.808 0 71.832 0.192 ;
    END
  END o_d[410]
  PIN o_d[411]
    DIRECTION OUTPUT ;
    USE SIGNAL ;
    PORT
      LAYER M5 ;
        RECT  71.952 0 71.976 0.192 ;
    END
  END o_d[411]
  PIN o_d[412]
    DIRECTION OUTPUT ;
    USE SIGNAL ;
    PORT
      LAYER M5 ;
        RECT  72.096 0 72.12 0.192 ;
    END
  END o_d[412]
  PIN o_d[413]
    DIRECTION OUTPUT ;
    USE SIGNAL ;
    PORT
      LAYER M5 ;
        RECT  72.24 0 72.264 0.192 ;
    END
  END o_d[413]
  PIN o_d[414]
    DIRECTION OUTPUT ;
    USE SIGNAL ;
    PORT
      LAYER M5 ;
        RECT  72.384 0 72.408 0.192 ;
    END
  END o_d[414]
  PIN o_d[415]
    DIRECTION OUTPUT ;
    USE SIGNAL ;
    PORT
      LAYER M5 ;
        RECT  72.528 0 72.552 0.192 ;
    END
  END o_d[415]
  PIN o_d[416]
    DIRECTION OUTPUT ;
    USE SIGNAL ;
    PORT
      LAYER M5 ;
        RECT  72.672 0 72.696 0.192 ;
    END
  END o_d[416]
  PIN o_d[417]
    DIRECTION OUTPUT ;
    USE SIGNAL ;
    PORT
      LAYER M5 ;
        RECT  72.816 0 72.84 0.192 ;
    END
  END o_d[417]
  PIN o_d[418]
    DIRECTION OUTPUT ;
    USE SIGNAL ;
    PORT
      LAYER M5 ;
        RECT  73.104 0 73.128 0.192 ;
    END
  END o_d[418]
  PIN o_d[419]
    DIRECTION OUTPUT ;
    USE SIGNAL ;
    PORT
      LAYER M5 ;
        RECT  73.248 0 73.272 0.192 ;
    END
  END o_d[419]
  PIN o_d[41]
    DIRECTION OUTPUT ;
    USE SIGNAL ;
    PORT
      LAYER M5 ;
        RECT  10.896 0 10.92 0.192 ;
    END
  END o_d[41]
  PIN o_d[420]
    DIRECTION OUTPUT ;
    USE SIGNAL ;
    PORT
      LAYER M5 ;
        RECT  73.392 0 73.416 0.192 ;
    END
  END o_d[420]
  PIN o_d[421]
    DIRECTION OUTPUT ;
    USE SIGNAL ;
    PORT
      LAYER M5 ;
        RECT  73.536 0 73.56 0.192 ;
    END
  END o_d[421]
  PIN o_d[422]
    DIRECTION OUTPUT ;
    USE SIGNAL ;
    PORT
      LAYER M5 ;
        RECT  73.68 0 73.704 0.192 ;
    END
  END o_d[422]
  PIN o_d[423]
    DIRECTION OUTPUT ;
    USE SIGNAL ;
    PORT
      LAYER M5 ;
        RECT  73.824 0 73.848 0.192 ;
    END
  END o_d[423]
  PIN o_d[424]
    DIRECTION OUTPUT ;
    USE SIGNAL ;
    PORT
      LAYER M5 ;
        RECT  73.968 0 73.992 0.192 ;
    END
  END o_d[424]
  PIN o_d[425]
    DIRECTION OUTPUT ;
    USE SIGNAL ;
    PORT
      LAYER M5 ;
        RECT  74.112 0 74.136 0.192 ;
    END
  END o_d[425]
  PIN o_d[426]
    DIRECTION OUTPUT ;
    USE SIGNAL ;
    PORT
      LAYER M5 ;
        RECT  74.256 0 74.28 0.192 ;
    END
  END o_d[426]
  PIN o_d[427]
    DIRECTION OUTPUT ;
    USE SIGNAL ;
    PORT
      LAYER M5 ;
        RECT  74.4 0 74.424 0.192 ;
    END
  END o_d[427]
  PIN o_d[428]
    DIRECTION OUTPUT ;
    USE SIGNAL ;
    PORT
      LAYER M5 ;
        RECT  74.544 0 74.568 0.192 ;
    END
  END o_d[428]
  PIN o_d[429]
    DIRECTION OUTPUT ;
    USE SIGNAL ;
    PORT
      LAYER M5 ;
        RECT  74.688 0 74.712 0.192 ;
    END
  END o_d[429]
  PIN o_d[42]
    DIRECTION OUTPUT ;
    USE SIGNAL ;
    PORT
      LAYER M5 ;
        RECT  11.568 0 11.592 0.192 ;
    END
  END o_d[42]
  PIN o_d[430]
    DIRECTION OUTPUT ;
    USE SIGNAL ;
    PORT
      LAYER M5 ;
        RECT  74.832 0 74.856 0.192 ;
    END
  END o_d[430]
  PIN o_d[431]
    DIRECTION OUTPUT ;
    USE SIGNAL ;
    PORT
      LAYER M5 ;
        RECT  74.976 0 75 0.192 ;
    END
  END o_d[431]
  PIN o_d[432]
    DIRECTION OUTPUT ;
    USE SIGNAL ;
    PORT
      LAYER M5 ;
        RECT  75.12 0 75.144 0.192 ;
    END
  END o_d[432]
  PIN o_d[433]
    DIRECTION OUTPUT ;
    USE SIGNAL ;
    PORT
      LAYER M5 ;
        RECT  75.264 0 75.288 0.192 ;
    END
  END o_d[433]
  PIN o_d[434]
    DIRECTION OUTPUT ;
    USE SIGNAL ;
    PORT
      LAYER M5 ;
        RECT  75.408 0 75.432 0.192 ;
    END
  END o_d[434]
  PIN o_d[435]
    DIRECTION OUTPUT ;
    USE SIGNAL ;
    PORT
      LAYER M5 ;
        RECT  75.552 0 75.576 0.192 ;
    END
  END o_d[435]
  PIN o_d[436]
    DIRECTION OUTPUT ;
    USE SIGNAL ;
    PORT
      LAYER M5 ;
        RECT  75.696 0 75.72 0.192 ;
    END
  END o_d[436]
  PIN o_d[437]
    DIRECTION OUTPUT ;
    USE SIGNAL ;
    PORT
      LAYER M5 ;
        RECT  76.368 0 76.392 0.192 ;
    END
  END o_d[437]
  PIN o_d[438]
    DIRECTION OUTPUT ;
    USE SIGNAL ;
    PORT
      LAYER M5 ;
        RECT  76.512 0 76.536 0.192 ;
    END
  END o_d[438]
  PIN o_d[439]
    DIRECTION OUTPUT ;
    USE SIGNAL ;
    PORT
      LAYER M5 ;
        RECT  76.656 0 76.68 0.192 ;
    END
  END o_d[439]
  PIN o_d[43]
    DIRECTION OUTPUT ;
    USE SIGNAL ;
    PORT
      LAYER M5 ;
        RECT  11.712 0 11.736 0.192 ;
    END
  END o_d[43]
  PIN o_d[440]
    DIRECTION OUTPUT ;
    USE SIGNAL ;
    PORT
      LAYER M5 ;
        RECT  76.8 0 76.824 0.192 ;
    END
  END o_d[440]
  PIN o_d[441]
    DIRECTION OUTPUT ;
    USE SIGNAL ;
    PORT
      LAYER M5 ;
        RECT  76.944 0 76.968 0.192 ;
    END
  END o_d[441]
  PIN o_d[442]
    DIRECTION OUTPUT ;
    USE SIGNAL ;
    PORT
      LAYER M5 ;
        RECT  77.088 0 77.112 0.192 ;
    END
  END o_d[442]
  PIN o_d[443]
    DIRECTION OUTPUT ;
    USE SIGNAL ;
    PORT
      LAYER M5 ;
        RECT  77.232 0 77.256 0.192 ;
    END
  END o_d[443]
  PIN o_d[444]
    DIRECTION OUTPUT ;
    USE SIGNAL ;
    PORT
      LAYER M5 ;
        RECT  77.376 0 77.4 0.192 ;
    END
  END o_d[444]
  PIN o_d[445]
    DIRECTION OUTPUT ;
    USE SIGNAL ;
    PORT
      LAYER M5 ;
        RECT  77.52 0 77.544 0.192 ;
    END
  END o_d[445]
  PIN o_d[446]
    DIRECTION OUTPUT ;
    USE SIGNAL ;
    PORT
      LAYER M5 ;
        RECT  77.664 0 77.688 0.192 ;
    END
  END o_d[446]
  PIN o_d[447]
    DIRECTION OUTPUT ;
    USE SIGNAL ;
    PORT
      LAYER M5 ;
        RECT  77.808 0 77.832 0.192 ;
    END
  END o_d[447]
  PIN o_d[448]
    DIRECTION OUTPUT ;
    USE SIGNAL ;
    PORT
      LAYER M5 ;
        RECT  77.952 0 77.976 0.192 ;
    END
  END o_d[448]
  PIN o_d[449]
    DIRECTION OUTPUT ;
    USE SIGNAL ;
    PORT
      LAYER M5 ;
        RECT  78.24 0 78.264 0.192 ;
    END
  END o_d[449]
  PIN o_d[44]
    DIRECTION OUTPUT ;
    USE SIGNAL ;
    PORT
      LAYER M5 ;
        RECT  11.856 0 11.88 0.192 ;
    END
  END o_d[44]
  PIN o_d[450]
    DIRECTION OUTPUT ;
    USE SIGNAL ;
    PORT
      LAYER M5 ;
        RECT  78.384 0 78.408 0.192 ;
    END
  END o_d[450]
  PIN o_d[451]
    DIRECTION OUTPUT ;
    USE SIGNAL ;
    PORT
      LAYER M5 ;
        RECT  78.528 0 78.552 0.192 ;
    END
  END o_d[451]
  PIN o_d[452]
    DIRECTION OUTPUT ;
    USE SIGNAL ;
    PORT
      LAYER M5 ;
        RECT  78.672 0 78.696 0.192 ;
    END
  END o_d[452]
  PIN o_d[453]
    DIRECTION OUTPUT ;
    USE SIGNAL ;
    PORT
      LAYER M5 ;
        RECT  78.816 0 78.84 0.192 ;
    END
  END o_d[453]
  PIN o_d[454]
    DIRECTION OUTPUT ;
    USE SIGNAL ;
    PORT
      LAYER M5 ;
        RECT  78.96 0 78.984 0.192 ;
    END
  END o_d[454]
  PIN o_d[455]
    DIRECTION OUTPUT ;
    USE SIGNAL ;
    PORT
      LAYER M5 ;
        RECT  79.104 0 79.128 0.192 ;
    END
  END o_d[455]
  PIN o_d[456]
    DIRECTION OUTPUT ;
    USE SIGNAL ;
    PORT
      LAYER M5 ;
        RECT  79.248 0 79.272 0.192 ;
    END
  END o_d[456]
  PIN o_d[457]
    DIRECTION OUTPUT ;
    USE SIGNAL ;
    PORT
      LAYER M5 ;
        RECT  79.392 0 79.416 0.192 ;
    END
  END o_d[457]
  PIN o_d[458]
    DIRECTION OUTPUT ;
    USE SIGNAL ;
    PORT
      LAYER M5 ;
        RECT  79.536 0 79.56 0.192 ;
    END
  END o_d[458]
  PIN o_d[459]
    DIRECTION OUTPUT ;
    USE SIGNAL ;
    PORT
      LAYER M5 ;
        RECT  79.68 0 79.704 0.192 ;
    END
  END o_d[459]
  PIN o_d[45]
    DIRECTION OUTPUT ;
    USE SIGNAL ;
    PORT
      LAYER M5 ;
        RECT  12 0 12.024 0.192 ;
    END
  END o_d[45]
  PIN o_d[460]
    DIRECTION OUTPUT ;
    USE SIGNAL ;
    PORT
      LAYER M5 ;
        RECT  79.824 0 79.848 0.192 ;
    END
  END o_d[460]
  PIN o_d[461]
    DIRECTION OUTPUT ;
    USE SIGNAL ;
    PORT
      LAYER M5 ;
        RECT  79.968 0 79.992 0.192 ;
    END
  END o_d[461]
  PIN o_d[462]
    DIRECTION OUTPUT ;
    USE SIGNAL ;
    PORT
      LAYER M5 ;
        RECT  80.112 0 80.136 0.192 ;
    END
  END o_d[462]
  PIN o_d[463]
    DIRECTION OUTPUT ;
    USE SIGNAL ;
    PORT
      LAYER M5 ;
        RECT  80.256 0 80.28 0.192 ;
    END
  END o_d[463]
  PIN o_d[464]
    DIRECTION OUTPUT ;
    USE SIGNAL ;
    PORT
      LAYER M5 ;
        RECT  80.4 0 80.424 0.192 ;
    END
  END o_d[464]
  PIN o_d[465]
    DIRECTION OUTPUT ;
    USE SIGNAL ;
    PORT
      LAYER M5 ;
        RECT  80.544 0 80.568 0.192 ;
    END
  END o_d[465]
  PIN o_d[466]
    DIRECTION OUTPUT ;
    USE SIGNAL ;
    PORT
      LAYER M5 ;
        RECT  80.688 0 80.712 0.192 ;
    END
  END o_d[466]
  PIN o_d[467]
    DIRECTION OUTPUT ;
    USE SIGNAL ;
    PORT
      LAYER M5 ;
        RECT  80.832 0 80.856 0.192 ;
    END
  END o_d[467]
  PIN o_d[468]
    DIRECTION OUTPUT ;
    USE SIGNAL ;
    PORT
      LAYER M5 ;
        RECT  80.976 0 81 0.192 ;
    END
  END o_d[468]
  PIN o_d[469]
    DIRECTION OUTPUT ;
    USE SIGNAL ;
    PORT
      LAYER M5 ;
        RECT  81.12 0 81.144 0.192 ;
    END
  END o_d[469]
  PIN o_d[46]
    DIRECTION OUTPUT ;
    USE SIGNAL ;
    PORT
      LAYER M5 ;
        RECT  12.288 0 12.312 0.192 ;
    END
  END o_d[46]
  PIN o_d[470]
    DIRECTION OUTPUT ;
    USE SIGNAL ;
    PORT
      LAYER M5 ;
        RECT  81.744 0 81.768 0.192 ;
    END
  END o_d[470]
  PIN o_d[471]
    DIRECTION OUTPUT ;
    USE SIGNAL ;
    PORT
      LAYER M5 ;
        RECT  81.888 0 81.912 0.192 ;
    END
  END o_d[471]
  PIN o_d[472]
    DIRECTION OUTPUT ;
    USE SIGNAL ;
    PORT
      LAYER M5 ;
        RECT  82.032 0 82.056 0.192 ;
    END
  END o_d[472]
  PIN o_d[473]
    DIRECTION OUTPUT ;
    USE SIGNAL ;
    PORT
      LAYER M5 ;
        RECT  82.176 0 82.2 0.192 ;
    END
  END o_d[473]
  PIN o_d[474]
    DIRECTION OUTPUT ;
    USE SIGNAL ;
    PORT
      LAYER M5 ;
        RECT  82.32 0 82.344 0.192 ;
    END
  END o_d[474]
  PIN o_d[475]
    DIRECTION OUTPUT ;
    USE SIGNAL ;
    PORT
      LAYER M5 ;
        RECT  82.464 0 82.488 0.192 ;
    END
  END o_d[475]
  PIN o_d[476]
    DIRECTION OUTPUT ;
    USE SIGNAL ;
    PORT
      LAYER M5 ;
        RECT  82.608 0 82.632 0.192 ;
    END
  END o_d[476]
  PIN o_d[477]
    DIRECTION OUTPUT ;
    USE SIGNAL ;
    PORT
      LAYER M5 ;
        RECT  82.752 0 82.776 0.192 ;
    END
  END o_d[477]
  PIN o_d[478]
    DIRECTION OUTPUT ;
    USE SIGNAL ;
    PORT
      LAYER M5 ;
        RECT  82.896 0 82.92 0.192 ;
    END
  END o_d[478]
  PIN o_d[479]
    DIRECTION OUTPUT ;
    USE SIGNAL ;
    PORT
      LAYER M5 ;
        RECT  83.04 0 83.064 0.192 ;
    END
  END o_d[479]
  PIN o_d[47]
    DIRECTION OUTPUT ;
    USE SIGNAL ;
    PORT
      LAYER M5 ;
        RECT  12.432 0 12.456 0.192 ;
    END
  END o_d[47]
  PIN o_d[480]
    DIRECTION OUTPUT ;
    USE SIGNAL ;
    PORT
      LAYER M5 ;
        RECT  83.328 0 83.352 0.192 ;
    END
  END o_d[480]
  PIN o_d[481]
    DIRECTION OUTPUT ;
    USE SIGNAL ;
    PORT
      LAYER M5 ;
        RECT  83.472 0 83.496 0.192 ;
    END
  END o_d[481]
  PIN o_d[482]
    DIRECTION OUTPUT ;
    USE SIGNAL ;
    PORT
      LAYER M5 ;
        RECT  83.616 0 83.64 0.192 ;
    END
  END o_d[482]
  PIN o_d[483]
    DIRECTION OUTPUT ;
    USE SIGNAL ;
    PORT
      LAYER M5 ;
        RECT  83.76 0 83.784 0.192 ;
    END
  END o_d[483]
  PIN o_d[484]
    DIRECTION OUTPUT ;
    USE SIGNAL ;
    PORT
      LAYER M5 ;
        RECT  83.904 0 83.928 0.192 ;
    END
  END o_d[484]
  PIN o_d[485]
    DIRECTION OUTPUT ;
    USE SIGNAL ;
    PORT
      LAYER M5 ;
        RECT  84.048 0 84.072 0.192 ;
    END
  END o_d[485]
  PIN o_d[486]
    DIRECTION OUTPUT ;
    USE SIGNAL ;
    PORT
      LAYER M5 ;
        RECT  84.192 0 84.216 0.192 ;
    END
  END o_d[486]
  PIN o_d[487]
    DIRECTION OUTPUT ;
    USE SIGNAL ;
    PORT
      LAYER M5 ;
        RECT  84.336 0 84.36 0.192 ;
    END
  END o_d[487]
  PIN o_d[488]
    DIRECTION OUTPUT ;
    USE SIGNAL ;
    PORT
      LAYER M5 ;
        RECT  84.48 0 84.504 0.192 ;
    END
  END o_d[488]
  PIN o_d[489]
    DIRECTION OUTPUT ;
    USE SIGNAL ;
    PORT
      LAYER M5 ;
        RECT  84.624 0 84.648 0.192 ;
    END
  END o_d[489]
  PIN o_d[48]
    DIRECTION OUTPUT ;
    USE SIGNAL ;
    PORT
      LAYER M5 ;
        RECT  12.576 0 12.6 0.192 ;
    END
  END o_d[48]
  PIN o_d[490]
    DIRECTION OUTPUT ;
    USE SIGNAL ;
    PORT
      LAYER M5 ;
        RECT  84.768 0 84.792 0.192 ;
    END
  END o_d[490]
  PIN o_d[491]
    DIRECTION OUTPUT ;
    USE SIGNAL ;
    PORT
      LAYER M5 ;
        RECT  84.912 0 84.936 0.192 ;
    END
  END o_d[491]
  PIN o_d[492]
    DIRECTION OUTPUT ;
    USE SIGNAL ;
    PORT
      LAYER M5 ;
        RECT  85.056 0 85.08 0.192 ;
    END
  END o_d[492]
  PIN o_d[493]
    DIRECTION OUTPUT ;
    USE SIGNAL ;
    PORT
      LAYER M5 ;
        RECT  85.2 0 85.224 0.192 ;
    END
  END o_d[493]
  PIN o_d[494]
    DIRECTION OUTPUT ;
    USE SIGNAL ;
    PORT
      LAYER M5 ;
        RECT  85.344 0 85.368 0.192 ;
    END
  END o_d[494]
  PIN o_d[495]
    DIRECTION OUTPUT ;
    USE SIGNAL ;
    PORT
      LAYER M5 ;
        RECT  85.488 0 85.512 0.192 ;
    END
  END o_d[495]
  PIN o_d[496]
    DIRECTION OUTPUT ;
    USE SIGNAL ;
    PORT
      LAYER M5 ;
        RECT  85.632 0 85.656 0.192 ;
    END
  END o_d[496]
  PIN o_d[497]
    DIRECTION OUTPUT ;
    USE SIGNAL ;
    PORT
      LAYER M5 ;
        RECT  85.776 0 85.8 0.192 ;
    END
  END o_d[497]
  PIN o_d[498]
    DIRECTION OUTPUT ;
    USE SIGNAL ;
    PORT
      LAYER M5 ;
        RECT  85.92 0 85.944 0.192 ;
    END
  END o_d[498]
  PIN o_d[499]
    DIRECTION OUTPUT ;
    USE SIGNAL ;
    PORT
      LAYER M5 ;
        RECT  86.064 0 86.088 0.192 ;
    END
  END o_d[499]
  PIN o_d[49]
    DIRECTION OUTPUT ;
    USE SIGNAL ;
    PORT
      LAYER M5 ;
        RECT  12.72 0 12.744 0.192 ;
    END
  END o_d[49]
  PIN o_d[4]
    DIRECTION OUTPUT ;
    USE SIGNAL ;
    PORT
      LAYER M5 ;
        RECT  4.896 0 4.92 0.192 ;
    END
  END o_d[4]
  PIN o_d[500]
    DIRECTION OUTPUT ;
    USE SIGNAL ;
    PORT
      LAYER M5 ;
        RECT  86.208 0 86.232 0.192 ;
    END
  END o_d[500]
  PIN o_d[501]
    DIRECTION OUTPUT ;
    USE SIGNAL ;
    PORT
      LAYER M5 ;
        RECT  86.352 0 86.376 0.192 ;
    END
  END o_d[501]
  PIN o_d[502]
    DIRECTION OUTPUT ;
    USE SIGNAL ;
    PORT
      LAYER M5 ;
        RECT  86.496 0 86.52 0.192 ;
    END
  END o_d[502]
  PIN o_d[503]
    DIRECTION OUTPUT ;
    USE SIGNAL ;
    PORT
      LAYER M5 ;
        RECT  87.168 0 87.192 0.192 ;
    END
  END o_d[503]
  PIN o_d[504]
    DIRECTION OUTPUT ;
    USE SIGNAL ;
    PORT
      LAYER M5 ;
        RECT  87.312 0 87.336 0.192 ;
    END
  END o_d[504]
  PIN o_d[505]
    DIRECTION OUTPUT ;
    USE SIGNAL ;
    PORT
      LAYER M5 ;
        RECT  87.456 0 87.48 0.192 ;
    END
  END o_d[505]
  PIN o_d[506]
    DIRECTION OUTPUT ;
    USE SIGNAL ;
    PORT
      LAYER M5 ;
        RECT  87.6 0 87.624 0.192 ;
    END
  END o_d[506]
  PIN o_d[507]
    DIRECTION OUTPUT ;
    USE SIGNAL ;
    PORT
      LAYER M5 ;
        RECT  87.744 0 87.768 0.192 ;
    END
  END o_d[507]
  PIN o_d[508]
    DIRECTION OUTPUT ;
    USE SIGNAL ;
    PORT
      LAYER M5 ;
        RECT  87.888 0 87.912 0.192 ;
    END
  END o_d[508]
  PIN o_d[509]
    DIRECTION OUTPUT ;
    USE SIGNAL ;
    PORT
      LAYER M5 ;
        RECT  88.032 0 88.056 0.192 ;
    END
  END o_d[509]
  PIN o_d[50]
    DIRECTION OUTPUT ;
    USE SIGNAL ;
    PORT
      LAYER M5 ;
        RECT  12.864 0 12.888 0.192 ;
    END
  END o_d[50]
  PIN o_d[510]
    DIRECTION OUTPUT ;
    USE SIGNAL ;
    PORT
      LAYER M5 ;
        RECT  88.176 0 88.2 0.192 ;
    END
  END o_d[510]
  PIN o_d[511]
    DIRECTION OUTPUT ;
    USE SIGNAL ;
    PORT
      LAYER M5 ;
        RECT  88.464 0 88.488 0.192 ;
    END
  END o_d[511]
  PIN o_d[51]
    DIRECTION OUTPUT ;
    USE SIGNAL ;
    PORT
      LAYER M5 ;
        RECT  13.008 0 13.032 0.192 ;
    END
  END o_d[51]
  PIN o_d[52]
    DIRECTION OUTPUT ;
    USE SIGNAL ;
    PORT
      LAYER M5 ;
        RECT  13.152 0 13.176 0.192 ;
    END
  END o_d[52]
  PIN o_d[53]
    DIRECTION OUTPUT ;
    USE SIGNAL ;
    PORT
      LAYER M5 ;
        RECT  13.296 0 13.32 0.192 ;
    END
  END o_d[53]
  PIN o_d[54]
    DIRECTION OUTPUT ;
    USE SIGNAL ;
    PORT
      LAYER M5 ;
        RECT  13.44 0 13.464 0.192 ;
    END
  END o_d[54]
  PIN o_d[55]
    DIRECTION OUTPUT ;
    USE SIGNAL ;
    PORT
      LAYER M5 ;
        RECT  13.584 0 13.608 0.192 ;
    END
  END o_d[55]
  PIN o_d[56]
    DIRECTION OUTPUT ;
    USE SIGNAL ;
    PORT
      LAYER M5 ;
        RECT  13.728 0 13.752 0.192 ;
    END
  END o_d[56]
  PIN o_d[57]
    DIRECTION OUTPUT ;
    USE SIGNAL ;
    PORT
      LAYER M5 ;
        RECT  13.872 0 13.896 0.192 ;
    END
  END o_d[57]
  PIN o_d[58]
    DIRECTION OUTPUT ;
    USE SIGNAL ;
    PORT
      LAYER M5 ;
        RECT  14.016 0 14.04 0.192 ;
    END
  END o_d[58]
  PIN o_d[59]
    DIRECTION OUTPUT ;
    USE SIGNAL ;
    PORT
      LAYER M5 ;
        RECT  14.16 0 14.184 0.192 ;
    END
  END o_d[59]
  PIN o_d[5]
    DIRECTION OUTPUT ;
    USE SIGNAL ;
    PORT
      LAYER M5 ;
        RECT  5.04 0 5.064 0.192 ;
    END
  END o_d[5]
  PIN o_d[60]
    DIRECTION OUTPUT ;
    USE SIGNAL ;
    PORT
      LAYER M5 ;
        RECT  14.304 0 14.328 0.192 ;
    END
  END o_d[60]
  PIN o_d[61]
    DIRECTION OUTPUT ;
    USE SIGNAL ;
    PORT
      LAYER M5 ;
        RECT  14.448 0 14.472 0.192 ;
    END
  END o_d[61]
  PIN o_d[62]
    DIRECTION OUTPUT ;
    USE SIGNAL ;
    PORT
      LAYER M5 ;
        RECT  14.592 0 14.616 0.192 ;
    END
  END o_d[62]
  PIN o_d[63]
    DIRECTION OUTPUT ;
    USE SIGNAL ;
    PORT
      LAYER M5 ;
        RECT  14.736 0 14.76 0.192 ;
    END
  END o_d[63]
  PIN o_d[64]
    DIRECTION OUTPUT ;
    USE SIGNAL ;
    PORT
      LAYER M5 ;
        RECT  14.88 0 14.904 0.192 ;
    END
  END o_d[64]
  PIN o_d[65]
    DIRECTION OUTPUT ;
    USE SIGNAL ;
    PORT
      LAYER M5 ;
        RECT  15.024 0 15.048 0.192 ;
    END
  END o_d[65]
  PIN o_d[66]
    DIRECTION OUTPUT ;
    USE SIGNAL ;
    PORT
      LAYER M5 ;
        RECT  15.168 0 15.192 0.192 ;
    END
  END o_d[66]
  PIN o_d[67]
    DIRECTION OUTPUT ;
    USE SIGNAL ;
    PORT
      LAYER M5 ;
        RECT  15.312 0 15.336 0.192 ;
    END
  END o_d[67]
  PIN o_d[68]
    DIRECTION OUTPUT ;
    USE SIGNAL ;
    PORT
      LAYER M5 ;
        RECT  15.456 0 15.48 0.192 ;
    END
  END o_d[68]
  PIN o_d[69]
    DIRECTION OUTPUT ;
    USE SIGNAL ;
    PORT
      LAYER M5 ;
        RECT  15.6 0 15.624 0.192 ;
    END
  END o_d[69]
  PIN o_d[6]
    DIRECTION OUTPUT ;
    USE SIGNAL ;
    PORT
      LAYER M5 ;
        RECT  5.184 0 5.208 0.192 ;
    END
  END o_d[6]
  PIN o_d[70]
    DIRECTION OUTPUT ;
    USE SIGNAL ;
    PORT
      LAYER M5 ;
        RECT  15.744 0 15.768 0.192 ;
    END
  END o_d[70]
  PIN o_d[71]
    DIRECTION OUTPUT ;
    USE SIGNAL ;
    PORT
      LAYER M5 ;
        RECT  15.888 0 15.912 0.192 ;
    END
  END o_d[71]
  PIN o_d[72]
    DIRECTION OUTPUT ;
    USE SIGNAL ;
    PORT
      LAYER M5 ;
        RECT  16.032 0 16.056 0.192 ;
    END
  END o_d[72]
  PIN o_d[73]
    DIRECTION OUTPUT ;
    USE SIGNAL ;
    PORT
      LAYER M5 ;
        RECT  16.176 0 16.2 0.192 ;
    END
  END o_d[73]
  PIN o_d[74]
    DIRECTION OUTPUT ;
    USE SIGNAL ;
    PORT
      LAYER M5 ;
        RECT  16.32 0 16.344 0.192 ;
    END
  END o_d[74]
  PIN o_d[75]
    DIRECTION OUTPUT ;
    USE SIGNAL ;
    PORT
      LAYER M5 ;
        RECT  16.944 0 16.968 0.192 ;
    END
  END o_d[75]
  PIN o_d[76]
    DIRECTION OUTPUT ;
    USE SIGNAL ;
    PORT
      LAYER M5 ;
        RECT  17.088 0 17.112 0.192 ;
    END
  END o_d[76]
  PIN o_d[77]
    DIRECTION OUTPUT ;
    USE SIGNAL ;
    PORT
      LAYER M5 ;
        RECT  17.376 0 17.4 0.192 ;
    END
  END o_d[77]
  PIN o_d[78]
    DIRECTION OUTPUT ;
    USE SIGNAL ;
    PORT
      LAYER M5 ;
        RECT  17.52 0 17.544 0.192 ;
    END
  END o_d[78]
  PIN o_d[79]
    DIRECTION OUTPUT ;
    USE SIGNAL ;
    PORT
      LAYER M5 ;
        RECT  17.664 0 17.688 0.192 ;
    END
  END o_d[79]
  PIN o_d[7]
    DIRECTION OUTPUT ;
    USE SIGNAL ;
    PORT
      LAYER M5 ;
        RECT  5.328 0 5.352 0.192 ;
    END
  END o_d[7]
  PIN o_d[80]
    DIRECTION OUTPUT ;
    USE SIGNAL ;
    PORT
      LAYER M5 ;
        RECT  17.808 0 17.832 0.192 ;
    END
  END o_d[80]
  PIN o_d[81]
    DIRECTION OUTPUT ;
    USE SIGNAL ;
    PORT
      LAYER M5 ;
        RECT  17.952 0 17.976 0.192 ;
    END
  END o_d[81]
  PIN o_d[82]
    DIRECTION OUTPUT ;
    USE SIGNAL ;
    PORT
      LAYER M5 ;
        RECT  18.096 0 18.12 0.192 ;
    END
  END o_d[82]
  PIN o_d[83]
    DIRECTION OUTPUT ;
    USE SIGNAL ;
    PORT
      LAYER M5 ;
        RECT  18.24 0 18.264 0.192 ;
    END
  END o_d[83]
  PIN o_d[84]
    DIRECTION OUTPUT ;
    USE SIGNAL ;
    PORT
      LAYER M5 ;
        RECT  18.384 0 18.408 0.192 ;
    END
  END o_d[84]
  PIN o_d[85]
    DIRECTION OUTPUT ;
    USE SIGNAL ;
    PORT
      LAYER M5 ;
        RECT  18.528 0 18.552 0.192 ;
    END
  END o_d[85]
  PIN o_d[86]
    DIRECTION OUTPUT ;
    USE SIGNAL ;
    PORT
      LAYER M5 ;
        RECT  18.672 0 18.696 0.192 ;
    END
  END o_d[86]
  PIN o_d[87]
    DIRECTION OUTPUT ;
    USE SIGNAL ;
    PORT
      LAYER M5 ;
        RECT  18.816 0 18.84 0.192 ;
    END
  END o_d[87]
  PIN o_d[88]
    DIRECTION OUTPUT ;
    USE SIGNAL ;
    PORT
      LAYER M5 ;
        RECT  18.96 0 18.984 0.192 ;
    END
  END o_d[88]
  PIN o_d[89]
    DIRECTION OUTPUT ;
    USE SIGNAL ;
    PORT
      LAYER M5 ;
        RECT  19.104 0 19.128 0.192 ;
    END
  END o_d[89]
  PIN o_d[8]
    DIRECTION OUTPUT ;
    USE SIGNAL ;
    PORT
      LAYER M5 ;
        RECT  5.472 0 5.496 0.192 ;
    END
  END o_d[8]
  PIN o_d[90]
    DIRECTION OUTPUT ;
    USE SIGNAL ;
    PORT
      LAYER M5 ;
        RECT  19.248 0 19.272 0.192 ;
    END
  END o_d[90]
  PIN o_d[91]
    DIRECTION OUTPUT ;
    USE SIGNAL ;
    PORT
      LAYER M5 ;
        RECT  19.392 0 19.416 0.192 ;
    END
  END o_d[91]
  PIN o_d[92]
    DIRECTION OUTPUT ;
    USE SIGNAL ;
    PORT
      LAYER M5 ;
        RECT  19.536 0 19.56 0.192 ;
    END
  END o_d[92]
  PIN o_d[93]
    DIRECTION OUTPUT ;
    USE SIGNAL ;
    PORT
      LAYER M5 ;
        RECT  19.68 0 19.704 0.192 ;
    END
  END o_d[93]
  PIN o_d[94]
    DIRECTION OUTPUT ;
    USE SIGNAL ;
    PORT
      LAYER M5 ;
        RECT  19.824 0 19.848 0.192 ;
    END
  END o_d[94]
  PIN o_d[95]
    DIRECTION OUTPUT ;
    USE SIGNAL ;
    PORT
      LAYER M5 ;
        RECT  19.968 0 19.992 0.192 ;
    END
  END o_d[95]
  PIN o_d[96]
    DIRECTION OUTPUT ;
    USE SIGNAL ;
    PORT
      LAYER M5 ;
        RECT  20.112 0 20.136 0.192 ;
    END
  END o_d[96]
  PIN o_d[97]
    DIRECTION OUTPUT ;
    USE SIGNAL ;
    PORT
      LAYER M5 ;
        RECT  20.256 0 20.28 0.192 ;
    END
  END o_d[97]
  PIN o_d[98]
    DIRECTION OUTPUT ;
    USE SIGNAL ;
    PORT
      LAYER M5 ;
        RECT  20.4 0 20.424 0.192 ;
    END
  END o_d[98]
  PIN o_d[99]
    DIRECTION OUTPUT ;
    USE SIGNAL ;
    PORT
      LAYER M5 ;
        RECT  20.544 0 20.568 0.192 ;
    END
  END o_d[99]
  PIN o_d[9]
    DIRECTION OUTPUT ;
    USE SIGNAL ;
    PORT
      LAYER M5 ;
        RECT  6.144 0 6.168 0.192 ;
    END
  END o_d[9]
  PIN o_row[0]
    DIRECTION OUTPUT ;
    USE SIGNAL ;
    PORT
      LAYER M5 ;
        RECT  88.752 0 88.776 0.192 ;
    END
  END o_row[0]
  PIN o_row[10]
    DIRECTION OUTPUT ;
    USE SIGNAL ;
    PORT
      LAYER M5 ;
        RECT  90.192 0 90.216 0.192 ;
    END
  END o_row[10]
  PIN o_row[11]
    DIRECTION OUTPUT ;
    USE SIGNAL ;
    PORT
      LAYER M5 ;
        RECT  90.336 0 90.36 0.192 ;
    END
  END o_row[11]
  PIN o_row[12]
    DIRECTION OUTPUT ;
    USE SIGNAL ;
    PORT
      LAYER M5 ;
        RECT  90.48 0 90.504 0.192 ;
    END
  END o_row[12]
  PIN o_row[13]
    DIRECTION OUTPUT ;
    USE SIGNAL ;
    PORT
      LAYER M5 ;
        RECT  90.624 0 90.648 0.192 ;
    END
  END o_row[13]
  PIN o_row[1]
    DIRECTION OUTPUT ;
    USE SIGNAL ;
    PORT
      LAYER M5 ;
        RECT  88.896 0 88.92 0.192 ;
    END
  END o_row[1]
  PIN o_row[2]
    DIRECTION OUTPUT ;
    USE SIGNAL ;
    PORT
      LAYER M5 ;
        RECT  89.04 0 89.064 0.192 ;
    END
  END o_row[2]
  PIN o_row[3]
    DIRECTION OUTPUT ;
    USE SIGNAL ;
    PORT
      LAYER M5 ;
        RECT  89.184 0 89.208 0.192 ;
    END
  END o_row[3]
  PIN o_row[4]
    DIRECTION OUTPUT ;
    USE SIGNAL ;
    PORT
      LAYER M5 ;
        RECT  89.328 0 89.352 0.192 ;
    END
  END o_row[4]
  PIN o_row[5]
    DIRECTION OUTPUT ;
    USE SIGNAL ;
    PORT
      LAYER M5 ;
        RECT  89.472 0 89.496 0.192 ;
    END
  END o_row[5]
  PIN o_row[6]
    DIRECTION OUTPUT ;
    USE SIGNAL ;
    PORT
      LAYER M5 ;
        RECT  89.616 0 89.64 0.192 ;
    END
  END o_row[6]
  PIN o_row[7]
    DIRECTION OUTPUT ;
    USE SIGNAL ;
    PORT
      LAYER M5 ;
        RECT  89.76 0 89.784 0.192 ;
    END
  END o_row[7]
  PIN o_row[8]
    DIRECTION OUTPUT ;
    USE SIGNAL ;
    PORT
      LAYER M5 ;
        RECT  89.904 0 89.928 0.192 ;
    END
  END o_row[8]
  PIN o_row[9]
    DIRECTION OUTPUT ;
    USE SIGNAL ;
    PORT
      LAYER M5 ;
        RECT  90.048 0 90.072 0.192 ;
    END
  END o_row[9]
  PIN o_v
    DIRECTION OUTPUT ;
    USE SIGNAL ;
    PORT
      LAYER M5 ;
        RECT  88.608 0 88.632 0.192 ;
    END
  END o_v
  PIN rst_n
    DIRECTION INPUT ;
    USE SIGNAL ;
    PORT
      LAYER M4 ;
        RECT  0 10.08 0.192 10.104 ;
    END
    PORT
      LAYER M4 ;
        RECT  0.156 10.08 2.408 10.104 ;
    END
  END rst_n
  PIN VDD
    DIRECTION INOUT ;
    USE POWER ;
    PORT
      LAYER M5 ;
        RECT  88.992 2.151 89.112 92.889 ;
        RECT  83.592 2.151 83.712 92.889 ;
        RECT  78.192 2.151 78.312 92.889 ;
        RECT  72.792 2.151 72.912 92.889 ;
        RECT  67.392 2.151 67.512 92.889 ;
        RECT  61.992 2.151 62.112 92.889 ;
        RECT  56.592 2.151 56.712 92.889 ;
        RECT  51.192 2.151 51.312 92.889 ;
        RECT  45.792 2.151 45.912 92.889 ;
        RECT  40.392 2.151 40.512 92.889 ;
        RECT  34.992 2.151 35.112 92.889 ;
        RECT  29.592 2.151 29.712 92.889 ;
        RECT  24.192 2.151 24.312 92.889 ;
        RECT  18.792 2.151 18.912 92.889 ;
        RECT  13.392 2.151 13.512 92.889 ;
        RECT  7.992 2.151 8.112 92.889 ;
        RECT  2.592 2.151 2.712 92.889 ;
    END
  END VDD
  PIN VSS
    DIRECTION INOUT ;
    USE GROUND ;
    PORT
      LAYER M5 ;
        RECT  88.8 2.137 88.92 92.903 ;
        RECT  83.4 2.137 83.52 92.903 ;
        RECT  78 2.137 78.12 92.903 ;
        RECT  72.6 2.137 72.72 92.903 ;
        RECT  67.2 2.137 67.32 92.903 ;
        RECT  61.8 2.137 61.92 92.903 ;
        RECT  56.4 2.137 56.52 92.903 ;
        RECT  51 2.137 51.12 92.903 ;
        RECT  45.6 2.137 45.72 92.903 ;
        RECT  40.2 2.137 40.32 92.903 ;
        RECT  34.8 2.137 34.92 92.903 ;
        RECT  29.4 2.137 29.52 92.903 ;
        RECT  24 2.137 24.12 92.903 ;
        RECT  18.6 2.137 18.72 92.903 ;
        RECT  13.2 2.137 13.32 92.903 ;
        RECT  7.8 2.137 7.92 92.903 ;
        RECT  2.4 2.137 2.52 92.903 ;
    END
  END VSS
  # OT_OBS_CLOSED layer=M5 d_um=1.536 added=140
  OBS
    LAYER RVTN ;
     RECT  2.16 2.16 92.88 2.295 ;
     RECT  2.16 2.565 92.88 2.835 ;
     RECT  2.16 3.105 92.88 3.375 ;
     RECT  2.16 3.645 92.88 3.915 ;
     RECT  2.16 4.185 92.88 4.455 ;
     RECT  2.16 4.725 92.88 4.995 ;
     RECT  2.16 5.265 92.88 5.535 ;
     RECT  2.16 5.805 92.88 6.075 ;
     RECT  2.16 6.345 92.88 6.615 ;
     RECT  2.16 6.885 92.88 7.155 ;
     RECT  2.16 7.425 92.88 7.695 ;
     RECT  2.16 7.965 92.88 8.235 ;
     RECT  2.16 8.505 92.88 8.775 ;
     RECT  2.16 9.045 92.88 9.315 ;
     RECT  2.16 9.585 92.88 9.855 ;
     RECT  2.16 10.125 92.88 10.395 ;
     RECT  2.16 10.665 92.88 10.935 ;
     RECT  2.16 11.205 92.88 11.475 ;
     RECT  2.16 11.745 92.88 12.015 ;
     RECT  2.16 12.285 92.88 12.555 ;
     RECT  2.16 12.825 92.88 13.095 ;
     RECT  2.16 13.365 92.88 13.635 ;
     RECT  2.16 13.905 92.88 14.175 ;
     RECT  2.16 14.445 92.88 14.715 ;
     RECT  2.16 14.985 92.88 15.255 ;
     RECT  2.16 15.525 92.88 15.795 ;
     RECT  2.16 16.065 92.88 16.335 ;
     RECT  2.16 16.605 92.88 16.875 ;
     RECT  2.16 17.145 92.88 17.415 ;
     RECT  2.16 17.685 92.88 17.955 ;
     RECT  2.16 18.225 92.88 18.495 ;
     RECT  2.16 18.765 92.88 19.035 ;
     RECT  2.16 19.305 92.88 19.575 ;
     RECT  2.16 19.845 92.88 20.115 ;
     RECT  2.16 20.385 92.88 20.655 ;
     RECT  2.16 20.925 92.88 21.195 ;
     RECT  2.16 21.465 92.88 21.735 ;
     RECT  2.16 22.005 92.88 22.275 ;
     RECT  2.16 22.545 92.88 22.815 ;
     RECT  2.16 23.085 92.88 23.355 ;
     RECT  2.16 23.625 92.88 23.895 ;
     RECT  2.16 24.165 92.88 24.435 ;
     RECT  2.16 24.705 92.88 24.975 ;
     RECT  2.16 25.245 92.88 25.515 ;
     RECT  2.16 25.785 92.88 26.055 ;
     RECT  2.16 26.325 92.88 26.595 ;
     RECT  2.16 26.865 92.88 27.135 ;
     RECT  2.16 27.405 92.88 27.675 ;
     RECT  2.16 27.945 92.88 28.215 ;
     RECT  2.16 28.485 92.88 28.755 ;
     RECT  2.16 29.025 92.88 29.295 ;
     RECT  2.16 29.565 92.88 29.835 ;
     RECT  2.16 30.105 92.88 30.375 ;
     RECT  2.16 30.645 92.88 30.915 ;
     RECT  2.16 31.185 92.88 31.455 ;
     RECT  2.16 31.725 92.88 31.995 ;
     RECT  2.16 32.265 92.88 32.535 ;
     RECT  2.16 32.805 92.88 33.075 ;
     RECT  2.16 33.345 92.88 33.615 ;
     RECT  2.16 33.885 92.88 34.155 ;
     RECT  2.16 34.425 92.88 34.695 ;
     RECT  2.16 34.965 92.88 35.235 ;
     RECT  2.16 35.505 92.88 35.775 ;
     RECT  2.16 36.045 92.88 36.315 ;
     RECT  2.16 36.585 92.88 36.855 ;
     RECT  2.16 37.125 92.88 37.395 ;
     RECT  2.16 37.665 92.88 37.935 ;
     RECT  2.16 38.205 92.88 38.475 ;
     RECT  2.16 38.745 92.88 39.015 ;
     RECT  2.16 39.285 92.88 39.555 ;
     RECT  2.16 39.825 92.88 40.095 ;
     RECT  2.16 40.365 92.88 40.635 ;
     RECT  2.16 40.905 92.88 41.175 ;
     RECT  2.16 41.445 92.88 41.715 ;
     RECT  2.16 41.985 92.88 42.255 ;
     RECT  2.16 42.525 92.88 42.795 ;
     RECT  2.16 43.065 92.88 43.335 ;
     RECT  2.16 43.605 92.88 43.875 ;
     RECT  2.16 44.145 92.88 44.415 ;
     RECT  2.16 44.685 92.88 44.955 ;
     RECT  2.16 45.225 92.88 45.495 ;
     RECT  2.16 45.765 92.88 46.035 ;
     RECT  2.16 46.305 92.88 46.575 ;
     RECT  2.16 46.845 92.88 47.115 ;
     RECT  2.16 47.385 92.88 47.655 ;
     RECT  2.16 47.925 92.88 48.195 ;
     RECT  2.16 48.465 92.88 48.735 ;
     RECT  2.16 49.005 92.88 49.275 ;
     RECT  2.16 49.545 92.88 49.815 ;
     RECT  2.16 50.085 92.88 50.355 ;
     RECT  2.16 50.625 92.88 50.895 ;
     RECT  2.16 51.165 92.88 51.435 ;
     RECT  2.16 51.705 92.88 51.975 ;
     RECT  2.16 52.245 92.88 52.515 ;
     RECT  2.16 52.785 92.88 53.055 ;
     RECT  2.16 53.325 92.88 53.595 ;
     RECT  2.16 53.865 92.88 54.135 ;
     RECT  2.16 54.405 92.88 54.675 ;
     RECT  2.16 54.945 92.88 55.215 ;
     RECT  2.16 55.485 92.88 55.755 ;
     RECT  2.16 56.025 92.88 56.295 ;
     RECT  2.16 56.565 92.88 56.835 ;
     RECT  2.16 57.105 92.88 57.375 ;
     RECT  2.16 57.645 92.88 57.915 ;
     RECT  2.16 58.185 92.88 58.455 ;
     RECT  2.16 58.725 92.88 58.995 ;
     RECT  2.16 59.265 92.88 59.535 ;
     RECT  2.16 59.805 92.88 60.075 ;
     RECT  2.16 60.345 92.88 60.615 ;
     RECT  2.16 60.885 92.88 61.155 ;
     RECT  2.16 61.425 92.88 61.695 ;
     RECT  2.16 61.965 92.88 62.235 ;
     RECT  2.16 62.505 92.88 62.775 ;
     RECT  2.16 63.045 92.88 63.315 ;
     RECT  2.16 63.585 92.88 63.855 ;
     RECT  2.16 64.125 92.88 64.395 ;
     RECT  2.16 64.665 92.88 64.935 ;
     RECT  2.16 65.205 92.88 65.475 ;
     RECT  2.16 65.745 92.88 66.015 ;
     RECT  2.16 66.285 92.88 66.555 ;
     RECT  2.16 66.825 92.88 67.095 ;
     RECT  2.16 67.365 92.88 67.635 ;
     RECT  2.16 67.905 92.88 68.175 ;
     RECT  2.16 68.445 92.88 68.715 ;
     RECT  2.16 68.985 92.88 69.255 ;
     RECT  2.16 69.525 92.88 69.795 ;
     RECT  2.16 70.065 92.88 70.335 ;
     RECT  2.16 70.605 92.88 70.875 ;
     RECT  2.16 71.145 92.88 71.415 ;
     RECT  2.16 71.685 92.88 71.955 ;
     RECT  2.16 72.225 92.88 72.495 ;
     RECT  2.16 72.765 92.88 73.035 ;
     RECT  2.16 73.305 92.88 73.575 ;
     RECT  2.16 73.845 92.88 74.115 ;
     RECT  2.16 74.385 92.88 74.655 ;
     RECT  2.16 74.925 92.88 75.195 ;
     RECT  2.16 75.465 92.88 75.735 ;
     RECT  2.16 76.005 92.88 76.275 ;
     RECT  2.16 76.545 92.88 76.815 ;
     RECT  2.16 77.085 92.88 77.355 ;
     RECT  2.16 77.625 92.88 77.895 ;
     RECT  2.16 78.165 92.88 78.435 ;
     RECT  2.16 78.705 92.88 78.975 ;
     RECT  2.16 79.245 92.88 79.515 ;
     RECT  2.16 79.785 92.88 80.055 ;
     RECT  2.16 80.325 92.88 80.595 ;
     RECT  2.16 80.865 92.88 81.135 ;
     RECT  2.16 81.405 92.88 81.675 ;
     RECT  2.16 81.945 92.88 82.215 ;
     RECT  2.16 82.485 92.88 82.755 ;
     RECT  2.16 83.025 92.88 83.295 ;
     RECT  2.16 83.565 92.88 83.835 ;
     RECT  2.16 84.105 92.88 84.375 ;
     RECT  2.16 84.645 92.88 84.915 ;
     RECT  2.16 85.185 92.88 85.455 ;
     RECT  2.16 85.725 92.88 85.995 ;
     RECT  2.16 86.265 92.88 86.535 ;
     RECT  2.16 86.805 92.88 87.075 ;
     RECT  2.16 87.345 92.88 87.615 ;
     RECT  2.16 87.885 92.88 88.155 ;
     RECT  2.16 88.425 92.88 88.695 ;
     RECT  2.16 88.965 92.88 89.235 ;
     RECT  2.16 89.505 92.88 89.775 ;
     RECT  2.16 90.045 92.88 90.315 ;
     RECT  2.16 90.585 92.88 90.855 ;
     RECT  2.16 91.125 92.88 91.395 ;
     RECT  2.16 91.665 92.88 91.935 ;
     RECT  2.16 92.205 92.88 92.475 ;
     RECT  2.16 92.745 92.88 92.88 ;
    LAYER RVTP ;
     RECT  2.16 2.295 92.88 2.565 ;
     RECT  2.16 2.835 92.88 3.105 ;
     RECT  2.16 3.375 92.88 3.645 ;
     RECT  2.16 3.915 92.88 4.185 ;
     RECT  2.16 4.455 92.88 4.725 ;
     RECT  2.16 4.995 92.88 5.265 ;
     RECT  2.16 5.535 92.88 5.805 ;
     RECT  2.16 6.075 92.88 6.345 ;
     RECT  2.16 6.615 92.88 6.885 ;
     RECT  2.16 7.155 92.88 7.425 ;
     RECT  2.16 7.695 92.88 7.965 ;
     RECT  2.16 8.235 92.88 8.505 ;
     RECT  2.16 8.775 92.88 9.045 ;
     RECT  2.16 9.315 92.88 9.585 ;
     RECT  2.16 9.855 92.88 10.125 ;
     RECT  2.16 10.395 92.88 10.665 ;
     RECT  2.16 10.935 92.88 11.205 ;
     RECT  2.16 11.475 92.88 11.745 ;
     RECT  2.16 12.015 92.88 12.285 ;
     RECT  2.16 12.555 92.88 12.825 ;
     RECT  2.16 13.095 92.88 13.365 ;
     RECT  2.16 13.635 92.88 13.905 ;
     RECT  2.16 14.175 92.88 14.445 ;
     RECT  2.16 14.715 92.88 14.985 ;
     RECT  2.16 15.255 92.88 15.525 ;
     RECT  2.16 15.795 92.88 16.065 ;
     RECT  2.16 16.335 92.88 16.605 ;
     RECT  2.16 16.875 92.88 17.145 ;
     RECT  2.16 17.415 92.88 17.685 ;
     RECT  2.16 17.955 92.88 18.225 ;
     RECT  2.16 18.495 92.88 18.765 ;
     RECT  2.16 19.035 92.88 19.305 ;
     RECT  2.16 19.575 92.88 19.845 ;
     RECT  2.16 20.115 92.88 20.385 ;
     RECT  2.16 20.655 92.88 20.925 ;
     RECT  2.16 21.195 92.88 21.465 ;
     RECT  2.16 21.735 92.88 22.005 ;
     RECT  2.16 22.275 92.88 22.545 ;
     RECT  2.16 22.815 92.88 23.085 ;
     RECT  2.16 23.355 92.88 23.625 ;
     RECT  2.16 23.895 92.88 24.165 ;
     RECT  2.16 24.435 92.88 24.705 ;
     RECT  2.16 24.975 92.88 25.245 ;
     RECT  2.16 25.515 92.88 25.785 ;
     RECT  2.16 26.055 92.88 26.325 ;
     RECT  2.16 26.595 92.88 26.865 ;
     RECT  2.16 27.135 92.88 27.405 ;
     RECT  2.16 27.675 92.88 27.945 ;
     RECT  2.16 28.215 92.88 28.485 ;
     RECT  2.16 28.755 92.88 29.025 ;
     RECT  2.16 29.295 92.88 29.565 ;
     RECT  2.16 29.835 92.88 30.105 ;
     RECT  2.16 30.375 92.88 30.645 ;
     RECT  2.16 30.915 92.88 31.185 ;
     RECT  2.16 31.455 92.88 31.725 ;
     RECT  2.16 31.995 92.88 32.265 ;
     RECT  2.16 32.535 92.88 32.805 ;
     RECT  2.16 33.075 92.88 33.345 ;
     RECT  2.16 33.615 92.88 33.885 ;
     RECT  2.16 34.155 92.88 34.425 ;
     RECT  2.16 34.695 92.88 34.965 ;
     RECT  2.16 35.235 92.88 35.505 ;
     RECT  2.16 35.775 92.88 36.045 ;
     RECT  2.16 36.315 92.88 36.585 ;
     RECT  2.16 36.855 92.88 37.125 ;
     RECT  2.16 37.395 92.88 37.665 ;
     RECT  2.16 37.935 92.88 38.205 ;
     RECT  2.16 38.475 92.88 38.745 ;
     RECT  2.16 39.015 92.88 39.285 ;
     RECT  2.16 39.555 92.88 39.825 ;
     RECT  2.16 40.095 92.88 40.365 ;
     RECT  2.16 40.635 92.88 40.905 ;
     RECT  2.16 41.175 92.88 41.445 ;
     RECT  2.16 41.715 92.88 41.985 ;
     RECT  2.16 42.255 92.88 42.525 ;
     RECT  2.16 42.795 92.88 43.065 ;
     RECT  2.16 43.335 92.88 43.605 ;
     RECT  2.16 43.875 92.88 44.145 ;
     RECT  2.16 44.415 92.88 44.685 ;
     RECT  2.16 44.955 92.88 45.225 ;
     RECT  2.16 45.495 92.88 45.765 ;
     RECT  2.16 46.035 92.88 46.305 ;
     RECT  2.16 46.575 92.88 46.845 ;
     RECT  2.16 47.115 92.88 47.385 ;
     RECT  2.16 47.655 92.88 47.925 ;
     RECT  2.16 48.195 92.88 48.465 ;
     RECT  2.16 48.735 92.88 49.005 ;
     RECT  2.16 49.275 92.88 49.545 ;
     RECT  2.16 49.815 92.88 50.085 ;
     RECT  2.16 50.355 92.88 50.625 ;
     RECT  2.16 50.895 92.88 51.165 ;
     RECT  2.16 51.435 92.88 51.705 ;
     RECT  2.16 51.975 92.88 52.245 ;
     RECT  2.16 52.515 92.88 52.785 ;
     RECT  2.16 53.055 92.88 53.325 ;
     RECT  2.16 53.595 92.88 53.865 ;
     RECT  2.16 54.135 92.88 54.405 ;
     RECT  2.16 54.675 92.88 54.945 ;
     RECT  2.16 55.215 92.88 55.485 ;
     RECT  2.16 55.755 92.88 56.025 ;
     RECT  2.16 56.295 92.88 56.565 ;
     RECT  2.16 56.835 92.88 57.105 ;
     RECT  2.16 57.375 92.88 57.645 ;
     RECT  2.16 57.915 92.88 58.185 ;
     RECT  2.16 58.455 92.88 58.725 ;
     RECT  2.16 58.995 92.88 59.265 ;
     RECT  2.16 59.535 92.88 59.805 ;
     RECT  2.16 60.075 92.88 60.345 ;
     RECT  2.16 60.615 92.88 60.885 ;
     RECT  2.16 61.155 92.88 61.425 ;
     RECT  2.16 61.695 92.88 61.965 ;
     RECT  2.16 62.235 92.88 62.505 ;
     RECT  2.16 62.775 92.88 63.045 ;
     RECT  2.16 63.315 92.88 63.585 ;
     RECT  2.16 63.855 92.88 64.125 ;
     RECT  2.16 64.395 92.88 64.665 ;
     RECT  2.16 64.935 92.88 65.205 ;
     RECT  2.16 65.475 92.88 65.745 ;
     RECT  2.16 66.015 92.88 66.285 ;
     RECT  2.16 66.555 92.88 66.825 ;
     RECT  2.16 67.095 92.88 67.365 ;
     RECT  2.16 67.635 92.88 67.905 ;
     RECT  2.16 68.175 92.88 68.445 ;
     RECT  2.16 68.715 92.88 68.985 ;
     RECT  2.16 69.255 92.88 69.525 ;
     RECT  2.16 69.795 92.88 70.065 ;
     RECT  2.16 70.335 92.88 70.605 ;
     RECT  2.16 70.875 92.88 71.145 ;
     RECT  2.16 71.415 92.88 71.685 ;
     RECT  2.16 71.955 92.88 72.225 ;
     RECT  2.16 72.495 92.88 72.765 ;
     RECT  2.16 73.035 92.88 73.305 ;
     RECT  2.16 73.575 92.88 73.845 ;
     RECT  2.16 74.115 92.88 74.385 ;
     RECT  2.16 74.655 92.88 74.925 ;
     RECT  2.16 75.195 92.88 75.465 ;
     RECT  2.16 75.735 92.88 76.005 ;
     RECT  2.16 76.275 92.88 76.545 ;
     RECT  2.16 76.815 92.88 77.085 ;
     RECT  2.16 77.355 92.88 77.625 ;
     RECT  2.16 77.895 92.88 78.165 ;
     RECT  2.16 78.435 92.88 78.705 ;
     RECT  2.16 78.975 92.88 79.245 ;
     RECT  2.16 79.515 92.88 79.785 ;
     RECT  2.16 80.055 92.88 80.325 ;
     RECT  2.16 80.595 92.88 80.865 ;
     RECT  2.16 81.135 92.88 81.405 ;
     RECT  2.16 81.675 92.88 81.945 ;
     RECT  2.16 82.215 92.88 82.485 ;
     RECT  2.16 82.755 92.88 83.025 ;
     RECT  2.16 83.295 92.88 83.565 ;
     RECT  2.16 83.835 92.88 84.105 ;
     RECT  2.16 84.375 92.88 84.645 ;
     RECT  2.16 84.915 92.88 85.185 ;
     RECT  2.16 85.455 92.88 85.725 ;
     RECT  2.16 85.995 92.88 86.265 ;
     RECT  2.16 86.535 92.88 86.805 ;
     RECT  2.16 87.075 92.88 87.345 ;
     RECT  2.16 87.615 92.88 87.885 ;
     RECT  2.16 88.155 92.88 88.425 ;
     RECT  2.16 88.695 92.88 88.965 ;
     RECT  2.16 89.235 92.88 89.505 ;
     RECT  2.16 89.775 92.88 90.045 ;
     RECT  2.16 90.315 92.88 90.585 ;
     RECT  2.16 90.855 92.88 91.125 ;
     RECT  2.16 91.395 92.88 91.665 ;
     RECT  2.16 91.935 92.88 92.205 ;
     RECT  2.16 92.475 92.88 92.745 ;
    LAYER M1 ;
     RECT  2.16 2.151 92.88 92.889 ;
    LAYER M2 ;
     RECT  0.211 33.552 2.16 33.57 ;
     RECT  2.16 2.151 4.171 92.889 ;
     RECT  4.171 2.106 4.279 92.889 ;
     RECT  4.279 2.034 4.891 92.889 ;
     RECT  5.503 1.152 5.603 1.17 ;
     RECT  4.891 1.962 7.547 92.889 ;
     RECT  7.547 2.151 10.579 92.889 ;
     RECT  10.579 2.106 12.191 92.889 ;
     RECT  12.191 2.151 13.675 92.889 ;
     RECT  13.675 2.106 16.007 92.889 ;
     RECT  22.819 1.152 22.955 1.17 ;
     RECT  16.007 2.151 30.415 92.889 ;
     RECT  30.415 2.106 33.323 92.889 ;
     RECT  33.323 2.151 36.715 92.889 ;
     RECT  36.715 2.106 37.895 92.889 ;
     RECT  37.895 2.151 47.731 92.889 ;
     RECT  47.731 2.106 48.335 92.889 ;
     RECT  48.335 2.151 51.655 92.889 ;
     RECT  51.655 2.106 52.331 92.889 ;
     RECT  52.331 2.151 55.111 92.889 ;
     RECT  55.111 2.106 56.327 92.889 ;
     RECT  56.327 2.151 62.023 92.889 ;
     RECT  62.023 2.106 62.267 92.889 ;
     RECT  62.267 2.151 66.163 92.889 ;
     RECT  66.163 2.106 67.127 92.889 ;
     RECT  67.127 2.151 76.963 92.889 ;
     RECT  76.963 2.106 77.783 92.889 ;
     RECT  84.163 1.152 84.263 1.17 ;
     RECT  77.783 2.151 90.067 92.889 ;
     RECT  90.067 2.106 91.211 92.889 ;
     RECT  91.211 2.151 92.88 92.889 ;
     RECT  92.88 18.738 93.515 18.756 ;
     RECT  92.88 76.356 93.515 76.374 ;
     RECT  92.88 47.556 94.055 47.574 ;
    LAYER M3 ;
     RECT  73.908 0.187 73.926 0.283 ;
     RECT  67.032 0.187 67.698 0.317 ;
     RECT  78.48 0.187 79.002 0.317 ;
     RECT  13.572 0.187 13.59 0.365 ;
     RECT  64.188 0.187 64.206 0.365 ;
     RECT  72.504 0.235 72.522 0.413 ;
     RECT  24.48 0.283 24.498 0.461 ;
     RECT  4.212 0.187 4.626 0.571 ;
     RECT  5.58 0.571 5.598 1.051 ;
     RECT  4.212 0.571 4.77 1.099 ;
     RECT  5.58 1.051 6.174 1.099 ;
     RECT  6.948 0.187 6.966 1.099 ;
     RECT  54.792 0.187 54.81 1.099 ;
     RECT  80.532 0.571 80.55 1.099 ;
     RECT  84.168 0.571 84.186 1.099 ;
     RECT  5.58 1.099 6.966 1.147 ;
     RECT  7.704 0.187 7.722 1.147 ;
     RECT  22.824 0.187 22.842 1.147 ;
     RECT  45.144 0.187 45.162 1.147 ;
     RECT  57.636 0.571 57.654 1.147 ;
     RECT  61.956 0.187 61.974 1.147 ;
     RECT  80.532 1.099 80.586 1.147 ;
     RECT  4.068 1.099 4.77 1.627 ;
     RECT  5.508 1.147 7.722 1.627 ;
     RECT  4.068 1.627 7.722 1.675 ;
     RECT  8.784 1.099 8.802 1.675 ;
     RECT  40.14 1.147 40.158 1.675 ;
     RECT  78.984 0.317 79.002 1.675 ;
     RECT  10.26 1.099 10.278 1.723 ;
     RECT  11.592 1.675 11.61 1.723 ;
     RECT  12.456 0.187 12.474 1.723 ;
     RECT  17.352 0.187 17.37 1.723 ;
     RECT  19.044 0.571 19.062 1.723 ;
     RECT  22.824 1.147 22.95 1.723 ;
     RECT  27.972 1.675 27.99 1.723 ;
     RECT  31.752 0.571 31.77 1.723 ;
     RECT  34.164 1.099 34.182 1.723 ;
     RECT  35.712 1.147 35.73 1.723 ;
     RECT  40.14 1.675 40.554 1.723 ;
     RECT  43.92 0.523 43.938 1.723 ;
     RECT  46.116 0.571 46.134 1.723 ;
     RECT  50.544 0.523 50.562 1.723 ;
     RECT  51.516 0.187 51.534 1.723 ;
     RECT  52.956 0.187 52.974 1.723 ;
     RECT  57.348 1.147 57.654 1.723 ;
     RECT  58.464 1.147 58.482 1.723 ;
     RECT  59.652 1.147 59.67 1.723 ;
     RECT  61.416 1.147 61.974 1.723 ;
     RECT  64.44 0.523 64.602 1.723 ;
     RECT  67.032 0.317 67.05 1.723 ;
     RECT  76.572 1.147 76.59 1.723 ;
     RECT  80.532 1.147 80.694 1.723 ;
     RECT  83.376 0.523 83.394 1.723 ;
     RECT  84.168 1.099 84.582 1.723 ;
     RECT  10.26 1.723 12.474 1.771 ;
     RECT  30.276 1.723 30.294 1.771 ;
     RECT  33.552 1.723 34.182 1.771 ;
     RECT  35.28 1.723 35.73 1.771 ;
     RECT  46.116 1.723 46.242 1.771 ;
     RECT  57.132 1.723 57.654 1.771 ;
     RECT  64.44 1.723 64.746 1.771 ;
     RECT  78.66 1.675 79.002 1.771 ;
     RECT  91.296 1.771 91.314 1.867 ;
     RECT  33.552 1.771 35.73 1.915 ;
     RECT  9.972 1.771 12.474 2.011 ;
     RECT  24.552 1.723 24.57 2.011 ;
     RECT  33.552 1.915 35.946 2.011 ;
     RECT  36.792 1.723 37.17 2.011 ;
     RECT  44.712 1.147 45.162 2.059 ;
     RECT  46.116 1.771 46.386 2.059 ;
     RECT  90.072 1.723 90.522 2.059 ;
     RECT  9.972 2.011 13.626 2.101 ;
     RECT  15.624 1.723 15.642 2.101 ;
     RECT  29.592 1.771 30.294 2.101 ;
     RECT  31.104 1.723 32.382 2.101 ;
     RECT  33.552 2.011 37.17 2.101 ;
     RECT  47.592 1.723 47.754 2.101 ;
     RECT  48.996 1.723 49.014 2.101 ;
     RECT  50.544 1.723 51.678 2.101 ;
     RECT  52.956 1.723 54.054 2.101 ;
     RECT  56.772 1.771 57.654 2.101 ;
     RECT  61.416 1.723 62.046 2.101 ;
     RECT  65.628 1.723 65.646 2.101 ;
     RECT  66.636 1.723 67.05 2.101 ;
     RECT  89.496 2.059 90.522 2.101 ;
     RECT  91.26 1.867 91.314 2.101 ;
     RECT  29.592 2.101 32.526 2.143 ;
     RECT  65.628 2.101 67.122 2.143 ;
     RECT  72.36 1.147 72.378 2.143 ;
     RECT  76.572 1.723 77.922 2.143 ;
     RECT  78.66 1.771 79.326 2.143 ;
     RECT  88.668 1.771 88.686 2.143 ;
     RECT  89.496 2.101 91.314 2.143 ;
     RECT  29.415 2.143 32.526 2.155 ;
     RECT  54.792 1.099 55.206 2.155 ;
     RECT  87.66 1.723 87.678 2.155 ;
     RECT  3.78 1.675 8.802 2.191 ;
     RECT  9.972 2.101 13.698 2.191 ;
     RECT  17.352 1.723 19.458 2.191 ;
     RECT  21.168 1.675 21.186 2.191 ;
     RECT  22.68 1.723 22.95 2.191 ;
     RECT  23.976 2.011 24.57 2.191 ;
     RECT  26.532 1.147 26.55 2.191 ;
     RECT  27.9 1.723 27.99 2.191 ;
     RECT  29.16 2.155 32.526 2.191 ;
     RECT  33.3 2.101 37.89 2.191 ;
     RECT  39.312 1.723 40.554 2.191 ;
     RECT  42.588 1.723 43.938 2.191 ;
     RECT  44.712 2.059 46.386 2.191 ;
     RECT  47.592 2.101 49.014 2.191 ;
     RECT  50.544 2.101 54.054 2.191 ;
     RECT  54.792 2.155 55.422 2.191 ;
     RECT  56.304 2.101 57.654 2.191 ;
     RECT  58.464 1.723 59.67 2.191 ;
     RECT  61.416 2.101 62.262 2.191 ;
     RECT  63.792 1.771 64.746 2.191 ;
     RECT  68.364 1.723 68.706 2.191 ;
     RECT  69.516 1.723 69.534 2.191 ;
     RECT  70.38 1.147 70.398 2.191 ;
     RECT  71.208 1.723 71.226 2.191 ;
     RECT  72.36 2.143 72.705 2.191 ;
     RECT  73.872 0.283 73.926 2.191 ;
     RECT  74.772 1.723 74.79 2.191 ;
     RECT  75.672 1.147 75.69 2.191 ;
     RECT  76.572 2.143 79.326 2.191 ;
     RECT  80.532 1.723 81.162 2.191 ;
     RECT  82.62 1.723 82.638 2.191 ;
     RECT  83.376 1.723 84.582 2.191 ;
     RECT  87.3 2.155 87.678 2.191 ;
     RECT  88.668 2.143 91.314 2.191 ;
     RECT  28.728 2.191 37.89 2.203 ;
     RECT  38.736 2.191 41.058 2.203 ;
     RECT  25.38 1.099 25.398 2.227 ;
     RECT  56.304 2.191 60.318 2.227 ;
     RECT  61.164 2.191 62.658 2.227 ;
     RECT  68.364 2.191 69.57 2.227 ;
     RECT  70.38 2.191 71.478 2.227 ;
     RECT  3.78 2.191 13.698 2.251 ;
     RECT  27.684 2.191 27.99 2.251 ;
     RECT  28.728 2.203 41.058 2.251 ;
     RECT  47.124 2.191 55.53 2.251 ;
     RECT  56.304 2.227 62.658 2.251 ;
     RECT  63.432 2.191 64.746 2.251 ;
     RECT  85.968 1.723 86.562 2.251 ;
     RECT  87.3 2.191 87.75 2.251 ;
     RECT  88.668 2.191 91.926 2.251 ;
     RECT  3.78 2.251 14.022 2.263 ;
     RECT  15.048 2.101 16.002 2.263 ;
     RECT  21.168 2.191 21.906 2.263 ;
     RECT  22.68 2.191 24.57 2.263 ;
     RECT  25.38 2.227 25.47 2.263 ;
     RECT  26.244 2.191 26.55 2.263 ;
     RECT  47.124 2.251 64.746 2.263 ;
     RECT  65.628 2.143 67.305 2.263 ;
     RECT  68.364 2.227 71.478 2.263 ;
     RECT  72.36 2.191 84.582 2.263 ;
     RECT  85.968 2.251 87.75 2.263 ;
     RECT  16.884 2.191 20.034 2.299 ;
     RECT  20.772 2.263 26.55 2.299 ;
     RECT  42.012 2.191 46.386 2.299 ;
     RECT  47.124 2.263 67.374 2.299 ;
     RECT  14.94 2.263 16.002 2.371 ;
     RECT  16.884 2.299 26.55 2.371 ;
     RECT  27.684 2.251 41.058 2.371 ;
     RECT  42.012 2.299 67.374 2.371 ;
     RECT  2.415 2.143 2.505 2.413 ;
     RECT  3.42 2.263 14.022 2.461 ;
     RECT  14.94 2.371 26.55 2.461 ;
     RECT  27.288 2.371 41.058 2.461 ;
     RECT  42.012 2.371 67.554 2.461 ;
     RECT  88.56 2.251 91.926 2.461 ;
     RECT  88.56 2.461 92.322 2.605 ;
     RECT  3.42 2.461 26.55 2.641 ;
     RECT  27.288 2.461 67.554 2.641 ;
     RECT  68.328 2.263 84.582 2.641 ;
     RECT  85.32 2.263 87.75 2.641 ;
     RECT  88.56 2.605 92.394 2.641 ;
     RECT  3.42 2.641 87.75 2.731 ;
     RECT  88.488 2.641 92.394 2.731 ;
     RECT  3.42 2.731 92.394 3.029 ;
     RECT  3.564 3.029 92.394 3.839 ;
     RECT  3.564 3.839 92.142 3.847 ;
     RECT  3.528 3.847 92.142 4.109 ;
     RECT  5.148 4.109 91.998 4.145 ;
     RECT  5.148 4.145 91.962 4.649 ;
     RECT  3.528 4.109 4.122 4.843 ;
     RECT  5.148 4.649 91.782 4.843 ;
     RECT  3.528 4.843 91.782 4.919 ;
     RECT  4.896 4.919 91.782 6.845 ;
     RECT  3.528 4.919 4.122 6.881 ;
     RECT  7.815 6.845 91.782 6.917 ;
     RECT  7.815 6.917 80.874 7.385 ;
     RECT  64.656 7.385 80.874 9.113 ;
     RECT  3.6 6.881 4.122 10.201 ;
     RECT  64.692 9.113 80.874 10.669 ;
     RECT  4.896 6.845 7.074 10.741 ;
     RECT  7.815 7.385 63.702 10.741 ;
     RECT  64.512 10.669 80.874 10.741 ;
     RECT  4.896 10.741 63.702 11.165 ;
     RECT  3.528 10.201 4.122 13.819 ;
     RECT  4.896 11.165 7.074 13.819 ;
     RECT  3.528 13.819 7.074 13.981 ;
     RECT  7.815 11.165 63.702 13.981 ;
     RECT  2.415 2.413 2.697 14.101 ;
     RECT  3.528 13.981 63.702 14.101 ;
     RECT  2.415 14.101 63.702 14.141 ;
     RECT  3.528 14.141 7.074 14.639 ;
     RECT  3.528 14.639 4.158 14.675 ;
     RECT  2.415 14.141 2.697 17.989 ;
     RECT  3.528 14.675 4.122 17.989 ;
     RECT  2.415 17.989 4.122 18.029 ;
     RECT  4.896 14.639 7.074 18.031 ;
     RECT  7.815 14.141 63.702 18.031 ;
     RECT  4.896 18.031 63.702 18.121 ;
     RECT  4.86 18.121 63.702 18.221 ;
     RECT  92.52 18.571 92.538 18.725 ;
     RECT  93.492 18.715 93.51 18.761 ;
     RECT  81.648 6.917 91.782 19.679 ;
     RECT  2.415 18.029 2.697 21.883 ;
     RECT  2.304 21.883 2.697 22.235 ;
     RECT  2.415 22.235 2.697 25.915 ;
     RECT  2.304 25.915 2.697 26.015 ;
     RECT  0.216 33.547 0.234 33.725 ;
     RECT  3.528 18.029 4.122 35.323 ;
     RECT  4.896 18.221 63.702 35.323 ;
     RECT  3.528 35.323 63.702 36.461 ;
     RECT  2.415 26.015 2.697 37.579 ;
     RECT  2.412 37.579 2.697 37.625 ;
     RECT  3.528 36.461 4.122 37.741 ;
     RECT  3.456 37.741 4.122 37.895 ;
     RECT  3.528 37.895 4.122 41.323 ;
     RECT  2.415 37.625 2.697 41.521 ;
     RECT  3.456 41.323 4.122 41.521 ;
     RECT  2.415 41.521 4.122 41.611 ;
     RECT  2.304 41.611 4.122 41.675 ;
     RECT  2.415 41.675 4.122 41.945 ;
     RECT  3.528 41.945 4.122 45.019 ;
     RECT  3.528 45.019 4.158 45.571 ;
     RECT  4.896 36.461 63.702 45.571 ;
     RECT  3.528 45.571 63.702 45.689 ;
     RECT  81.648 19.679 91.494 46.651 ;
     RECT  4.896 45.689 63.702 46.747 ;
     RECT  64.476 10.741 80.874 46.747 ;
     RECT  4.896 46.747 80.874 46.769 ;
     RECT  81.648 46.651 91.998 47.323 ;
     RECT  53.784 46.769 80.874 47.461 ;
     RECT  81.612 47.323 91.998 47.461 ;
     RECT  94.032 47.515 94.05 47.579 ;
     RECT  4.896 46.769 53.046 47.899 ;
     RECT  53.784 47.461 91.998 47.899 ;
     RECT  4.896 47.899 91.998 48.119 ;
     RECT  3.528 45.689 4.122 48.191 ;
     RECT  5.076 48.119 5.346 48.389 ;
     RECT  6.084 48.119 91.998 48.389 ;
     RECT  26.64 48.389 91.998 48.433 ;
     RECT  26.64 48.433 92.106 48.497 ;
     RECT  3.528 48.191 4.086 48.929 ;
     RECT  3.996 48.929 4.086 49.081 ;
     RECT  5.076 48.389 5.202 49.081 ;
     RECT  3.996 49.081 5.202 49.351 ;
     RECT  6.084 48.389 25.758 49.351 ;
     RECT  2.415 41.945 2.697 49.387 ;
     RECT  3.996 49.351 25.758 49.421 ;
     RECT  5.976 49.421 25.758 49.469 ;
     RECT  2.412 49.387 2.697 49.505 ;
     RECT  6.084 49.469 25.758 53.227 ;
     RECT  2.415 49.505 2.697 53.257 ;
     RECT  6.012 53.227 25.758 53.285 ;
     RECT  2.412 53.257 2.697 53.309 ;
     RECT  2.415 53.309 2.697 53.401 ;
     RECT  3.996 49.421 5.202 53.401 ;
     RECT  2.415 53.401 5.202 53.555 ;
     RECT  3.996 53.555 5.202 57.001 ;
     RECT  6.084 53.285 25.758 57.001 ;
     RECT  2.415 53.555 2.697 57.301 ;
     RECT  2.415 57.301 2.826 57.341 ;
     RECT  3.996 57.001 25.758 57.569 ;
     RECT  3.996 57.569 5.202 61.231 ;
     RECT  3.708 61.231 5.202 61.385 ;
     RECT  3.744 61.385 5.202 61.655 ;
     RECT  2.415 57.341 2.697 65.083 ;
     RECT  2.412 65.083 2.697 65.165 ;
     RECT  2.415 65.165 2.697 65.281 ;
     RECT  3.996 61.655 5.202 65.281 ;
     RECT  2.415 65.281 5.202 65.435 ;
     RECT  2.415 65.435 2.697 69.115 ;
     RECT  2.304 69.115 2.697 69.215 ;
     RECT  3.996 65.435 5.202 69.331 ;
     RECT  3.564 69.331 5.202 69.485 ;
     RECT  3.996 69.485 5.202 72.841 ;
     RECT  3.636 72.841 5.202 72.959 ;
     RECT  26.784 48.497 92.106 76.315 ;
     RECT  93.492 76.315 93.51 76.379 ;
     RECT  26.784 76.315 92.574 76.469 ;
     RECT  2.415 69.215 2.697 76.855 ;
     RECT  2.412 76.855 2.697 76.925 ;
     RECT  3.996 72.959 5.202 76.939 ;
     RECT  6.084 57.569 25.758 76.939 ;
     RECT  3.996 76.939 25.758 77.279 ;
     RECT  3.996 77.279 5.202 80.629 ;
     RECT  6.084 77.279 25.758 80.629 ;
     RECT  3.996 80.629 25.758 80.789 ;
     RECT  3.996 80.789 5.202 80.941 ;
     RECT  3.96 80.941 5.202 81.095 ;
     RECT  2.415 76.925 2.697 84.721 ;
     RECT  3.996 81.095 5.202 84.721 ;
     RECT  2.415 84.721 5.202 84.811 ;
     RECT  2.304 84.811 5.202 84.839 ;
     RECT  2.304 84.839 2.697 84.875 ;
     RECT  2.415 84.875 2.697 88.699 ;
     RECT  26.784 76.469 92.106 88.747 ;
     RECT  2.304 88.699 2.697 88.763 ;
     RECT  2.415 88.763 2.697 88.771 ;
     RECT  3.996 84.839 5.202 88.771 ;
     RECT  2.415 88.771 5.202 88.925 ;
     RECT  3.42 88.925 5.202 89.195 ;
     RECT  6.084 80.789 25.758 89.401 ;
     RECT  26.604 88.747 92.106 89.401 ;
     RECT  3.996 89.195 5.202 89.899 ;
     RECT  6.084 89.401 92.106 89.899 ;
     RECT  3.996 89.899 92.106 90.121 ;
     RECT  3.996 90.121 92.25 90.239 ;
     RECT  3.996 90.239 92.214 90.779 ;
     RECT  2.415 88.925 2.697 91.561 ;
     RECT  3.996 90.779 91.998 91.561 ;
     RECT  2.415 91.561 91.998 91.589 ;
     RECT  2.415 91.589 91.926 91.613 ;
     RECT  3.816 91.613 91.926 92.399 ;
     RECT  2.415 91.613 2.697 92.627 ;
     RECT  3.852 92.399 91.926 92.669 ;
     RECT  18.216 92.669 22.986 92.675 ;
     RECT  15.372 92.669 16.938 92.705 ;
     RECT  18.216 92.675 19.818 92.705 ;
     RECT  31.716 92.669 33.75 92.705 ;
     RECT  42.264 92.669 43.722 92.705 ;
     RECT  80.604 92.669 81.846 92.705 ;
     RECT  86.328 92.669 91.782 92.705 ;
     RECT  4.068 92.669 5.094 92.741 ;
     RECT  5.904 92.669 6.21 92.741 ;
     RECT  7.815 92.669 11.502 92.741 ;
     RECT  12.384 92.669 14.058 92.741 ;
     RECT  15.804 92.705 16.938 92.741 ;
     RECT  18.216 92.705 19.53 92.741 ;
     RECT  20.844 92.675 22.986 92.741 ;
     RECT  23.796 92.669 24.498 92.741 ;
     RECT  25.56 92.669 28.494 92.741 ;
     RECT  34.56 92.669 35.262 92.741 ;
     RECT  36.036 92.669 36.054 92.741 ;
     RECT  42.264 92.705 42.822 92.741 ;
     RECT  43.704 92.705 43.722 92.741 ;
     RECT  47.628 92.669 48.006 92.741 ;
     RECT  53.28 92.669 53.838 92.741 ;
     RECT  58.464 92.669 60.102 92.741 ;
     RECT  61.164 92.669 64.026 92.741 ;
     RECT  65.268 92.669 65.286 92.741 ;
     RECT  66.024 92.669 67.626 92.741 ;
     RECT  68.436 92.669 69.462 92.741 ;
     RECT  70.344 92.669 70.506 92.741 ;
     RECT  74.952 92.669 75.222 92.741 ;
     RECT  80.748 92.705 81.846 92.741 ;
     RECT  85.14 92.669 85.374 92.741 ;
     RECT  86.328 92.705 87.354 92.741 ;
     RECT  88.74 92.705 90.666 92.741 ;
     RECT  80.748 92.741 80.874 92.777 ;
     RECT  42.804 92.741 42.822 92.813 ;
     RECT  9.576 92.741 11.502 92.849 ;
     RECT  20.88 92.741 22.986 92.849 ;
     RECT  31.824 92.705 33.75 92.849 ;
     RECT  36.828 92.669 37.53 92.849 ;
     RECT  38.376 92.669 38.718 92.849 ;
     RECT  39.672 92.669 41.166 92.849 ;
     RECT  44.568 92.669 44.586 92.849 ;
     RECT  45.576 92.669 46.314 92.849 ;
     RECT  53.676 92.741 53.694 92.849 ;
     RECT  56.376 92.669 57.006 92.849 ;
     RECT  70.488 92.741 70.506 92.849 ;
     RECT  76.284 92.669 76.374 92.849 ;
     RECT  77.148 92.669 79.722 92.849 ;
     RECT  81.828 92.741 81.846 92.849 ;
     RECT  83.304 92.669 84.33 92.849 ;
     RECT  88.74 92.741 90.558 92.849 ;
     RECT  4.068 92.741 4.482 92.861 ;
     RECT  7.056 92.669 7.074 92.861 ;
     RECT  7.815 92.741 8.802 92.861 ;
     RECT  31.824 92.849 33.03 92.861 ;
     RECT  58.464 92.741 59.166 92.861 ;
     RECT  63.432 92.741 64.026 92.861 ;
     RECT  66.816 92.741 67.626 92.861 ;
     RECT  77.148 92.849 78.786 92.861 ;
     RECT  80.856 92.777 80.874 92.861 ;
     RECT  86.328 92.741 86.346 92.861 ;
     RECT  87.336 92.741 87.354 92.861 ;
     RECT  90.216 92.849 90.558 92.861 ;
     RECT  2.415 92.627 2.505 92.897 ;
     RECT  7.815 92.861 8.226 92.897 ;
     RECT  67.215 92.861 67.626 92.897 ;
     RECT  12.564 92.741 13.554 92.909 ;
     RECT  15.804 92.741 15.822 92.909 ;
     RECT  16.56 92.741 16.938 92.909 ;
     RECT  20.88 92.849 21.222 92.909 ;
     RECT  22.176 92.849 22.626 92.909 ;
     RECT  23.796 92.741 24.354 92.909 ;
     RECT  47.988 92.741 48.006 92.909 ;
     RECT  49.284 92.669 51.354 92.909 ;
     RECT  52.092 92.669 52.11 92.909 ;
     RECT  58.464 92.861 58.482 92.909 ;
     RECT  60.084 92.741 60.102 92.909 ;
     RECT  61.164 92.741 62.19 92.909 ;
     RECT  63.432 92.861 63.45 92.909 ;
     RECT  68.724 92.741 69.462 92.909 ;
     RECT  77.688 92.861 78.786 92.909 ;
     RECT  68.868 92.909 69.462 92.957 ;
     RECT  13.176 92.909 13.554 93.005 ;
     RECT  23.976 92.909 24.354 93.005 ;
     RECT  34.704 92.741 35.262 93.005 ;
     RECT  40.104 92.849 41.166 93.005 ;
     RECT  61.524 92.909 62.19 93.005 ;
     RECT  83.304 92.849 84.222 93.005 ;
     RECT  88.74 92.849 89.154 93.005 ;
     RECT  7.956 92.897 8.226 93.053 ;
     RECT  13.176 93.005 13.374 93.053 ;
     RECT  18.216 92.741 19.386 93.053 ;
     RECT  23.976 93.005 24.174 93.053 ;
     RECT  29.376 92.669 30.15 93.053 ;
     RECT  34.704 93.005 34.974 93.053 ;
     RECT  40.176 93.005 41.166 93.053 ;
     RECT  45.576 92.849 45.774 93.053 ;
     RECT  50.976 92.909 51.354 93.053 ;
     RECT  56.376 92.849 56.826 93.053 ;
     RECT  61.524 93.005 61.974 93.053 ;
     RECT  67.356 92.897 67.626 93.053 ;
     RECT  71.748 92.669 73.026 93.053 ;
     RECT  77.94 92.909 78.174 93.053 ;
     RECT  83.556 93.005 84.222 93.053 ;
     RECT  88.74 93.005 88.794 93.053 ;
     RECT  40.176 93.053 40.194 93.101 ;
     RECT  56.808 93.053 56.826 93.101 ;
     RECT  67.536 93.053 67.626 93.101 ;
     RECT  67.608 93.101 67.626 93.149 ;
     RECT  88.776 93.053 88.794 93.149 ;
     RECT  9.612 92.849 9.63 93.533 ;
     RECT  11.484 92.849 11.502 93.533 ;
     RECT  19.368 93.053 19.386 93.533 ;
     RECT  25.56 92.741 26.226 93.533 ;
     RECT  28.476 92.741 28.494 93.533 ;
     RECT  31.824 92.861 31.842 93.533 ;
     RECT  38.376 92.849 38.394 93.533 ;
     RECT  49.392 92.909 49.41 93.533 ;
     RECT  54.684 92.669 54.702 93.533 ;
     RECT  66.024 92.741 66.042 93.533 ;
     RECT  68.868 92.957 68.886 93.533 ;
     RECT  71.748 93.053 72.594 93.533 ;
     RECT  75.024 92.741 75.222 93.533 ;
     RECT  4.392 92.861 4.41 94.109 ;
     RECT  6.192 92.741 6.21 94.109 ;
     RECT  16.92 92.909 16.938 94.109 ;
     RECT  18.216 93.053 18.234 94.109 ;
     RECT  20.88 92.909 20.898 94.109 ;
     RECT  22.176 92.909 22.194 94.109 ;
     RECT  25.56 93.533 25.578 94.109 ;
     RECT  30.132 93.053 30.15 94.109 ;
     RECT  33.012 92.861 33.03 94.109 ;
     RECT  37.332 92.849 37.35 94.109 ;
     RECT  41.04 93.053 41.166 94.109 ;
     RECT  51.336 93.053 51.354 94.109 ;
     RECT  61.524 93.053 61.542 94.109 ;
     RECT  72.288 93.533 72.306 94.109 ;
     RECT  75.204 93.533 75.222 94.109 ;
     RECT  76.284 92.849 76.302 94.109 ;
     RECT  84.204 93.053 84.222 94.109 ;
     RECT  85.356 92.741 85.374 94.109 ;
     RECT  90.54 92.861 90.558 94.109 ;
     RECT  41.04 94.109 41.058 94.157 ;
     RECT  36.216 94.795 36.234 94.925 ;
     RECT  56.916 94.795 56.934 94.925 ;
     RECT  84.168 94.795 84.186 94.925 ;
     RECT  85.968 94.795 85.986 94.925 ;
     RECT  88.596 94.795 88.614 94.925 ;
    LAYER M4 ;
     RECT  0.229 47.664 2.408 47.688 ;
     RECT  2.408 2.148 2.512 92.892 ;
     RECT  2.512 2.418 2.704 92.622 ;
     RECT  2.704 14.112 2.837 14.136 ;
     RECT  2.704 18 2.837 18.024 ;
     RECT  2.704 57.312 2.837 57.336 ;
     RECT  3.769 1.68 4.057 1.704 ;
     RECT  3.769 61.248 4.069 61.272 ;
     RECT  2.704 91.584 4.165 91.608 ;
     RECT  4.057 1.104 4.201 1.704 ;
     RECT  4.069 61.248 4.211 61.368 ;
     RECT  2.704 88.8 4.211 88.824 ;
     RECT  3.877 10.032 4.213 10.056 ;
     RECT  4.129 45.024 4.213 45.048 ;
     RECT  4.165 90.624 4.249 91.608 ;
     RECT  4.213 10.032 4.259 10.872 ;
     RECT  4.211 61.344 4.259 61.368 ;
     RECT  4.165 57.552 4.385 57.576 ;
     RECT  4.249 91.584 4.421 91.608 ;
     RECT  4.201 0.192 4.445 1.704 ;
     RECT  4.057 92.832 4.499 92.856 ;
     RECT  4.445 0.192 4.529 1.752 ;
     RECT  3.841 4.32 4.7 4.344 ;
     RECT  4.529 0.192 4.787 1.704 ;
     RECT  4.7 4.32 4.787 4.872 ;
     RECT  4.381 94.08 4.787 94.104 ;
     RECT  4.748 36.432 4.835 36.456 ;
     RECT  2.704 41.328 4.835 41.352 ;
     RECT  4.213 64.992 4.961 65.016 ;
     RECT  4.777 35.328 5.065 35.352 ;
     RECT  4.885 76.704 5.125 76.728 ;
     RECT  5.125 76.704 5.171 77.256 ;
     RECT  4.787 4.32 5.177 4.344 ;
     RECT  4.213 5.856 5.177 5.88 ;
     RECT  4.787 1.632 5.219 1.704 ;
     RECT  3.877 25.872 5.219 25.896 ;
     RECT  5.132 29.712 5.219 29.736 ;
     RECT  5.065 35.328 5.219 35.928 ;
     RECT  5.173 33.504 5.285 33.528 ;
     RECT  5.219 1.632 5.363 1.656 ;
     RECT  4.309 72.624 5.411 72.648 ;
     RECT  5.516 80.64 5.603 80.664 ;
     RECT  4.921 57.216 5.677 57.24 ;
     RECT  5.171 76.944 5.681 77.256 ;
     RECT  5.677 57.024 5.699 57.24 ;
     RECT  5.681 76.944 5.699 76.968 ;
     RECT  5.612 89.904 5.713 89.928 ;
     RECT  5.713 89.904 5.714 89.976 ;
     RECT  5.804 49.392 5.891 49.416 ;
     RECT  4.597 92.352 6.073 92.52 ;
     RECT  5.699 57.024 6.083 57.048 ;
     RECT  5.845 53.232 6.105 53.256 ;
     RECT  4.787 0.192 6.133 0.6 ;
     RECT  5.557 84.384 6.221 84.408 ;
     RECT  6.181 94.08 6.467 94.104 ;
     RECT  6.133 0.192 6.505 1.224 ;
     RECT  5.714 89.952 6.541 89.976 ;
     RECT  6.505 0.192 6.611 1.704 ;
     RECT  6.572 17.808 6.659 17.832 ;
     RECT  6.073 21.648 6.659 21.672 ;
     RECT  6.649 5.472 6.685 5.496 ;
     RECT  4.789 37.44 6.761 37.464 ;
     RECT  6.685 4.608 6.86 5.496 ;
     RECT  2.704 47.664 6.901 47.688 ;
     RECT  6.541 89.952 6.973 90.648 ;
     RECT  6.073 92.352 7.045 92.568 ;
     RECT  6.973 89.472 7.361 90.648 ;
     RECT  6.611 0.192 7.409 1.176 ;
     RECT  6.86 3.888 7.429 5.496 ;
     RECT  7.361 89.472 7.429 91.224 ;
     RECT  7.045 92.352 7.429 92.856 ;
     RECT  7.429 89.472 7.477 92.856 ;
     RECT  7.477 2.688 7.525 2.712 ;
     RECT  7.525 2.688 7.573 2.808 ;
     RECT  7.573 2.688 7.621 2.904 ;
     RECT  7.429 3.888 7.621 5.784 ;
     RECT  7.477 89.328 7.621 92.856 ;
     RECT  4.525 13.824 7.669 13.848 ;
     RECT  7.621 89.328 7.669 93 ;
     RECT  7.409 0.192 7.777 0.408 ;
     RECT  7.621 2.688 7.808 6.312 ;
     RECT  4.259 10.848 7.808 10.872 ;
     RECT  7.669 13.824 7.808 14.136 ;
     RECT  7.669 19.248 7.808 19.272 ;
     RECT  5.219 35.328 7.808 35.352 ;
     RECT  6.901 47.664 7.808 47.928 ;
     RECT  7.477 49.584 7.808 49.608 ;
     RECT  5.365 69.312 7.808 69.336 ;
     RECT  7.669 88.896 7.808 93 ;
     RECT  7.808 2.148 7.861 93 ;
     RECT  7.861 1.68 8.104 93.048 ;
     RECT  8.104 13.824 8.201 14.28 ;
     RECT  8.104 88.368 8.237 93.048 ;
     RECT  8.104 46.128 8.425 46.152 ;
     RECT  7.777 0.288 8.435 0.408 ;
     RECT  8.104 1.68 8.435 1.704 ;
     RECT  8.104 47.664 8.435 48.312 ;
     RECT  8.104 2.88 8.489 6.408 ;
     RECT  8.237 88.368 8.633 92.856 ;
     RECT  8.773 1.104 8.915 1.128 ;
     RECT  8.435 47.664 9.313 47.688 ;
     RECT  8.489 3.408 9.349 6.408 ;
     RECT  9.313 47.28 9.397 47.688 ;
     RECT  9.397 47.664 9.457 47.688 ;
     RECT  9.397 51.888 9.497 51.912 ;
     RECT  9.349 3.408 9.539 6.84 ;
     RECT  8.633 88.8 9.539 92.856 ;
     RECT  9.457 47.664 9.541 47.928 ;
     RECT  9.539 88.896 9.58 92.856 ;
     RECT  9.58 91.2 9.601 92.856 ;
     RECT  8.104 19.248 9.817 19.272 ;
     RECT  9.539 3.408 9.82 6.504 ;
     RECT  9.733 1.728 9.877 1.752 ;
     RECT  8.201 14.256 9.889 14.28 ;
     RECT  9.601 91.2 9.923 93.528 ;
     RECT  9.889 14.256 9.929 14.808 ;
     RECT  9.82 3.408 10.069 6.312 ;
     RECT  9.877 1.728 10.076 1.8 ;
     RECT  10.069 2.88 10.076 6.312 ;
     RECT  9.923 91.2 10.225 92.568 ;
     RECT  10.076 1.728 10.249 6.312 ;
     RECT  10.249 1.104 10.355 6.312 ;
     RECT  9.817 19.248 10.433 19.8 ;
     RECT  10.393 22.944 10.541 22.968 ;
     RECT  9.58 88.896 10.541 89.736 ;
     RECT  10.225 91.248 10.685 92.568 ;
     RECT  10.355 1.728 10.793 6.312 ;
     RECT  10.685 91.728 10.801 92.568 ;
     RECT  10.793 4.128 10.837 6.312 ;
     RECT  10.793 1.728 10.865 2.856 ;
     RECT  10.844 46.656 10.931 46.68 ;
     RECT  10.933 21.504 11.324 21.528 ;
     RECT  11.324 21.12 11.333 21.528 ;
     RECT  11.333 21.12 11.365 21.144 ;
     RECT  11.365 20.352 11.411 21.144 ;
     RECT  10.433 19.248 11.413 19.272 ;
     RECT  10.541 89.424 11.473 89.736 ;
     RECT  10.801 92.352 11.473 92.568 ;
     RECT  10.837 4.128 11.477 6.36 ;
     RECT  11.413 18.288 11.545 19.272 ;
     RECT  11.411 20.352 11.545 20.376 ;
     RECT  9.541 47.664 11.545 47.688 ;
     RECT  10.865 1.728 11.581 1.752 ;
     RECT  11.581 1.68 11.747 1.752 ;
     RECT  10.865 2.784 11.797 2.856 ;
     RECT  11.545 47.664 11.797 48.504 ;
     RECT  11.797 46.704 11.843 48.504 ;
     RECT  11.843 46.704 11.891 47.688 ;
     RECT  11.747 1.728 11.948 1.752 ;
     RECT  11.797 2.784 11.948 2.904 ;
     RECT  11.948 1.728 11.981 2.904 ;
     RECT  11.473 89.424 11.987 90.072 ;
     RECT  11.545 18.288 11.989 20.376 ;
     RECT  11.989 18.24 12.017 20.376 ;
     RECT  11.981 2.256 12.035 2.904 ;
     RECT  11.473 92.352 12.035 93.528 ;
     RECT  11.477 4.512 12.181 6.36 ;
     RECT  10.748 17.088 12.277 17.112 ;
     RECT  12.017 18.24 12.277 19.368 ;
     RECT  12.14 3.216 12.469 3.24 ;
     RECT  12.181 4.512 12.469 6.936 ;
     RECT  12.401 0.192 12.485 0.216 ;
     RECT  9.929 14.784 12.733 14.808 ;
     RECT  12.469 3.216 13.093 6.936 ;
     RECT  12.277 17.088 13.093 19.368 ;
     RECT  13.093 2.784 13.121 6.936 ;
     RECT  12.017 20.352 13.129 20.376 ;
     RECT  13.093 21.936 13.129 21.96 ;
     RECT  12.035 92.352 13.141 92.904 ;
     RECT  13.121 2.016 13.208 6.936 ;
     RECT  12.733 14.736 13.208 14.808 ;
     RECT  13.093 16.512 13.208 19.368 ;
     RECT  13.129 20.352 13.208 21.96 ;
     RECT  11.891 47.328 13.208 47.688 ;
     RECT  11.987 89.424 13.208 89.736 ;
     RECT  13.165 90.912 13.208 90.936 ;
     RECT  13.141 92.352 13.208 93.048 ;
     RECT  13.208 2.016 13.385 93.048 ;
     RECT  13.285 0.288 13.477 0.312 ;
     RECT  13.385 2.016 13.477 93 ;
     RECT  13.477 1.92 13.504 93 ;
     RECT  13.477 0.288 13.561 0.36 ;
     RECT  13.504 92.352 13.565 93 ;
     RECT  13.561 0.192 13.601 0.36 ;
     RECT  13.601 0.192 13.619 0.312 ;
     RECT  13.619 0.192 13.645 0.216 ;
     RECT  13.504 1.92 13.667 6.888 ;
     RECT  13.667 3.984 13.673 6.888 ;
     RECT  13.504 14.736 13.709 14.76 ;
     RECT  13.667 1.92 13.715 2.28 ;
     RECT  13.673 4.08 13.715 6.888 ;
     RECT  13.504 18.192 13.745 21.096 ;
     RECT  13.715 4.512 13.781 6.888 ;
     RECT  13.745 18.192 13.853 18.216 ;
     RECT  13.715 2.256 14.044 2.28 ;
     RECT  13.504 47.328 14.069 47.688 ;
     RECT  13.745 19.2 14.105 21.096 ;
     RECT  13.504 88.896 14.435 89.736 ;
     RECT  14.105 19.2 14.465 20.184 ;
     RECT  13.504 90.912 14.465 90.936 ;
     RECT  14.533 17.664 14.641 17.688 ;
     RECT  14.641 17.136 14.645 17.688 ;
     RECT  13.781 4.512 14.749 6.36 ;
     RECT  14.749 4.224 14.876 6.36 ;
     RECT  14.876 3.84 14.969 6.36 ;
     RECT  14.969 5.712 15.001 6.36 ;
     RECT  14.435 89.424 15.001 89.736 ;
     RECT  14.645 17.136 15.037 17.16 ;
     RECT  15.001 5.712 15.085 6.6 ;
     RECT  15.085 5.712 15.293 6.312 ;
     RECT  13.565 92.352 15.301 92.424 ;
     RECT  15.301 92.352 15.589 92.52 ;
     RECT  15.001 89.424 15.649 89.976 ;
     RECT  15.445 1.728 15.653 1.752 ;
     RECT  14.969 3.84 15.733 4.296 ;
     RECT  14.069 47.664 15.781 47.688 ;
     RECT  15.325 21.072 15.793 21.096 ;
     RECT  15.589 92.352 15.793 92.568 ;
     RECT  14.465 19.2 15.797 20.088 ;
     RECT  15.793 21.072 15.829 21.672 ;
     RECT  15.685 15.936 15.925 15.96 ;
     RECT  15.037 17.088 15.925 17.16 ;
     RECT  15.925 15.936 15.971 17.16 ;
     RECT  15.733 3.408 16.021 4.296 ;
     RECT  15.293 5.712 16.021 6.12 ;
     RECT  15.829 21.072 16.049 22.2 ;
     RECT  15.797 19.2 16.081 19.224 ;
     RECT  15.781 47.664 16.109 47.928 ;
     RECT  15.971 16.8 16.193 17.16 ;
     RECT  16.109 47.664 16.193 48.504 ;
     RECT  16.021 3.408 16.373 6.12 ;
     RECT  16.193 17.04 16.405 17.16 ;
     RECT  16.081 18.912 16.405 19.224 ;
     RECT  16.049 21.072 16.549 21.096 ;
     RECT  16.373 3.936 16.697 6.12 ;
     RECT  16.405 17.04 16.733 19.224 ;
     RECT  16.733 17.04 16.739 17.832 ;
     RECT  16.837 2.736 16.979 2.904 ;
     RECT  16.739 17.04 16.979 17.064 ;
     RECT  15.793 92.352 16.979 92.904 ;
     RECT  16.873 14.832 16.985 14.856 ;
     RECT  16.549 20.4 16.985 21.096 ;
     RECT  16.733 19.056 17.027 19.224 ;
     RECT  16.985 20.4 17.065 20.568 ;
     RECT  16.909 94.08 17.123 94.104 ;
     RECT  16.193 47.664 17.221 47.688 ;
     RECT  15.649 89.424 17.221 90.072 ;
     RECT  17.221 47.664 17.309 47.928 ;
     RECT  17.233 49.008 17.317 49.032 ;
     RECT  17.221 89.424 17.372 90.696 ;
     RECT  17.077 0.192 17.381 0.216 ;
     RECT  17.372 89.424 17.389 90.936 ;
     RECT  17.389 90.912 17.459 90.936 ;
     RECT  16.697 4.128 17.477 6.12 ;
     RECT  17.389 89.424 17.485 89.736 ;
     RECT  17.477 4.128 17.557 6.216 ;
     RECT  15.001 7.68 17.557 7.704 ;
     RECT  17.485 89.328 18.181 89.736 ;
     RECT  18.188 94.08 18.275 94.104 ;
     RECT  17.309 47.664 18.313 47.688 ;
     RECT  17.621 1.728 18.373 1.752 ;
     RECT  18.373 1.728 18.389 1.8 ;
     RECT  18.277 0.336 18.421 0.36 ;
     RECT  18.181 88.896 18.469 89.736 ;
     RECT  16.979 92.352 18.469 92.52 ;
     RECT  18.469 91.872 18.476 92.52 ;
     RECT  16.979 2.88 18.529 2.904 ;
     RECT  17.557 4.128 18.529 7.704 ;
     RECT  18.389 1.776 18.608 1.8 ;
     RECT  18.529 2.88 18.608 7.704 ;
     RECT  17.485 16.656 18.608 16.68 ;
     RECT  17.027 19.056 18.608 19.08 ;
     RECT  17.065 20.4 18.608 20.424 ;
     RECT  18.313 47.664 18.608 48.504 ;
     RECT  18.469 88.896 18.608 90.072 ;
     RECT  18.476 91.872 18.608 93 ;
     RECT  18.608 1.776 18.661 93 ;
     RECT  18.661 1.776 18.904 93.048 ;
     RECT  18.421 0.288 18.949 0.36 ;
     RECT  18.949 0.288 19.043 0.6 ;
     RECT  19.043 0.576 19.073 0.6 ;
     RECT  18.904 91.728 19.091 93.048 ;
     RECT  18.904 16.56 19.289 16.68 ;
     RECT  19.34 93.504 19.427 93.528 ;
     RECT  18.904 2.88 19.433 7.704 ;
     RECT  19.381 1.728 19.469 1.752 ;
     RECT  19.433 3.888 19.613 7.704 ;
     RECT  18.904 19.056 19.757 19.896 ;
     RECT  18.904 88.944 19.763 90.648 ;
     RECT  18.904 47.664 19.765 48.456 ;
     RECT  19.763 89.328 19.9 90.648 ;
     RECT  19.9 89.424 19.909 90.648 ;
     RECT  19.091 91.728 19.909 92.472 ;
     RECT  19.613 3.888 20.009 6.456 ;
     RECT  19.909 89.424 20.293 92.472 ;
     RECT  20.293 89.424 20.348 92.52 ;
     RECT  19.433 2.88 20.645 2.904 ;
     RECT  20.348 89.424 20.729 92.664 ;
     RECT  20.677 49.008 20.765 49.032 ;
     RECT  19.757 19.056 20.773 19.224 ;
     RECT  19.289 16.56 20.819 16.584 ;
     RECT  20.773 18.144 20.945 19.224 ;
     RECT  20.645 2.304 21.017 2.904 ;
     RECT  20.945 19.056 21.017 19.224 ;
     RECT  20.729 89.424 21.061 89.736 ;
     RECT  20.009 4.176 21.109 6.456 ;
     RECT  19.613 7.68 21.109 7.704 ;
     RECT  20.869 94.08 21.155 94.104 ;
     RECT  19.765 47.664 21.157 47.928 ;
     RECT  20.729 90.912 21.193 92.664 ;
     RECT  21.157 1.68 21.299 1.704 ;
     RECT  21.193 90.912 21.299 92.904 ;
     RECT  21.061 41.04 21.413 41.064 ;
     RECT  21.109 4.176 21.581 7.704 ;
     RECT  21.017 2.88 21.685 2.904 ;
     RECT  21.581 3.936 21.685 7.704 ;
     RECT  21.061 89.376 21.769 89.736 ;
     RECT  21.299 90.912 21.769 92.376 ;
     RECT  21.685 2.88 21.773 7.704 ;
     RECT  21.157 47.664 21.781 48.504 ;
     RECT  21.769 89.376 21.809 92.376 ;
     RECT  21.781 47.664 21.917 49.032 ;
     RECT  21.809 89.424 22.133 92.376 ;
     RECT  21.017 19.056 22.259 19.08 ;
     RECT  20.773 11.856 22.268 11.88 ;
     RECT  22.268 11.376 22.349 11.88 ;
     RECT  22.165 94.08 22.403 94.104 ;
     RECT  21.917 47.664 22.429 48.552 ;
     RECT  22.133 92.352 22.549 92.376 ;
     RECT  22.429 47.664 22.565 48.504 ;
     RECT  22.549 92.352 22.597 92.568 ;
     RECT  22.597 92.352 22.691 92.904 ;
     RECT  22.501 1.728 22.709 1.752 ;
     RECT  22.565 47.664 22.849 47.688 ;
     RECT  22.789 0.192 22.876 0.216 ;
     RECT  22.849 46.752 22.933 47.688 ;
     RECT  22.133 89.424 22.979 91.176 ;
     RECT  21.773 2.88 23.317 6.216 ;
     RECT  23.317 2.88 23.569 6.408 ;
     RECT  21.773 7.68 23.569 7.704 ;
     RECT  22.979 90.912 23.653 91.176 ;
     RECT  22.691 92.352 23.653 92.568 ;
     RECT  23.653 90.912 23.785 92.568 ;
     RECT  23.569 2.88 23.921 7.704 ;
     RECT  23.785 90.912 23.941 92.904 ;
     RECT  23.921 2.016 24.008 7.704 ;
     RECT  22.349 11.376 24.008 11.4 ;
     RECT  22.213 17.616 24.008 17.64 ;
     RECT  22.345 19.776 24.008 19.8 ;
     RECT  22.933 47.664 24.008 47.688 ;
     RECT  23.209 86.64 24.008 86.664 ;
     RECT  22.979 89.424 24.008 89.832 ;
     RECT  23.941 90.912 24.008 93.048 ;
     RECT  24.008 2.016 24.185 93.048 ;
     RECT  24.085 0.528 24.229 0.552 ;
     RECT  24.185 2.016 24.304 93 ;
     RECT  24.304 90.96 24.365 93 ;
     RECT  24.229 0.336 24.373 0.552 ;
     RECT  24.304 2.016 24.437 7.704 ;
     RECT  24.365 90.96 24.445 92.472 ;
     RECT  24.437 2.016 24.497 2.904 ;
     RECT  24.373 0.288 24.509 0.552 ;
     RECT  24.509 0.336 24.515 0.552 ;
     RECT  24.497 1.728 24.581 2.904 ;
     RECT  24.445 91.056 24.617 92.472 ;
     RECT  24.617 91.056 24.797 91.08 ;
     RECT  24.581 2.304 24.833 2.904 ;
     RECT  24.617 92.352 24.892 92.472 ;
     RECT  24.304 89.376 25.283 89.832 ;
     RECT  25.34 1.104 25.427 1.128 ;
     RECT  24.304 47.664 25.429 47.688 ;
     RECT  25.429 47.328 25.517 47.688 ;
     RECT  25.517 47.664 25.693 47.688 ;
     RECT  25.549 94.08 25.715 94.104 ;
     RECT  24.833 2.88 25.724 2.904 ;
     RECT  24.437 4.176 25.724 7.704 ;
     RECT  25.693 47.664 25.777 47.928 ;
     RECT  25.724 2.88 26.149 7.704 ;
     RECT  24.304 19.776 26.195 19.8 ;
     RECT  26.149 2.88 26.237 7.8 ;
     RECT  26.197 93.504 26.291 93.528 ;
     RECT  26.237 2.88 26.533 7.704 ;
     RECT  26.389 1.152 26.561 1.176 ;
     RECT  24.892 92.352 26.578 92.424 ;
     RECT  25.283 89.424 26.593 89.448 ;
     RECT  26.578 92.352 26.723 92.472 ;
     RECT  26.593 88.752 27.313 89.448 ;
     RECT  27.313 88.752 27.389 90.216 ;
     RECT  26.533 2.208 27.781 7.704 ;
     RECT  27.781 2.16 27.845 7.704 ;
     RECT  26.723 92.352 27.925 92.424 ;
     RECT  27.845 1.728 27.928 7.704 ;
     RECT  27.928 1.68 28.067 7.704 ;
     RECT  27.925 92.352 28.067 92.472 ;
     RECT  28.067 92.352 28.453 92.424 ;
     RECT  25.777 47.664 28.549 47.688 ;
     RECT  28.465 93.504 28.643 93.528 ;
     RECT  27.389 89.376 28.885 90.216 ;
     RECT  28.885 89.376 28.969 90.6 ;
     RECT  28.453 91.776 28.969 92.424 ;
     RECT  28.969 89.376 29.185 92.424 ;
     RECT  29.185 89.28 29.221 92.424 ;
     RECT  28.067 2.112 29.317 7.704 ;
     RECT  29.317 1.728 29.408 7.704 ;
     RECT  24.304 17.616 29.408 17.64 ;
     RECT  28.549 47.664 29.408 47.928 ;
     RECT  24.304 78.624 29.408 78.648 ;
     RECT  29.221 89.28 29.408 93.048 ;
     RECT  28.837 0.288 29.651 0.312 ;
     RECT  29.408 1.728 29.704 93.048 ;
     RECT  29.704 92.352 29.837 93.048 ;
     RECT  29.704 47.664 29.945 47.928 ;
     RECT  29.704 1.728 30.233 7.704 ;
     RECT  30.121 94.08 30.371 94.104 ;
     RECT  29.704 88.752 30.665 91.224 ;
     RECT  29.704 17.616 30.769 17.64 ;
     RECT  30.769 17.52 30.809 17.64 ;
     RECT  29.837 92.352 30.853 92.472 ;
     RECT  30.757 0.288 30.899 0.312 ;
     RECT  30.665 88.8 30.899 91.224 ;
     RECT  30.757 94.752 30.899 94.776 ;
     RECT  30.233 2.736 31.061 7.704 ;
     RECT  30.899 89.424 31.201 91.224 ;
     RECT  30.853 92.256 31.201 92.472 ;
     RECT  30.233 1.728 31.345 1.752 ;
     RECT  31.061 2.736 31.345 6.456 ;
     RECT  31.345 1.728 31.385 6.456 ;
     RECT  31.201 89.424 31.529 92.472 ;
     RECT  31.061 7.68 31.561 7.704 ;
     RECT  31.529 91.2 31.673 92.472 ;
     RECT  31.561 7.68 31.763 8.04 ;
     RECT  31.477 0.576 31.781 0.6 ;
     RECT  30.809 17.52 31.921 17.544 ;
     RECT  31.813 93.504 31.955 93.528 ;
     RECT  31.673 91.68 31.961 92.472 ;
     RECT  29.945 47.664 32.012 47.688 ;
     RECT  31.529 89.424 32.053 90.072 ;
     RECT  31.961 91.92 32.053 92.472 ;
     RECT  32.012 47.664 32.099 47.88 ;
     RECT  31.921 17.52 32.285 17.64 ;
     RECT  32.053 88.992 32.341 90.072 ;
     RECT  31.385 1.728 32.393 4.584 ;
     RECT  31.34 49.008 32.401 49.032 ;
     RECT  32.393 2.256 32.437 4.584 ;
     RECT  31.385 5.616 32.437 6.456 ;
     RECT  32.053 91.92 32.465 92.856 ;
     RECT  29.704 78.624 32.492 78.648 ;
     RECT  32.437 2.256 32.501 6.456 ;
     RECT  32.341 88.944 32.501 90.072 ;
     RECT  32.492 78.048 32.537 78.648 ;
     RECT  32.537 78.048 32.579 78.072 ;
     RECT  32.501 88.992 32.713 90.072 ;
     RECT  32.501 6.096 32.869 6.456 ;
     RECT  31.763 7.68 32.869 7.704 ;
     RECT  32.725 50.736 32.933 50.76 ;
     RECT  32.465 91.92 33.101 92.568 ;
     RECT  33.001 94.08 33.203 94.104 ;
     RECT  32.713 88.992 33.257 90.552 ;
     RECT  33.101 91.776 33.347 92.568 ;
     RECT  33.347 91.776 33.433 92.472 ;
     RECT  32.501 2.256 33.541 5.112 ;
     RECT  33.541 1.728 33.589 5.112 ;
     RECT  32.869 6.096 33.589 7.704 ;
     RECT  33.257 89.232 33.689 90.552 ;
     RECT  33.433 91.728 33.733 92.472 ;
     RECT  32.099 47.664 34.081 47.688 ;
     RECT  33.589 1.728 34.124 7.704 ;
     RECT  34.124 1.104 34.211 7.704 ;
     RECT  33.689 89.232 34.309 90.072 ;
     RECT  33.733 91.152 34.652 92.472 ;
     RECT  34.652 91.152 34.693 92.952 ;
     RECT  34.211 1.728 34.808 7.704 ;
     RECT  33.829 10.704 34.808 10.728 ;
     RECT  32.285 17.616 34.808 17.64 ;
     RECT  34.081 47.664 34.808 47.88 ;
     RECT  34.268 50.112 34.808 50.136 ;
     RECT  32.533 68.928 34.808 68.952 ;
     RECT  34.081 78.048 34.808 78.072 ;
     RECT  34.309 88.944 34.808 90.072 ;
     RECT  34.693 91.152 34.808 93.048 ;
     RECT  34.808 1.728 34.985 93.048 ;
     RECT  34.985 1.728 35.104 93 ;
     RECT  35.104 88.944 35.273 93 ;
     RECT  34.885 0.288 35.461 0.408 ;
     RECT  35.104 1.728 35.461 7.704 ;
     RECT  35.104 17.616 35.603 17.64 ;
     RECT  35.461 0.288 35.741 7.704 ;
     RECT  35.104 15.984 35.741 16.536 ;
     RECT  35.741 15.984 36.109 16.008 ;
     RECT  35.104 47.664 36.181 47.88 ;
     RECT  36.181 94.8 36.205 94.824 ;
     RECT  36.181 47.664 36.268 48.312 ;
     RECT  36.205 94.8 36.268 94.92 ;
     RECT  36.268 94.896 36.289 94.92 ;
     RECT  35.741 0.288 36.371 0.312 ;
     RECT  35.273 88.944 36.493 92.568 ;
     RECT  36.493 88.848 36.611 92.568 ;
     RECT  36.611 91.2 36.677 92.568 ;
     RECT  35.741 1.728 37.073 7.704 ;
     RECT  36.677 91.2 37.091 92.52 ;
     RECT  36.611 88.848 37.093 90.072 ;
     RECT  37.069 49.008 37.152 49.032 ;
     RECT  37.152 49.008 37.153 49.08 ;
     RECT  37.073 1.728 37.181 3 ;
     RECT  37.153 49.056 37.397 49.08 ;
     RECT  37.093 88.368 37.477 90.072 ;
     RECT  36.268 47.664 37.645 47.688 ;
     RECT  37.321 94.08 37.667 94.104 ;
     RECT  37.645 47.328 37.729 47.688 ;
     RECT  37.729 47.664 37.753 47.688 ;
     RECT  37.091 91.2 37.757 91.224 ;
     RECT  37.477 89.424 37.82 90.072 ;
     RECT  37.82 89.424 38.099 90.648 ;
     RECT  37.181 2.208 38.108 3 ;
     RECT  37.073 3.984 38.108 7.704 ;
     RECT  37.753 47.664 38.252 47.928 ;
     RECT  37.477 88.368 38.339 88.392 ;
     RECT  37.091 92.352 38.401 92.52 ;
     RECT  35.104 27.216 38.473 27.24 ;
     RECT  38.401 91.776 38.473 92.52 ;
     RECT  38.365 93.504 38.473 93.528 ;
     RECT  38.252 47.664 38.684 48.312 ;
     RECT  38.099 89.472 38.765 90.648 ;
     RECT  38.473 91.776 38.765 93.528 ;
     RECT  38.765 93.504 38.867 93.528 ;
     RECT  38.473 27.216 38.869 27.336 ;
     RECT  38.869 27.168 38.909 27.336 ;
     RECT  38.108 2.208 39.109 7.704 ;
     RECT  38.684 47.664 39.125 48.504 ;
     RECT  38.765 89.472 39.233 90.024 ;
     RECT  39.109 1.728 39.301 7.704 ;
     RECT  35.104 68.928 39.337 68.952 ;
     RECT  38.765 91.776 39.829 92.424 ;
     RECT  39.829 91.2 40.076 92.424 ;
     RECT  39.637 0.288 40.085 0.312 ;
     RECT  39.301 1.728 40.085 7.992 ;
     RECT  39.233 89.52 40.093 90.024 ;
     RECT  40.076 91.2 40.093 93 ;
     RECT  40.093 89.52 40.165 93 ;
     RECT  40.085 0.288 40.169 7.992 ;
     RECT  40.169 1.68 40.208 7.992 ;
     RECT  38.909 27.168 40.208 27.192 ;
     RECT  39.125 47.664 40.208 47.688 ;
     RECT  39.337 68.736 40.208 68.952 ;
     RECT  40.165 89.52 40.208 93.096 ;
     RECT  40.208 1.68 40.451 93.096 ;
     RECT  40.451 1.68 40.504 93 ;
     RECT  40.504 1.68 40.595 7.752 ;
     RECT  40.504 92.352 40.636 93 ;
     RECT  40.595 2.304 40.643 7.752 ;
     RECT  40.504 27.168 40.643 27.336 ;
     RECT  40.169 0.288 40.691 0.312 ;
     RECT  40.504 89.52 40.853 90.648 ;
     RECT  40.643 2.304 41.033 7.704 ;
     RECT  41.029 94.128 41.125 94.152 ;
     RECT  41.125 94.08 41.212 94.152 ;
     RECT  41.212 94.128 41.459 94.152 ;
     RECT  40.636 92.352 41.465 92.568 ;
     RECT  40.853 89.52 41.701 89.736 ;
     RECT  41.701 89.328 41.788 89.736 ;
     RECT  41.788 89.712 41.929 89.736 ;
     RECT  41.033 2.832 42.037 7.704 ;
     RECT  42.037 2.832 42.469 8.568 ;
     RECT  41.929 89.712 42.473 90.6 ;
     RECT  42.469 2.208 42.533 8.568 ;
     RECT  41.465 92.352 42.668 92.472 ;
     RECT  42.533 1.728 42.689 8.568 ;
     RECT  40.643 27.312 42.829 27.336 ;
     RECT  42.829 27.168 42.869 27.336 ;
     RECT  42.668 92.352 43.085 92.52 ;
     RECT  43.085 92.448 43.141 92.52 ;
     RECT  42.949 0.288 43.187 0.312 ;
     RECT  43.189 49.008 43.273 49.032 ;
     RECT  42.689 1.728 43.337 7.704 ;
     RECT  40.504 47.664 43.381 47.688 ;
     RECT  43.337 2.064 43.427 7.704 ;
     RECT  43.427 2.064 43.907 3.048 ;
     RECT  42.473 89.712 43.949 90.024 ;
     RECT  43.949 89.952 43.981 90.024 ;
     RECT  43.909 0.528 44.003 0.552 ;
     RECT  43.141 92.448 44.125 92.568 ;
     RECT  44.125 92.352 44.453 92.568 ;
     RECT  43.907 2.064 44.533 2.904 ;
     RECT  43.981 89.952 44.533 90.6 ;
     RECT  44.533 1.152 44.741 2.904 ;
     RECT  44.453 92.352 45.061 92.472 ;
     RECT  45.089 0.192 45.173 0.6 ;
     RECT  43.381 47.664 45.241 48.504 ;
     RECT  44.741 1.728 45.445 2.904 ;
     RECT  45.061 92.304 45.445 92.472 ;
     RECT  45.445 92.304 45.541 92.52 ;
     RECT  45.445 1.728 45.608 3.048 ;
     RECT  43.427 4.176 45.608 7.704 ;
     RECT  42.869 27.168 45.608 27.192 ;
     RECT  45.241 47.328 45.608 48.504 ;
     RECT  40.504 68.736 45.608 68.76 ;
     RECT  44.533 89.952 45.608 91.176 ;
     RECT  45.541 92.304 45.608 93.048 ;
     RECT  45.608 1.728 45.904 93.048 ;
     RECT  45.904 88.944 45.973 93.048 ;
     RECT  45.904 27.168 46.019 27.336 ;
     RECT  45.973 88.944 46.115 93.096 ;
     RECT  45.173 0.576 46.145 0.6 ;
     RECT  45.904 1.728 46.253 7.704 ;
     RECT  46.253 1.776 46.397 7.704 ;
     RECT  45.904 47.376 46.549 48.456 ;
     RECT  46.549 47.376 46.585 47.88 ;
     RECT  46.115 88.944 46.649 92.52 ;
     RECT  45.904 49.536 46.873 49.56 ;
     RECT  46.397 2.208 47.333 7.704 ;
     RECT  46.649 89.328 47.365 92.52 ;
     RECT  47.357 49.584 47.441 49.608 ;
     RECT  47.437 60.432 47.521 60.456 ;
     RECT  47.333 2.88 47.585 7.704 ;
     RECT  45.904 35.856 47.603 35.88 ;
     RECT  47.365 89.328 47.797 92.568 ;
     RECT  47.797 88.944 47.977 92.568 ;
     RECT  47.977 88.944 48.061 92.904 ;
     RECT  48.061 88.944 48.149 92.568 ;
     RECT  48.121 35.328 48.205 35.352 ;
     RECT  48.149 88.896 48.227 92.568 ;
     RECT  46.585 47.664 48.332 47.88 ;
     RECT  47.537 1.728 48.373 1.752 ;
     RECT  47.585 2.88 48.373 6.696 ;
     RECT  48.332 47.664 48.409 48.456 ;
     RECT  48.409 47.28 48.419 48.456 ;
     RECT  46.019 27.312 48.421 27.336 ;
     RECT  48.421 27.168 48.467 27.336 ;
     RECT  48.373 1.728 48.565 6.696 ;
     RECT  47.585 7.68 48.565 7.704 ;
     RECT  48.227 88.896 48.593 90.648 ;
     RECT  48.227 91.776 48.593 92.568 ;
     RECT  48.469 22.8 48.611 22.824 ;
     RECT  48.469 30.72 48.611 30.744 ;
     RECT  48.593 90.48 48.629 90.648 ;
     RECT  48.419 47.28 48.757 47.976 ;
     RECT  48.593 88.896 48.757 89.448 ;
     RECT  48.757 46.944 48.844 47.976 ;
     RECT  48.844 47.856 48.917 47.976 ;
     RECT  48.565 1.728 49.025 7.704 ;
     RECT  48.941 49.584 49.025 49.608 ;
     RECT  48.941 60.96 49.025 60.984 ;
     RECT  48.757 88.368 49.025 89.448 ;
     RECT  48.593 92.352 49.273 92.568 ;
     RECT  48.917 47.856 49.349 47.88 ;
     RECT  49.273 92.352 49.381 92.904 ;
     RECT  49.025 88.944 49.628 89.448 ;
     RECT  48.629 90.48 49.628 90.6 ;
     RECT  49.381 92.352 49.669 93.528 ;
     RECT  49.669 91.776 49.811 93.528 ;
     RECT  49.628 88.944 49.849 90.6 ;
     RECT  49.811 91.776 49.849 92.904 ;
     RECT  49.717 0.288 50.533 0.312 ;
     RECT  50.533 0.288 50.675 0.552 ;
     RECT  49.849 88.944 50.821 92.904 ;
     RECT  49.025 2.16 50.917 7.704 ;
     RECT  50.821 88.944 50.962 93 ;
     RECT  50.917 1.728 51.008 7.704 ;
     RECT  48.467 27.168 51.008 27.192 ;
     RECT  45.904 68.736 51.008 68.76 ;
     RECT  50.962 88.944 51.008 93.048 ;
     RECT  51.008 1.728 51.107 93.048 ;
     RECT  50.675 0.288 51.251 0.36 ;
     RECT  51.107 1.728 51.251 93 ;
     RECT  51.251 1.728 51.304 92.904 ;
     RECT  51.308 94.08 51.395 94.104 ;
     RECT  51.349 0.192 51.545 0.216 ;
     RECT  51.304 47.904 51.589 47.928 ;
     RECT  51.304 1.728 51.689 7.704 ;
     RECT  51.304 88.8 52.121 92.904 ;
     RECT  52.121 88.8 52.157 92.568 ;
     RECT  51.689 2.256 52.403 7.704 ;
     RECT  52.403 2.88 52.481 7.704 ;
     RECT  52.157 91.2 52.589 92.568 ;
     RECT  52.549 47.76 52.597 47.784 ;
     RECT  52.597 47.328 52.657 47.784 ;
     RECT  52.657 47.328 52.697 48.504 ;
     RECT  52.157 88.8 52.741 90.072 ;
     RECT  52.645 0.288 52.787 0.312 ;
     RECT  52.697 47.76 52.787 48.504 ;
     RECT  52.901 0.192 52.985 0.216 ;
     RECT  52.741 88.368 53.129 90.072 ;
     RECT  53.129 88.848 53.341 90.072 ;
     RECT  52.589 91.2 53.341 92.52 ;
     RECT  52.787 47.904 53.372 48.504 ;
     RECT  53.341 88.848 53.533 92.52 ;
     RECT  52.481 4.176 53.557 7.704 ;
     RECT  53.533 88.848 53.597 92.424 ;
     RECT  52.481 2.88 53.797 2.904 ;
     RECT  53.797 2.88 53.917 2.952 ;
     RECT  53.597 88.848 53.957 92.376 ;
     RECT  53.221 1.728 54.065 1.752 ;
     RECT  53.372 47.904 54.133 48.84 ;
     RECT  53.917 2.832 54.236 2.952 ;
     RECT  53.557 3.936 54.236 7.704 ;
     RECT  54.133 47.856 54.277 48.84 ;
     RECT  53.957 88.848 54.373 90.792 ;
     RECT  54.277 47.856 54.476 49.032 ;
     RECT  54.476 46.944 54.533 49.032 ;
     RECT  54.533 46.944 54.563 48.504 ;
     RECT  54.373 88.368 54.641 90.792 ;
     RECT  51.304 27.168 54.713 27.192 ;
     RECT  54.673 93.504 54.803 93.528 ;
     RECT  54.737 0.192 54.821 0.216 ;
     RECT  54.641 88.368 54.857 88.392 ;
     RECT  54.236 2.832 54.901 7.704 ;
     RECT  54.563 47.328 54.901 48.504 ;
     RECT  54.641 89.424 54.929 90.792 ;
     RECT  53.957 91.776 54.961 92.376 ;
     RECT  54.901 47.328 55.117 47.352 ;
     RECT  55.045 0.288 55.148 0.312 ;
     RECT  55.148 0.288 55.187 1.128 ;
     RECT  55.187 1.104 55.235 1.128 ;
     RECT  54.929 89.472 55.237 90.792 ;
     RECT  54.961 91.776 55.237 92.472 ;
     RECT  55.237 89.472 55.289 92.472 ;
     RECT  55.289 92.352 55.292 92.472 ;
     RECT  55.292 92.352 55.379 92.568 ;
     RECT  54.901 48.48 55.441 48.504 ;
     RECT  54.901 2.16 55.621 7.704 ;
     RECT  55.289 89.472 56.293 91.224 ;
     RECT  55.379 92.352 56.293 92.52 ;
     RECT  56.293 89.472 56.341 92.52 ;
     RECT  56.245 0.288 56.387 0.312 ;
     RECT  55.621 1.728 56.408 7.704 ;
     RECT  56.293 49.584 56.408 49.608 ;
     RECT  51.304 68.736 56.408 68.76 ;
     RECT  56.341 89.472 56.408 93.048 ;
     RECT  56.408 1.728 56.704 93.048 ;
     RECT  56.704 91.2 56.773 93.048 ;
     RECT  56.773 91.2 56.86 93.096 ;
     RECT  56.861 94.896 56.876 94.92 ;
     RECT  56.876 94.8 56.945 94.92 ;
     RECT  56.945 94.8 56.963 94.824 ;
     RECT  56.773 0.576 57.061 0.6 ;
     RECT  56.704 1.728 57.061 7.704 ;
     RECT  56.704 79.44 57.155 80.712 ;
     RECT  56.704 68.928 57.169 68.952 ;
     RECT  57.061 0.576 57.197 7.704 ;
     RECT  56.704 48.432 57.565 49.032 ;
     RECT  57.155 80.688 57.635 80.712 ;
     RECT  57.197 0.576 57.665 6.504 ;
     RECT  56.704 88.944 57.665 90.072 ;
     RECT  57.565 49.008 57.697 49.032 ;
     RECT  57.697 49.008 57.853 49.56 ;
     RECT  57.665 88.992 57.913 90.072 ;
     RECT  56.86 91.2 57.913 92.472 ;
     RECT  57.853 49.536 57.923 49.56 ;
     RECT  57.913 88.992 57.953 92.472 ;
     RECT  57.953 91.776 58.321 92.472 ;
     RECT  58.321 92.352 58.453 92.472 ;
     RECT  57.665 1.152 58.489 6.504 ;
     RECT  57.197 7.68 58.489 7.704 ;
     RECT  58.489 1.152 58.595 7.704 ;
     RECT  58.453 92.352 58.691 92.904 ;
     RECT  57.953 88.992 59.221 90.6 ;
     RECT  58.595 1.152 59.321 6.696 ;
     RECT  59.321 2.208 59.557 6.696 ;
     RECT  58.595 7.68 59.557 7.704 ;
     RECT  59.557 2.208 59.645 7.704 ;
     RECT  59.321 1.152 59.681 1.176 ;
     RECT  59.221 88.944 59.713 90.6 ;
     RECT  58.691 92.352 59.713 92.856 ;
     RECT  59.713 88.944 60.073 92.856 ;
     RECT  60.001 49.584 60.085 49.608 ;
     RECT  56.704 27.312 60.131 27.336 ;
     RECT  59.209 48.432 60.179 48.456 ;
     RECT  59.645 2.256 60.277 7.704 ;
     RECT  60.277 2.256 60.325 7.992 ;
     RECT  60.085 16.992 60.437 17.64 ;
     RECT  60.073 88.944 60.437 92.904 ;
     RECT  60.373 47.28 60.46 47.304 ;
     RECT  60.325 2.256 60.565 8.04 ;
     RECT  60.565 2.256 60.649 8.568 ;
     RECT  60.649 2.256 60.689 8.616 ;
     RECT  60.689 2.304 60.833 8.616 ;
     RECT  60.437 17.616 61.484 17.64 ;
     RECT  57.155 79.44 61.513 79.464 ;
     RECT  60.437 88.944 61.621 89.976 ;
     RECT  61.285 1.152 61.657 1.176 ;
     RECT  60.833 2.304 61.657 7.704 ;
     RECT  61.621 88.944 61.669 90.024 ;
     RECT  60.437 91.056 61.669 92.904 ;
     RECT  61.669 88.944 61.729 92.904 ;
     RECT  61.513 94.08 61.763 94.104 ;
     RECT  61.657 1.152 61.808 7.704 ;
     RECT  61.429 9.072 61.808 9.096 ;
     RECT  61.657 16.56 61.808 16.584 ;
     RECT  61.484 17.568 61.808 17.64 ;
     RECT  61.669 47.856 61.808 47.88 ;
     RECT  61.513 79.44 61.808 79.8 ;
     RECT  61.729 88.944 61.808 93 ;
     RECT  61.808 1.152 61.861 93 ;
     RECT  61.861 0.192 61.985 93.048 ;
     RECT  61.985 1.152 62.104 93 ;
     RECT  62.104 88.944 62.236 93 ;
     RECT  62.104 1.152 62.339 7.704 ;
     RECT  62.339 1.152 62.435 1.176 ;
     RECT  62.104 47.28 62.62 47.304 ;
     RECT  62.104 48.432 62.641 48.84 ;
     RECT  62.236 88.944 62.849 92.52 ;
     RECT  62.641 48.48 63.097 48.84 ;
     RECT  63.097 48.48 63.209 49.032 ;
     RECT  62.849 88.944 63.292 89.976 ;
     RECT  62.339 2.208 63.317 7.704 ;
     RECT  62.849 91.2 63.421 92.52 ;
     RECT  63.317 2.208 63.445 6.408 ;
     RECT  63.445 1.728 63.461 6.408 ;
     RECT  63.421 91.2 63.505 92.904 ;
     RECT  63.461 1.728 63.821 1.8 ;
     RECT  63.821 1.728 63.877 1.752 ;
     RECT  63.829 47.856 63.916 47.88 ;
     RECT  63.829 46.752 63.925 46.776 ;
     RECT  63.925 46.752 64.009 47.352 ;
     RECT  63.877 1.152 64.021 1.752 ;
     RECT  63.505 91.2 64.021 92.856 ;
     RECT  64.021 90.912 64.037 92.856 ;
     RECT  64.021 0.288 64.067 1.752 ;
     RECT  64.067 0.288 64.133 0.552 ;
     RECT  64.133 0.192 64.217 0.552 ;
     RECT  64.217 0.336 64.307 0.552 ;
     RECT  63.292 88.944 64.316 89.736 ;
     RECT  64.037 90.912 64.316 92.568 ;
     RECT  63.461 2.832 64.357 6.408 ;
     RECT  64.009 46.752 64.369 47.304 ;
     RECT  64.369 46.752 64.397 46.776 ;
     RECT  63.209 49.008 64.537 49.032 ;
     RECT  64.537 49.008 64.547 49.416 ;
     RECT  64.357 2.832 64.565 6.456 ;
     RECT  63.317 7.68 64.565 7.704 ;
     RECT  64.547 49.392 64.643 49.416 ;
     RECT  64.316 88.944 64.685 92.568 ;
     RECT  64.307 0.528 64.787 0.552 ;
     RECT  64.067 1.728 64.933 1.752 ;
     RECT  64.565 2.832 64.933 7.704 ;
     RECT  64.685 88.992 64.973 92.568 ;
     RECT  65.372 47.232 65.459 47.256 ;
     RECT  65.509 48.432 65.804 48.456 ;
     RECT  64.973 88.992 65.845 92.376 ;
     RECT  65.804 48.432 65.891 49.416 ;
     RECT  65.845 88.944 66.085 92.376 ;
     RECT  66.013 93.504 66.179 93.528 ;
     RECT  65.891 48.432 66.205 48.456 ;
     RECT  64.933 1.728 66.665 7.704 ;
     RECT  66.085 88.944 66.805 92.424 ;
     RECT  66.805 88.944 67.141 92.856 ;
     RECT  66.665 2.016 67.208 7.704 ;
     RECT  65.725 10.8 67.208 10.824 ;
     RECT  67.141 88.944 67.208 93.048 ;
     RECT  66.977 0.192 67.285 0.216 ;
     RECT  67.208 2.016 67.285 93.048 ;
     RECT  67.285 0.192 67.429 0.312 ;
     RECT  67.285 2.016 67.504 93.096 ;
     RECT  67.504 88.992 67.564 93.096 ;
     RECT  67.564 88.992 67.66 93.144 ;
     RECT  67.429 0.192 67.667 0.408 ;
     RECT  67.667 0.192 67.709 0.312 ;
     RECT  67.709 0.288 67.753 0.312 ;
     RECT  67.66 88.992 67.817 92.472 ;
     RECT  67.817 88.992 67.925 90.792 ;
     RECT  67.504 10.752 68.105 10.776 ;
     RECT  67.504 2.736 68.332 7.704 ;
     RECT  67.925 89.232 68.357 90.792 ;
     RECT  68.332 2.88 68.429 7.704 ;
     RECT  67.817 92.352 68.713 92.472 ;
     RECT  68.713 92.352 68.857 92.904 ;
     RECT  68.357 89.232 68.893 90.216 ;
     RECT  68.857 92.352 69.059 93.528 ;
     RECT  68.005 1.728 69.445 1.752 ;
     RECT  68.429 2.88 69.445 6.408 ;
     RECT  69.253 0.288 69.491 0.312 ;
     RECT  69.445 1.728 69.493 6.408 ;
     RECT  68.429 7.68 69.493 7.704 ;
     RECT  69.433 91.2 69.517 91.224 ;
     RECT  68.893 89.136 69.541 90.216 ;
     RECT  69.493 1.728 69.545 7.704 ;
     RECT  69.541 88.944 69.581 90.6 ;
     RECT  69.545 2.256 69.587 7.704 ;
     RECT  69.581 90.192 69.725 90.6 ;
     RECT  69.059 92.352 69.923 92.952 ;
     RECT  69.923 92.352 69.977 92.616 ;
     RECT  69.977 92.352 70.121 92.568 ;
     RECT  70.297 47.328 70.38 47.352 ;
     RECT  70.38 47.328 70.381 47.4 ;
     RECT  70.165 1.152 70.409 1.176 ;
     RECT  69.581 88.944 70.409 89.16 ;
     RECT  70.381 47.376 70.489 47.4 ;
     RECT  69.725 90.576 70.513 90.6 ;
     RECT  69.587 2.256 70.549 7.176 ;
     RECT  70.409 89.136 70.765 89.16 ;
     RECT  70.604 48.48 70.985 48.504 ;
     RECT  70.549 2.208 71.077 7.176 ;
     RECT  70.765 89.136 71.125 89.208 ;
     RECT  71.125 89.136 71.171 89.256 ;
     RECT  70.121 92.352 71.233 92.376 ;
     RECT  71.077 1.728 71.237 7.176 ;
     RECT  71.017 49.008 71.341 49.032 ;
     RECT  70.513 90.576 71.417 91.032 ;
     RECT  71.341 49.008 71.425 49.608 ;
     RECT  71.233 92.208 71.521 92.376 ;
     RECT  71.425 49.008 71.569 49.032 ;
     RECT  71.365 0.288 71.653 0.312 ;
     RECT  71.171 89.184 71.701 89.256 ;
     RECT  71.237 2.592 72.085 7.176 ;
     RECT  71.521 92.208 72.133 92.424 ;
     RECT  72.133 91.824 72.229 92.424 ;
     RECT  71.737 93.504 72.277 93.528 ;
     RECT  71.653 0.288 72.373 1.176 ;
     RECT  72.277 93.504 72.419 94.104 ;
     RECT  72.373 0.288 72.493 1.272 ;
     RECT  72.229 91.824 72.517 92.472 ;
     RECT  72.419 93.504 72.517 93.528 ;
     RECT  72.493 0.24 72.608 1.272 ;
     RECT  72.085 2.592 72.608 7.992 ;
     RECT  71.701 89.184 72.608 89.496 ;
     RECT  71.417 90.576 72.608 90.6 ;
     RECT  72.517 91.824 72.608 93.528 ;
     RECT  72.608 0.24 72.707 93.528 ;
     RECT  72.707 2.148 72.712 93.528 ;
     RECT  72.707 0.24 72.851 0.312 ;
     RECT  72.712 2.208 72.904 93.528 ;
     RECT  72.904 92.352 73.037 93.528 ;
     RECT  73.037 93.504 73.139 93.528 ;
     RECT  72.904 89.232 73.613 89.496 ;
     RECT  73.525 0.192 73.813 0.216 ;
     RECT  73.813 0.192 73.901 0.312 ;
     RECT  73.901 0.192 73.937 0.216 ;
     RECT  72.904 2.208 73.957 7.224 ;
     RECT  73.613 89.232 74.617 89.304 ;
     RECT  74.653 90.624 74.765 90.648 ;
     RECT  73.957 1.728 74.801 7.224 ;
     RECT  74.801 2.208 74.909 7.224 ;
     RECT  73.037 92.352 75.109 92.472 ;
     RECT  75.013 93.504 75.109 93.528 ;
     RECT  75.109 92.352 75.193 93.528 ;
     RECT  75.193 92.352 75.233 94.104 ;
     RECT  75.233 93.504 75.299 94.104 ;
     RECT  74.909 2.208 75.449 7.176 ;
     RECT  75.449 2.208 75.557 6.84 ;
     RECT  75.013 91.152 75.917 91.176 ;
     RECT  74.617 89.136 75.985 89.304 ;
     RECT  74.437 47.328 76.117 47.352 ;
     RECT  76.117 47.328 76.165 47.4 ;
     RECT  76.165 46.752 76.349 47.4 ;
     RECT  75.299 94.08 76.403 94.104 ;
     RECT  75.557 2.208 76.499 6.408 ;
     RECT  76.453 49.584 76.565 49.608 ;
     RECT  75.253 1.152 76.601 1.176 ;
     RECT  75.985 89.136 76.673 89.592 ;
     RECT  75.233 92.352 76.705 92.376 ;
     RECT  76.499 2.208 76.913 2.904 ;
     RECT  76.705 92.352 76.933 92.424 ;
     RECT  76.499 3.888 76.957 6.408 ;
     RECT  76.933 92.352 76.957 92.856 ;
     RECT  76.957 3.888 77.221 6.888 ;
     RECT  76.349 47.376 77.425 47.4 ;
     RECT  76.957 92.016 77.677 92.856 ;
     RECT  76.913 1.728 77.797 2.904 ;
     RECT  77.221 3.888 77.797 7.08 ;
     RECT  76.673 89.376 77.893 89.592 ;
     RECT  77.101 90.816 77.893 90.84 ;
     RECT  77.677 92.016 77.9 92.904 ;
     RECT  77.797 1.728 78.008 7.08 ;
     RECT  77.425 47.328 78.008 47.4 ;
     RECT  77.365 49.008 78.008 49.032 ;
     RECT  77.893 89.376 78.008 90.84 ;
     RECT  77.9 92.016 78.008 93.048 ;
     RECT  78.008 1.728 78.185 93.048 ;
     RECT  78.185 1.728 78.304 93 ;
     RECT  78.229 0.288 78.373 0.312 ;
     RECT  78.304 91.728 78.467 93 ;
     RECT  78.373 0.192 78.553 0.312 ;
     RECT  78.304 89.424 78.611 90.072 ;
     RECT  78.304 47.376 78.617 47.4 ;
     RECT  78.304 1.728 78.649 6.984 ;
     RECT  78.649 1.68 78.733 6.984 ;
     RECT  78.733 1.776 78.761 6.984 ;
     RECT  78.467 91.728 78.851 92.904 ;
     RECT  78.553 0.192 79.013 0.216 ;
     RECT  78.761 1.776 79.337 6.936 ;
     RECT  78.611 89.808 79.369 90.072 ;
     RECT  78.851 91.728 79.369 92.52 ;
     RECT  79.669 7.968 79.837 7.992 ;
     RECT  79.369 89.808 79.837 90.264 ;
     RECT  79.369 91.344 79.837 92.52 ;
     RECT  79.861 47.328 79.873 47.352 ;
     RECT  79.873 47.328 79.949 47.928 ;
     RECT  79.949 47.904 79.957 47.928 ;
     RECT  79.837 7.968 79.985 8.04 ;
     RECT  79.837 89.808 80.003 92.52 ;
     RECT  79.985 8.016 80.051 8.04 ;
     RECT  80.003 92.352 80.101 92.52 ;
     RECT  80.101 92.352 80.341 92.568 ;
     RECT  80.389 0.576 80.533 0.6 ;
     RECT  80.533 0.576 80.561 1.176 ;
     RECT  79.337 2.208 80.561 6.936 ;
     RECT  80.341 92.352 80.677 92.664 ;
     RECT  80.003 89.808 80.701 91.368 ;
     RECT  80.701 88.896 80.821 91.368 ;
     RECT  80.809 49.536 80.837 49.56 ;
     RECT  80.561 1.104 80.867 1.176 ;
     RECT  80.677 92.352 80.885 92.856 ;
     RECT  80.837 49.008 80.893 49.56 ;
     RECT  80.885 92.352 80.893 92.76 ;
     RECT  80.893 49.008 80.921 49.032 ;
     RECT  80.821 88.368 80.965 91.368 ;
     RECT  80.893 92.352 80.965 92.664 ;
     RECT  80.561 2.208 81.089 6.888 ;
     RECT  80.965 88.368 81.101 92.664 ;
     RECT  80.965 9.072 81.107 9.096 ;
     RECT  81.089 1.728 81.137 6.888 ;
     RECT  81.137 1.728 81.173 1.752 ;
     RECT  80.953 48.48 81.241 48.552 ;
     RECT  81.241 47.856 81.325 48.552 ;
     RECT  81.601 47.328 81.685 47.352 ;
     RECT  81.325 48.528 81.965 48.552 ;
     RECT  81.137 2.784 82.105 6.888 ;
     RECT  82.105 2.784 82.189 6.936 ;
     RECT  82.189 2.784 82.253 6.888 ;
     RECT  82.565 1.728 82.597 1.752 ;
     RECT  82.253 2.784 82.597 6.456 ;
     RECT  82.453 8.544 82.645 8.568 ;
     RECT  81.101 88.368 83.173 92.568 ;
     RECT  83.173 88.32 83.221 92.568 ;
     RECT  83.221 0.192 83.363 0.216 ;
     RECT  82.597 1.728 83.408 6.456 ;
     RECT  82.645 8.544 83.408 8.616 ;
     RECT  82.021 49.008 83.408 49.032 ;
     RECT  83.221 88.176 83.408 93.096 ;
     RECT  83.365 0.528 83.651 0.552 ;
     RECT  83.408 1.728 83.704 93.096 ;
     RECT  83.704 87.792 83.795 93.096 ;
     RECT  83.704 1.728 84.125 6.984 ;
     RECT  84.113 94.896 84.14 94.92 ;
     RECT  84.14 94.8 84.193 94.92 ;
     RECT  84.193 94.08 84.197 94.92 ;
     RECT  84.197 94.08 84.227 94.824 ;
     RECT  83.704 46.944 84.323 49.08 ;
     RECT  84.323 49.008 84.341 49.08 ;
     RECT  84.125 2.736 84.349 6.984 ;
     RECT  84.341 49.008 84.371 49.032 ;
     RECT  84.349 2.736 84.413 6.888 ;
     RECT  83.893 0.576 84.553 0.6 ;
     RECT  84.125 1.728 84.553 1.752 ;
     RECT  83.795 87.792 84.557 92.568 ;
     RECT  84.553 0.576 84.661 1.752 ;
     RECT  84.661 0.288 84.851 1.752 ;
     RECT  84.557 88.368 84.881 92.568 ;
     RECT  84.851 0.288 84.947 0.312 ;
     RECT  84.757 9.072 84.947 9.096 ;
     RECT  84.323 46.944 84.961 47.928 ;
     RECT  84.881 88.368 85.025 92.472 ;
     RECT  84.851 1.728 85.141 1.752 ;
     RECT  84.413 2.736 85.141 6.504 ;
     RECT  84.961 46.944 85.277 46.968 ;
     RECT  85.025 88.896 85.427 92.472 ;
     RECT  84.227 94.08 85.523 94.104 ;
     RECT  85.141 1.728 85.561 6.504 ;
     RECT  85.561 1.728 85.763 6.936 ;
     RECT  85.909 94.8 85.957 94.824 ;
     RECT  85.763 1.728 85.961 6.792 ;
     RECT  85.957 94.8 85.997 94.92 ;
     RECT  85.997 94.896 86.041 94.92 ;
     RECT  85.427 88.944 86.197 92.472 ;
     RECT  86.137 46.752 86.221 46.776 ;
     RECT  85.961 1.728 86.573 6.504 ;
     RECT  86.573 2.16 87.001 6.504 ;
     RECT  87.212 48.816 87.299 48.84 ;
     RECT  87.001 2.16 87.325 6.6 ;
     RECT  86.197 88.944 87.329 92.856 ;
     RECT  87.329 91.776 87.388 92.856 ;
     RECT  87.325 2.16 87.589 6.936 ;
     RECT  87.577 48.48 87.661 48.504 ;
     RECT  87.388 91.776 87.683 92.616 ;
     RECT  87.589 1.728 87.689 6.936 ;
     RECT  87.329 88.944 87.797 90.744 ;
     RECT  87.689 1.776 88.405 6.936 ;
     RECT  88.357 0.192 88.499 0.216 ;
     RECT  88.541 94.896 88.556 94.92 ;
     RECT  88.556 94.8 88.625 94.92 ;
     RECT  88.625 94.8 88.643 94.824 ;
     RECT  87.683 91.824 88.657 92.616 ;
     RECT  87.797 89.424 88.693 90.744 ;
     RECT  88.657 91.776 88.693 92.616 ;
     RECT  88.693 89.424 88.7 92.616 ;
     RECT  88.405 1.776 88.741 7.128 ;
     RECT  88.7 89.424 88.765 93.048 ;
     RECT  88.741 1.728 88.808 7.128 ;
     RECT  88.621 47.904 88.808 47.928 ;
     RECT  88.765 89.424 88.808 93.144 ;
     RECT  88.808 1.728 88.931 93.144 ;
     RECT  88.931 1.728 89.104 93 ;
     RECT  89.104 92.352 89.165 93 ;
     RECT  89.104 1.728 89.219 7.8 ;
     RECT  89.104 48.432 89.315 48.456 ;
     RECT  88.693 0.288 89.411 0.312 ;
     RECT  89.104 89.472 89.705 91.224 ;
     RECT  89.705 89.52 89.921 91.224 ;
     RECT  89.219 1.728 89.939 6.456 ;
     RECT  89.219 7.44 89.939 7.8 ;
     RECT  89.921 89.52 90.101 90.696 ;
     RECT  89.165 92.352 90.181 92.568 ;
     RECT  90.181 92.352 90.268 92.856 ;
     RECT  90.268 92.352 90.325 92.376 ;
     RECT  89.939 1.728 90.353 6.024 ;
     RECT  90.325 92.016 90.353 92.376 ;
     RECT  90.353 5.088 90.497 6.024 ;
     RECT  90.353 1.728 90.533 4.056 ;
     RECT  90.497 5.088 90.605 5.544 ;
     RECT  89.104 18.24 90.605 18.264 ;
     RECT  90.529 94.08 90.659 94.104 ;
     RECT  90.353 92.016 90.677 92.28 ;
     RECT  90.637 47.856 90.721 47.88 ;
     RECT  90.533 1.776 90.749 4.056 ;
     RECT  90.605 5.088 90.749 5.16 ;
     RECT  90.565 83.664 90.821 83.688 ;
     RECT  90.749 1.776 90.857 3.912 ;
     RECT  89.939 7.44 90.857 7.464 ;
     RECT  89.104 76.368 91.187 76.392 ;
     RECT  91.1 83.76 91.187 83.784 ;
     RECT  91.105 91.776 91.189 91.8 ;
     RECT  90.101 89.52 91.253 90.648 ;
     RECT  90.857 1.776 91.325 3.432 ;
     RECT  91.253 89.52 91.325 90.6 ;
     RECT  91.325 89.52 91.397 89.544 ;
     RECT  90.749 5.088 91.469 5.112 ;
     RECT  91.325 2.208 91.937 3.432 ;
     RECT  91.937 2.544 92.153 3.432 ;
     RECT  92.153 2.544 92.297 2.568 ;
    LAYER M5 ;
     RECT  4.32 0.144 90.648 0.227 ;
     RECT  4.464 0.227 90.648 1.235 ;
     RECT  4.464 1.235 5.352 1.667 ;
     RECT  4.464 1.667 5.208 1.715 ;
     RECT  6.576 1.235 90.648 1.715 ;
     RECT  4.464 1.715 4.488 1.763 ;
     RECT  2.4 2.137 2.52 2.151 ;
     RECT  7.152 1.715 90.648 2.195 ;
     RECT  55.152 2.195 90.648 3.443 ;
     RECT  7.152 2.195 54.12 3.877 ;
     RECT  55.152 3.443 90.072 3.877 ;
     RECT  4.752 4.309 4.776 4.883 ;
     RECT  6.912 3.877 90.072 5.171 ;
     RECT  6.912 5.171 89.592 6.323 ;
     RECT  10.848 6.323 13.752 6.371 ;
     RECT  14.736 6.323 47.4 6.371 ;
     RECT  6.912 6.323 9.768 6.419 ;
     RECT  15.024 6.371 47.4 6.419 ;
     RECT  48.48 6.323 89.592 6.419 ;
     RECT  76.128 6.419 89.592 6.421 ;
     RECT  20.544 6.419 47.4 6.467 ;
     RECT  76.128 6.421 89.928 6.467 ;
     RECT  9.36 6.419 9.768 6.515 ;
     RECT  20.592 6.467 31.752 6.563 ;
     RECT  74.112 6.419 75.096 6.563 ;
     RECT  15.024 6.419 19.56 6.611 ;
     RECT  48.48 6.419 67.944 6.707 ;
     RECT  9.36 6.515 9.528 6.851 ;
     RECT  32.736 6.467 47.4 6.851 ;
     RECT  48.48 6.707 58.584 6.851 ;
     RECT  11.424 6.371 13.752 6.899 ;
     RECT  15.792 6.611 19.56 6.899 ;
     RECT  20.592 6.563 27.528 6.899 ;
     RECT  28.56 6.563 31.752 6.899 ;
     RECT  59.568 6.707 67.944 6.899 ;
     RECT  74.112 6.563 74.472 6.899 ;
     RECT  15.792 6.899 19.464 6.947 ;
     RECT  25.44 6.899 27.528 6.947 ;
     RECT  28.56 6.899 30.6 6.947 ;
     RECT  32.736 6.851 36.072 6.947 ;
     RECT  37.2 6.851 47.4 6.947 ;
     RECT  48.48 6.851 57.816 6.947 ;
     RECT  76.128 6.467 86.184 6.947 ;
     RECT  87.36 6.467 89.928 6.947 ;
     RECT  41.712 6.947 42.072 6.995 ;
     RECT  48.48 6.947 51.576 6.995 ;
     RECT  66.96 6.899 67.944 6.995 ;
     RECT  76.128 6.947 84.792 6.995 ;
     RECT  32.736 6.947 32.904 7.043 ;
     RECT  34.368 6.947 36.072 7.043 ;
     RECT  48.48 6.995 49.992 7.043 ;
     RECT  66.96 6.995 67.512 7.139 ;
     RECT  87.6 6.947 89.928 7.139 ;
     RECT  43.2 6.947 47.4 7.187 ;
     RECT  49.968 7.043 49.992 7.187 ;
     RECT  69.504 6.419 72.912 7.187 ;
     RECT  25.44 6.947 27.144 7.475 ;
     RECT  60.048 6.899 65.064 7.475 ;
     RECT  34.56 7.043 36.072 7.523 ;
     RECT  60.048 7.475 64.776 7.523 ;
     RECT  69.552 7.187 72.912 7.715 ;
     RECT  37.2 6.947 40.632 7.763 ;
     RECT  31.632 6.899 31.752 8.003 ;
     RECT  37.2 7.763 40.512 8.003 ;
     RECT  70.32 7.715 72.912 8.003 ;
     RECT  79.68 6.995 84.792 8.003 ;
     RECT  31.728 8.003 31.752 8.051 ;
     RECT  42.048 6.995 42.072 8.579 ;
     RECT  79.872 8.003 84.792 8.579 ;
     RECT  60.048 7.523 64.248 8.627 ;
     RECT  82.656 8.579 84.792 8.627 ;
     RECT  83.4 8.627 84.792 9.061 ;
     RECT  61.44 8.627 64.248 9.107 ;
     RECT  6.912 6.419 8.112 10.837 ;
     RECT  4.224 5.845 4.248 10.883 ;
     RECT  20.592 6.899 24.312 11.411 ;
     RECT  6.816 10.837 8.112 13.813 ;
     RECT  11.424 6.899 13.512 14.773 ;
     RECT  34.8 7.523 36.072 16.019 ;
     RECT  60.048 8.627 60.072 16.981 ;
     RECT  10.8 14.773 13.512 17.123 ;
     RECT  61.536 9.107 64.248 17.603 ;
     RECT  34.8 16.019 35.352 17.605 ;
     RECT  11.424 17.123 13.512 18.275 ;
     RECT  88.656 7.139 89.928 18.275 ;
     RECT  11.424 18.275 11.832 18.323 ;
     RECT  12.816 18.275 13.512 18.613 ;
     RECT  11.808 18.323 11.832 19.333 ;
     RECT  12.816 18.613 13.608 19.333 ;
     RECT  25.44 7.475 26.184 19.811 ;
     RECT  11.808 19.333 13.608 20.147 ;
     RECT  11.808 20.147 13.512 20.341 ;
     RECT  11.376 20.341 13.512 20.387 ;
     RECT  15.792 6.947 17.304 21.107 ;
     RECT  11.376 20.387 11.832 21.155 ;
     RECT  6.624 13.813 8.112 21.683 ;
     RECT  48.48 7.043 48.984 22.835 ;
     RECT  40.2 8.003 40.512 27.157 ;
     RECT  48.576 22.835 48.984 27.157 ;
     RECT  34.8 17.605 35.592 27.251 ;
     RECT  44.592 7.187 47.4 27.301 ;
     RECT  48.432 27.157 48.984 27.301 ;
     RECT  40.2 27.157 40.632 27.347 ;
     RECT  60.048 16.981 60.12 27.347 ;
     RECT  5.184 25.861 5.208 35.939 ;
     RECT  4.8 36.421 4.824 41.317 ;
     RECT  4.176 41.317 4.824 41.363 ;
     RECT  4.176 41.363 4.2 45.059 ;
     RECT  6.912 21.683 8.112 46.117 ;
     RECT  11.808 21.155 11.832 46.645 ;
     RECT  10.896 46.645 11.832 46.693 ;
     RECT  12.816 20.387 13.512 46.693 ;
     RECT  20.592 11.411 22.92 46.787 ;
     RECT  86.16 6.947 86.184 46.787 ;
     RECT  83.4 9.061 84.936 46.933 ;
     RECT  9.408 6.851 9.528 47.269 ;
     RECT  60.048 27.347 60.072 47.269 ;
     RECT  61.8 17.603 64.248 47.269 ;
     RECT  10.896 46.693 13.512 47.363 ;
     RECT  25.44 19.811 25.752 47.363 ;
     RECT  52.608 6.947 57.816 47.363 ;
     RECT  70.32 8.003 71.544 47.363 ;
     RECT  74.448 6.899 74.472 47.363 ;
     RECT  79.872 8.579 81.672 47.363 ;
     RECT  70.416 47.363 71.544 47.411 ;
     RECT  76.128 6.995 78.312 47.411 ;
     RECT  0.24 6.181 0.264 47.699 ;
     RECT  32.736 7.043 32.76 47.845 ;
     RECT  34.8 27.251 35.112 47.845 ;
     RECT  61.8 47.269 64.344 47.845 ;
     RECT  6.912 46.117 8.376 47.939 ;
     RECT  9.36 47.269 9.528 47.939 ;
     RECT  15.792 21.107 16.152 47.939 ;
     RECT  17.232 21.107 17.304 47.939 ;
     RECT  25.728 47.363 25.752 47.939 ;
     RECT  28.56 6.947 29.712 47.939 ;
     RECT  37.2 8.003 39.096 47.939 ;
     RECT  51 6.995 51.576 47.939 ;
     RECT  79.92 47.363 81.288 47.939 ;
     RECT  88.656 18.275 89.112 47.939 ;
     RECT  7.488 47.939 8.376 48.277 ;
     RECT  9.36 47.939 9.432 48.277 ;
     RECT  34.176 47.845 35.592 48.277 ;
     RECT  18.336 6.947 19.464 48.421 ;
     RECT  20.592 46.787 22.392 48.421 ;
     RECT  60.048 47.269 60.408 48.421 ;
     RECT  65.424 47.221 65.448 48.421 ;
     RECT  88.8 47.939 89.112 48.421 ;
     RECT  16.128 47.939 16.152 48.515 ;
     RECT  18.336 48.421 22.392 48.515 ;
     RECT  38.304 47.939 39.096 48.515 ;
     RECT  43.2 7.187 43.416 48.515 ;
     RECT  44.592 27.301 48.984 48.515 ;
     RECT  52.704 47.363 57.816 48.515 ;
     RECT  70.656 47.411 71.544 48.515 ;
     RECT  87.6 7.139 87.624 48.515 ;
     RECT  21.792 48.515 22.392 48.563 ;
     RECT  32.064 47.845 32.76 48.997 ;
     RECT  34.176 48.277 36.216 48.997 ;
     RECT  37.2 47.939 37.224 48.997 ;
     RECT  61.68 47.845 64.344 48.997 ;
     RECT  65.424 48.421 66.168 48.997 ;
     RECT  80.88 47.939 81.288 48.997 ;
     RECT  83.4 46.933 85.224 48.997 ;
     RECT  17.28 47.939 17.304 49.043 ;
     RECT  18.6 48.515 20.712 49.043 ;
     RECT  21.792 48.563 21.816 49.043 ;
     RECT  43.2 48.515 43.224 49.043 ;
     RECT  71.04 48.515 71.544 49.043 ;
     RECT  76.464 47.411 78.312 49.043 ;
     RECT  34.176 48.997 37.224 49.091 ;
     RECT  56.304 48.515 57.816 49.525 ;
     RECT  80.88 48.997 82.056 49.525 ;
     RECT  7.488 48.277 9.432 49.619 ;
     RECT  45.6 48.515 48.984 49.619 ;
     RECT  56.304 49.525 57.912 49.619 ;
     RECT  71.376 49.043 71.4 49.619 ;
     RECT  76.464 49.043 76.488 49.619 ;
     RECT  31.392 48.997 32.76 50.771 ;
     RECT  7.8 49.619 9.432 51.923 ;
     RECT  5.856 49.381 5.88 53.221 ;
     RECT  5.856 53.221 6.072 53.267 ;
     RECT  6.048 53.267 6.072 57.059 ;
     RECT  45.6 49.619 48.792 60.467 ;
     RECT  47.808 60.467 48.792 60.949 ;
     RECT  4.176 57.541 4.2 61.237 ;
     RECT  4.08 61.237 4.2 61.333 ;
     RECT  4.08 61.333 4.248 61.379 ;
     RECT  4.224 61.379 4.248 65.027 ;
     RECT  47.808 60.949 48.984 68.771 ;
     RECT  31.392 50.771 32.376 68.917 ;
     RECT  5.664 57.205 5.688 69.301 ;
     RECT  5.376 69.301 5.688 72.613 ;
     RECT  90.672 47.845 90.696 76.357 ;
     RECT  5.136 72.613 5.688 77.267 ;
     RECT  34.176 49.091 37.128 78.037 ;
     RECT  31.392 68.917 32.568 78.083 ;
     RECT  24 11.411 24.312 78.613 ;
     RECT  61.68 48.997 66.168 79.765 ;
     RECT  90.672 76.357 91.176 83.653 ;
     RECT  5.568 77.267 5.688 84.419 ;
     RECT  38.304 48.515 38.328 88.403 ;
     RECT  47.808 68.771 48.792 88.403 ;
     RECT  29.4 47.939 29.712 88.741 ;
     RECT  31.392 78.083 32.376 88.741 ;
     RECT  7.8 51.923 9.384 88.789 ;
     RECT  51 47.939 51.312 88.789 ;
     RECT  80.832 49.525 82.056 88.789 ;
     RECT  83.088 48.997 85.224 88.789 ;
     RECT  7.8 88.789 9.528 88.885 ;
     RECT  10.896 47.363 11.88 88.885 ;
     RECT  13.2 47.363 13.512 88.885 ;
     RECT  18.6 49.043 19.752 88.885 ;
     RECT  34.128 78.037 37.128 88.885 ;
     RECT  80.832 88.789 85.224 88.885 ;
     RECT  29.4 88.741 32.376 88.979 ;
     RECT  34.128 88.885 37.464 88.979 ;
     RECT  59.232 48.421 60.408 88.979 ;
     RECT  29.4 88.979 32.088 89.027 ;
     RECT  80.736 88.885 85.416 89.125 ;
     RECT  7.68 88.885 11.88 89.317 ;
     RECT  18.192 88.885 19.752 89.317 ;
     RECT  45.6 60.467 46.824 89.317 ;
     RECT  47.808 88.403 48.456 89.317 ;
     RECT  51 88.789 51.72 89.317 ;
     RECT  56.4 49.619 57.912 89.317 ;
     RECT  61.536 79.765 66.168 89.317 ;
     RECT  67.2 7.139 67.512 89.317 ;
     RECT  50.064 89.317 51.72 89.365 ;
     RECT  7.488 89.317 11.88 89.413 ;
     RECT  36.432 88.979 37.464 89.413 ;
     RECT  59.904 88.979 60.408 89.413 ;
     RECT  78 49.043 78.312 89.413 ;
     RECT  87.264 48.805 87.288 89.413 ;
     RECT  88.8 48.421 89.304 89.413 ;
     RECT  7.488 89.413 11.976 89.461 ;
     RECT  18.192 89.317 19.848 89.461 ;
     RECT  21.072 89.365 21.096 89.461 ;
     RECT  34.128 88.979 35.448 89.461 ;
     RECT  87.168 89.413 89.304 89.461 ;
     RECT  13.2 88.885 14.424 89.507 ;
     RECT  7.392 89.461 11.976 89.555 ;
     RECT  18.192 89.461 19.896 89.699 ;
     RECT  41.712 89.317 41.736 89.747 ;
     RECT  78 89.413 78.6 89.797 ;
     RECT  24 78.613 25.272 89.843 ;
     RECT  33.84 89.461 35.448 89.845 ;
     RECT  49.92 89.365 51.72 89.845 ;
     RECT  52.752 48.515 54.552 89.845 ;
     RECT  78 89.797 78.648 89.845 ;
     RECT  77.904 89.845 78.648 89.893 ;
     RECT  5.664 84.419 5.688 89.939 ;
     RECT  90.576 83.653 91.176 89.939 ;
     RECT  33.792 89.845 35.448 89.941 ;
     RECT  36.432 89.413 38.088 89.941 ;
     RECT  40.2 27.347 40.512 89.989 ;
     RECT  56.4 89.317 58.68 89.989 ;
     RECT  7.392 89.555 10.248 90.037 ;
     RECT  29.4 89.027 31.848 90.037 ;
     RECT  33.792 89.941 38.088 90.037 ;
     RECT  49.92 89.845 55.272 90.037 ;
     RECT  56.4 89.989 58.776 90.037 ;
     RECT  80.736 89.125 85.896 90.037 ;
     RECT  11.952 89.555 11.976 90.083 ;
     RECT  29.4 90.037 38.088 90.083 ;
     RECT  18.48 89.699 19.896 90.373 ;
     RECT  21.072 89.461 21.192 90.373 ;
     RECT  22.944 90.373 22.968 90.421 ;
     RECT  80.16 90.037 85.896 90.469 ;
     RECT  86.976 89.461 89.448 90.469 ;
     RECT  49.68 90.037 58.776 90.517 ;
     RECT  59.904 89.413 60.504 90.517 ;
     RECT  29.4 90.083 38.04 90.565 ;
     RECT  45.6 89.317 48.456 90.565 ;
     RECT  49.68 90.517 60.504 90.565 ;
     RECT  80.16 90.469 89.448 90.565 ;
     RECT  4.176 88.789 4.2 90.659 ;
     RECT  71.136 89.125 71.16 90.659 ;
     RECT  17.328 90.565 17.352 90.661 ;
     RECT  17.232 90.661 17.352 90.901 ;
     RECT  44.016 90.565 44.04 90.901 ;
     RECT  45.6 90.565 60.504 90.901 ;
     RECT  24 89.843 24.312 90.949 ;
     RECT  44.016 90.901 60.504 91.093 ;
     RECT  61.536 89.317 67.512 91.093 ;
     RECT  69.456 90.181 69.48 91.235 ;
     RECT  44.016 91.093 67.512 91.331 ;
     RECT  22.56 90.421 22.968 91.669 ;
     RECT  24 90.949 24.408 91.669 ;
     RECT  7.296 90.037 10.248 91.717 ;
     RECT  65.472 91.331 67.512 91.717 ;
     RECT  80.16 90.565 89.496 91.717 ;
     RECT  28.896 90.565 38.04 91.765 ;
     RECT  39.84 89.989 40.512 91.765 ;
     RECT  91.152 89.939 91.176 91.811 ;
     RECT  77.904 89.893 78.696 92.005 ;
     RECT  79.968 91.717 89.496 92.005 ;
     RECT  77.376 92.005 78.696 92.245 ;
     RECT  79.968 92.005 90.504 92.245 ;
     RECT  7.296 91.717 10.776 92.341 ;
     RECT  13.2 89.507 13.512 92.341 ;
     RECT  17.232 90.901 17.448 92.341 ;
     RECT  18.48 90.373 21.192 92.341 ;
     RECT  22.56 91.669 24.408 92.341 ;
     RECT  28.464 91.765 38.04 92.341 ;
     RECT  39.552 91.765 40.512 92.341 ;
     RECT  44.016 91.331 64.392 92.341 ;
     RECT  65.472 91.717 67.608 92.341 ;
     RECT  71.376 92.197 71.4 92.341 ;
     RECT  72.6 8.003 72.912 92.341 ;
     RECT  77.376 92.245 90.504 92.341 ;
     RECT  4.608 92.341 5.064 92.389 ;
     RECT  6.288 92.341 16.056 92.389 ;
     RECT  4.608 92.389 5.208 92.485 ;
     RECT  6.288 92.389 16.2 92.485 ;
     RECT  17.232 92.341 43.032 92.533 ;
     RECT  44.016 92.341 64.488 92.533 ;
     RECT  65.472 92.341 90.504 92.533 ;
     RECT  4.608 92.485 16.2 92.821 ;
     RECT  4.32 92.821 16.2 92.869 ;
     RECT  17.232 92.533 90.504 92.869 ;
     RECT  2.4 2.151 2.712 92.889 ;
     RECT  2.4 92.889 2.52 92.903 ;
     RECT  4.32 92.869 90.504 94.069 ;
     RECT  4.32 94.069 90.648 94.864 ;
     RECT  36.24 94.864 36.264 94.931 ;
     RECT  56.88 94.864 56.904 94.931 ;
     RECT  84.144 94.864 84.168 94.931 ;
     RECT  85.968 94.864 85.992 94.931 ;
     RECT  88.56 94.864 88.584 94.931 ;
     RECT  5.352 1.235 6.576 1.667 ;
     RECT  5.208 1.667 6.576 1.715 ;
     RECT  54.12 2.195 55.152 3.877 ;
     RECT  89.592 5.171 89.928 6.421 ;
     RECT  2.712 5.845 4.224 10.883 ;
     RECT  9.768 6.323 10.848 6.371 ;
     RECT  13.752 6.323 14.736 6.371 ;
     RECT  47.4 6.323 48.48 22.835 ;
     RECT  13.752 6.371 15.024 6.611 ;
     RECT  8.112 6.419 9.36 6.851 ;
     RECT  19.56 6.419 20.544 6.467 ;
     RECT  72.912 6.419 74.112 6.899 ;
     RECT  75.096 6.419 76.128 6.563 ;
     RECT  19.56 6.467 20.592 6.899 ;
     RECT  31.752 6.467 32.736 8.051 ;
     RECT  86.184 6.467 87.36 6.947 ;
     RECT  27.528 6.563 28.56 6.947 ;
     RECT  58.584 6.707 59.568 6.851 ;
     RECT  8.112 6.851 9.408 46.117 ;
     RECT  36.072 6.851 37.2 16.019 ;
     RECT  19.464 6.899 20.592 48.421 ;
     RECT  24.312 6.899 25.44 47.363 ;
     RECT  30.6 6.899 31.632 6.947 ;
     RECT  17.304 6.947 18.336 48.515 ;
     RECT  27.144 6.947 28.56 7.475 ;
     RECT  32.904 6.947 34.368 7.043 ;
     RECT  40.632 6.947 41.712 6.995 ;
     RECT  42.072 6.947 43.2 8.579 ;
     RECT  51.576 6.947 52.608 47.363 ;
     RECT  84.792 6.947 86.16 9.061 ;
     RECT  86.184 6.947 87.6 46.787 ;
     RECT  40.632 6.995 42.048 7.763 ;
     RECT  49.992 6.995 51 7.187 ;
     RECT  78.312 6.995 79.68 8.003 ;
     RECT  48.984 7.043 49.968 7.187 ;
     RECT  87.624 7.139 88.656 47.939 ;
     RECT  43.416 7.187 44.592 48.515 ;
     RECT  39.096 8.003 40.2 48.515 ;
     RECT  71.544 8.003 72.6 49.043 ;
     RECT  81.672 8.579 82.656 8.627 ;
     RECT  60.072 8.627 61.44 9.107 ;
     RECT  84.936 9.061 86.16 46.787 ;
     RECT  60.072 9.107 61.536 16.981 ;
     RECT  22.92 11.411 24 46.787 ;
     RECT  9.528 14.773 10.8 17.123 ;
     RECT  60.12 16.981 61.536 17.603 ;
     RECT  11.832 18.275 12.816 19.333 ;
     RECT  11.832 20.387 12.816 46.693 ;
     RECT  16.152 21.107 17.232 47.939 ;
     RECT  47.4 22.835 48.576 27.157 ;
     RECT  47.4 27.157 48.432 27.301 ;
     RECT  2.712 41.317 4.176 45.059 ;
     RECT  8.376 46.117 9.408 47.269 ;
     RECT  9.528 46.645 10.896 47.939 ;
     RECT  84.936 46.787 85.224 46.933 ;
     RECT  64.248 47.221 65.424 47.269 ;
     RECT  8.376 47.269 9.36 48.277 ;
     RECT  60.408 47.269 61.8 47.845 ;
     RECT  64.344 47.269 65.424 48.997 ;
     RECT  11.88 47.363 13.2 89.413 ;
     RECT  24.312 47.363 25.728 47.939 ;
     RECT  51.576 47.363 52.704 47.939 ;
     RECT  32.76 47.845 34.176 50.771 ;
     RECT  60.408 47.845 61.68 79.765 ;
     RECT  9.432 47.939 10.896 51.923 ;
     RECT  16.152 47.939 17.28 48.515 ;
     RECT  37.224 47.939 38.304 49.091 ;
     RECT  51.312 47.939 52.704 48.515 ;
     RECT  87.624 47.939 88.8 48.515 ;
     RECT  36.216 48.277 37.2 48.997 ;
     RECT  57.816 48.421 59.232 49.525 ;
     RECT  66.168 48.421 67.2 89.317 ;
     RECT  89.304 48.421 90.672 83.653 ;
     RECT  17.304 48.515 18.6 49.043 ;
     RECT  20.712 48.515 21.792 49.043 ;
     RECT  51.312 48.515 52.752 88.789 ;
     RECT  87.6 48.515 88.8 48.805 ;
     RECT  87.288 48.805 88.8 89.413 ;
     RECT  82.056 48.997 83.088 88.789 ;
     RECT  71.4 49.043 72.6 49.619 ;
     RECT  76.488 49.043 78 49.619 ;
     RECT  37.128 49.091 38.304 88.403 ;
     RECT  57.912 49.525 59.232 88.979 ;
     RECT  9.384 51.923 10.896 88.789 ;
     RECT  2.712 57.541 4.176 61.237 ;
     RECT  4.2 57.541 5.664 61.333 ;
     RECT  46.824 60.467 47.808 89.317 ;
     RECT  2.712 61.237 4.08 61.379 ;
     RECT  4.248 61.333 5.664 65.027 ;
     RECT  2.712 61.379 4.224 65.027 ;
     RECT  60.408 79.765 61.536 89.413 ;
     RECT  89.304 83.653 90.576 89.461 ;
     RECT  37.128 88.403 38.088 88.885 ;
     RECT  48.456 88.403 48.792 89.317 ;
     RECT  2.712 88.789 4.176 90.659 ;
     RECT  4.2 88.789 5.664 89.939 ;
     RECT  9.528 88.789 10.896 88.885 ;
     RECT  51.72 88.789 52.752 89.845 ;
     RECT  37.464 88.885 38.088 89.413 ;
     RECT  32.088 88.979 32.376 89.027 ;
     RECT  35.448 88.979 36.432 89.941 ;
     RECT  57.912 88.979 59.904 89.317 ;
     RECT  31.848 89.027 32.376 89.461 ;
     RECT  71.16 89.125 72.6 90.659 ;
     RECT  85.896 89.125 87.264 89.413 ;
     RECT  40.512 89.317 41.712 89.747 ;
     RECT  48.456 89.317 50.064 89.365 ;
     RECT  58.68 89.317 59.904 89.989 ;
     RECT  19.848 89.365 21.072 89.461 ;
     RECT  48.456 89.365 49.92 90.037 ;
     RECT  11.976 89.413 13.2 90.083 ;
     RECT  60.504 89.413 61.536 91.093 ;
     RECT  85.896 89.413 87.168 89.461 ;
     RECT  19.896 89.461 21.072 90.373 ;
     RECT  31.848 89.461 33.84 89.845 ;
     RECT  85.896 89.461 86.976 90.469 ;
     RECT  89.448 89.461 90.576 89.939 ;
     RECT  18.192 89.699 18.48 90.565 ;
     RECT  24.312 89.843 24.408 90.949 ;
     RECT  31.848 89.845 33.792 90.037 ;
     RECT  55.272 89.845 56.4 90.037 ;
     RECT  89.448 89.939 89.496 90.565 ;
     RECT  58.776 89.989 59.904 90.517 ;
     RECT  48.456 90.037 49.68 90.565 ;
     RECT  78.696 90.037 80.16 91.717 ;
     RECT  22.968 90.373 24 91.669 ;
     RECT  21.192 90.421 22.56 92.341 ;
     RECT  17.352 90.565 18.48 90.901 ;
     RECT  17.448 90.901 18.48 92.341 ;
     RECT  69.456 91.235 69.48 92.341 ;
     RECT  64.392 91.331 65.472 92.341 ;
     RECT  78.696 91.717 79.968 92.245 ;
     RECT  38.04 91.765 39.552 92.341 ;
     RECT  71.4 92.197 72.6 92.341 ;
     RECT  5.064 92.341 6.288 92.389 ;
     RECT  16.056 92.341 17.232 92.389 ;
     RECT  43.032 92.341 44.016 92.533 ;
     RECT  64.488 92.341 65.472 92.533 ;
     RECT  5.208 92.389 6.288 92.485 ;
     RECT  16.2 92.389 17.232 92.869 ;
  END
END dsfd_vm_static_landing_lane1
END LIBRARY
